VERSION 5.8 ;
BUSBITCHARS "[]" ;
DIVIDERCHAR "/" ;
UNITS
    DATABASE MICRONS 1000 ;
END UNITS

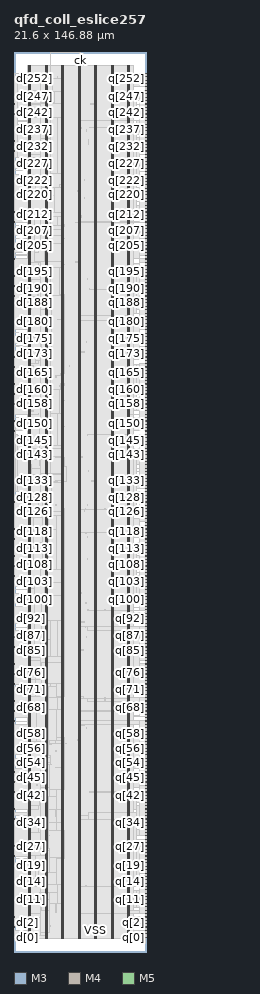
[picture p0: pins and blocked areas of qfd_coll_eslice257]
MACRO qfd_coll_eslice257
  FOREIGN qfd_coll_eslice257 0 0 ;
  CLASS BLOCK ;
  SIZE 21.6 BY 146.88 ;
  PIN ck
    DIRECTION INPUT ;
    USE SIGNAL ;
    PORT
      LAYER M3 ;
        RECT  10.8 146.842 10.818 146.88 ;
    END
    PORT
      LAYER M3 ;
        RECT  10.8 146.731 10.818 146.861 ;
    END
  END ck
  PIN d[0]
    DIRECTION INPUT ;
    USE SIGNAL ;
    PORT
      LAYER M4 ;
        RECT  0 2.4 0.084 2.424 ;
    END
  END d[0]
  PIN d[100]
    DIRECTION INPUT ;
    USE SIGNAL ;
    PORT
      LAYER M4 ;
        RECT  0 57.456 0.084 57.48 ;
    END
  END d[100]
  PIN d[101]
    DIRECTION INPUT ;
    USE SIGNAL ;
    PORT
      LAYER M4 ;
        RECT  0 58.032 0.084 58.056 ;
    END
  END d[101]
  PIN d[102]
    DIRECTION INPUT ;
    USE SIGNAL ;
    PORT
      LAYER M4 ;
        RECT  0 58.56 0.084 58.584 ;
    END
  END d[102]
  PIN d[103]
    DIRECTION INPUT ;
    USE SIGNAL ;
    PORT
      LAYER M4 ;
        RECT  0 59.136 0.084 59.16 ;
    END
  END d[103]
  PIN d[104]
    DIRECTION INPUT ;
    USE SIGNAL ;
    PORT
      LAYER M4 ;
        RECT  0 59.664 0.084 59.688 ;
    END
  END d[104]
  PIN d[105]
    DIRECTION INPUT ;
    USE SIGNAL ;
    PORT
      LAYER M4 ;
        RECT  0 60.24 0.084 60.264 ;
    END
  END d[105]
  PIN d[106]
    DIRECTION INPUT ;
    USE SIGNAL ;
    PORT
      LAYER M4 ;
        RECT  0 60.768 0.084 60.792 ;
    END
  END d[106]
  PIN d[107]
    DIRECTION INPUT ;
    USE SIGNAL ;
    PORT
      LAYER M4 ;
        RECT  0 61.344 0.084 61.368 ;
    END
  END d[107]
  PIN d[108]
    DIRECTION INPUT ;
    USE SIGNAL ;
    PORT
      LAYER M4 ;
        RECT  0 61.872 0.084 61.896 ;
    END
  END d[108]
  PIN d[109]
    DIRECTION INPUT ;
    USE SIGNAL ;
    PORT
      LAYER M4 ;
        RECT  0 62.448 0.084 62.472 ;
    END
  END d[109]
  PIN d[10]
    DIRECTION INPUT ;
    USE SIGNAL ;
    PORT
      LAYER M4 ;
        RECT  0 7.92 0.084 7.944 ;
    END
  END d[10]
  PIN d[110]
    DIRECTION INPUT ;
    USE SIGNAL ;
    PORT
      LAYER M4 ;
        RECT  0 62.976 0.084 63 ;
    END
  END d[110]
  PIN d[111]
    DIRECTION INPUT ;
    USE SIGNAL ;
    PORT
      LAYER M4 ;
        RECT  0 63.552 0.084 63.576 ;
    END
  END d[111]
  PIN d[112]
    DIRECTION INPUT ;
    USE SIGNAL ;
    PORT
      LAYER M4 ;
        RECT  0 64.08 0.084 64.104 ;
    END
  END d[112]
  PIN d[113]
    DIRECTION INPUT ;
    USE SIGNAL ;
    PORT
      LAYER M4 ;
        RECT  0 64.608 0.084 64.632 ;
    END
  END d[113]
  PIN d[114]
    DIRECTION INPUT ;
    USE SIGNAL ;
    PORT
      LAYER M4 ;
        RECT  0 65.184 0.084 65.208 ;
    END
  END d[114]
  PIN d[115]
    DIRECTION INPUT ;
    USE SIGNAL ;
    PORT
      LAYER M4 ;
        RECT  0 65.712 0.084 65.736 ;
    END
  END d[115]
  PIN d[116]
    DIRECTION INPUT ;
    USE SIGNAL ;
    PORT
      LAYER M4 ;
        RECT  0 66.288 0.084 66.312 ;
    END
  END d[116]
  PIN d[117]
    DIRECTION INPUT ;
    USE SIGNAL ;
    PORT
      LAYER M4 ;
        RECT  0 66.816 0.084 66.84 ;
    END
  END d[117]
  PIN d[118]
    DIRECTION INPUT ;
    USE SIGNAL ;
    PORT
      LAYER M4 ;
        RECT  0 67.392 0.084 67.416 ;
    END
  END d[118]
  PIN d[119]
    DIRECTION INPUT ;
    USE SIGNAL ;
    PORT
      LAYER M4 ;
        RECT  0 67.92 0.084 67.944 ;
    END
  END d[119]
  PIN d[11]
    DIRECTION INPUT ;
    USE SIGNAL ;
    PORT
      LAYER M4 ;
        RECT  0 8.496 0.084 8.52 ;
    END
  END d[11]
  PIN d[120]
    DIRECTION INPUT ;
    USE SIGNAL ;
    PORT
      LAYER M4 ;
        RECT  0 68.496 0.084 68.52 ;
    END
  END d[120]
  PIN d[121]
    DIRECTION INPUT ;
    USE SIGNAL ;
    PORT
      LAYER M4 ;
        RECT  0 69.024 0.084 69.048 ;
    END
  END d[121]
  PIN d[122]
    DIRECTION INPUT ;
    USE SIGNAL ;
    PORT
      LAYER M4 ;
        RECT  0 69.6 0.084 69.624 ;
    END
  END d[122]
  PIN d[123]
    DIRECTION INPUT ;
    USE SIGNAL ;
    PORT
      LAYER M4 ;
        RECT  0 70.128 0.084 70.152 ;
    END
  END d[123]
  PIN d[124]
    DIRECTION INPUT ;
    USE SIGNAL ;
    PORT
      LAYER M4 ;
        RECT  0 70.704 0.084 70.728 ;
    END
  END d[124]
  PIN d[125]
    DIRECTION INPUT ;
    USE SIGNAL ;
    PORT
      LAYER M4 ;
        RECT  0 71.232 0.084 71.256 ;
    END
  END d[125]
  PIN d[126]
    DIRECTION INPUT ;
    USE SIGNAL ;
    PORT
      LAYER M4 ;
        RECT  0 71.808 0.084 71.832 ;
    END
  END d[126]
  PIN d[127]
    DIRECTION INPUT ;
    USE SIGNAL ;
    PORT
      LAYER M4 ;
        RECT  0 72.336 0.084 72.36 ;
    END
  END d[127]
  PIN d[128]
    DIRECTION INPUT ;
    USE SIGNAL ;
    PORT
      LAYER M4 ;
        RECT  0 72.912 0.084 72.936 ;
    END
  END d[128]
  PIN d[129]
    DIRECTION INPUT ;
    USE SIGNAL ;
    PORT
      LAYER M4 ;
        RECT  0 73.44 0.084 73.464 ;
    END
  END d[129]
  PIN d[12]
    DIRECTION INPUT ;
    USE SIGNAL ;
    PORT
      LAYER M4 ;
        RECT  0 9.024 0.084 9.048 ;
    END
  END d[12]
  PIN d[130]
    DIRECTION INPUT ;
    USE SIGNAL ;
    PORT
      LAYER M4 ;
        RECT  0 73.968 0.084 73.992 ;
    END
  END d[130]
  PIN d[131]
    DIRECTION INPUT ;
    USE SIGNAL ;
    PORT
      LAYER M4 ;
        RECT  0 74.544 0.084 74.568 ;
    END
  END d[131]
  PIN d[132]
    DIRECTION INPUT ;
    USE SIGNAL ;
    PORT
      LAYER M4 ;
        RECT  0 75.072 0.084 75.096 ;
    END
  END d[132]
  PIN d[133]
    DIRECTION INPUT ;
    USE SIGNAL ;
    PORT
      LAYER M4 ;
        RECT  0 75.648 0.084 75.672 ;
    END
  END d[133]
  PIN d[134]
    DIRECTION INPUT ;
    USE SIGNAL ;
    PORT
      LAYER M4 ;
        RECT  0 76.176 0.084 76.2 ;
    END
  END d[134]
  PIN d[135]
    DIRECTION INPUT ;
    USE SIGNAL ;
    PORT
      LAYER M4 ;
        RECT  0 76.752 0.084 76.776 ;
    END
  END d[135]
  PIN d[136]
    DIRECTION INPUT ;
    USE SIGNAL ;
    PORT
      LAYER M4 ;
        RECT  0 77.28 0.084 77.304 ;
    END
  END d[136]
  PIN d[137]
    DIRECTION INPUT ;
    USE SIGNAL ;
    PORT
      LAYER M4 ;
        RECT  0 77.856 0.084 77.88 ;
    END
  END d[137]
  PIN d[138]
    DIRECTION INPUT ;
    USE SIGNAL ;
    PORT
      LAYER M4 ;
        RECT  0 78.384 0.084 78.408 ;
    END
  END d[138]
  PIN d[139]
    DIRECTION INPUT ;
    USE SIGNAL ;
    PORT
      LAYER M4 ;
        RECT  0 78.96 0.084 78.984 ;
    END
  END d[139]
  PIN d[13]
    DIRECTION INPUT ;
    USE SIGNAL ;
    PORT
      LAYER M4 ;
        RECT  0 9.6 0.084 9.624 ;
    END
  END d[13]
  PIN d[140]
    DIRECTION INPUT ;
    USE SIGNAL ;
    PORT
      LAYER M4 ;
        RECT  0 79.488 0.084 79.512 ;
    END
  END d[140]
  PIN d[141]
    DIRECTION INPUT ;
    USE SIGNAL ;
    PORT
      LAYER M4 ;
        RECT  0 80.064 0.084 80.088 ;
    END
  END d[141]
  PIN d[142]
    DIRECTION INPUT ;
    USE SIGNAL ;
    PORT
      LAYER M4 ;
        RECT  0 80.592 0.084 80.616 ;
    END
  END d[142]
  PIN d[143]
    DIRECTION INPUT ;
    USE SIGNAL ;
    PORT
      LAYER M4 ;
        RECT  0 81.168 0.084 81.192 ;
    END
  END d[143]
  PIN d[144]
    DIRECTION INPUT ;
    USE SIGNAL ;
    PORT
      LAYER M4 ;
        RECT  0 81.696 0.084 81.72 ;
    END
  END d[144]
  PIN d[145]
    DIRECTION INPUT ;
    USE SIGNAL ;
    PORT
      LAYER M4 ;
        RECT  0 82.224 0.084 82.248 ;
    END
  END d[145]
  PIN d[146]
    DIRECTION INPUT ;
    USE SIGNAL ;
    PORT
      LAYER M4 ;
        RECT  0 82.8 0.084 82.824 ;
    END
  END d[146]
  PIN d[147]
    DIRECTION INPUT ;
    USE SIGNAL ;
    PORT
      LAYER M4 ;
        RECT  0 83.328 0.084 83.352 ;
    END
  END d[147]
  PIN d[148]
    DIRECTION INPUT ;
    USE SIGNAL ;
    PORT
      LAYER M4 ;
        RECT  0 83.904 0.084 83.928 ;
    END
  END d[148]
  PIN d[149]
    DIRECTION INPUT ;
    USE SIGNAL ;
    PORT
      LAYER M4 ;
        RECT  0 84.432 0.084 84.456 ;
    END
  END d[149]
  PIN d[14]
    DIRECTION INPUT ;
    USE SIGNAL ;
    PORT
      LAYER M4 ;
        RECT  0 10.128 0.084 10.152 ;
    END
  END d[14]
  PIN d[150]
    DIRECTION INPUT ;
    USE SIGNAL ;
    PORT
      LAYER M4 ;
        RECT  0 85.008 0.084 85.032 ;
    END
  END d[150]
  PIN d[151]
    DIRECTION INPUT ;
    USE SIGNAL ;
    PORT
      LAYER M4 ;
        RECT  0 85.536 0.084 85.56 ;
    END
  END d[151]
  PIN d[152]
    DIRECTION INPUT ;
    USE SIGNAL ;
    PORT
      LAYER M4 ;
        RECT  0 86.112 0.084 86.136 ;
    END
  END d[152]
  PIN d[153]
    DIRECTION INPUT ;
    USE SIGNAL ;
    PORT
      LAYER M4 ;
        RECT  0 86.64 0.084 86.664 ;
    END
  END d[153]
  PIN d[154]
    DIRECTION INPUT ;
    USE SIGNAL ;
    PORT
      LAYER M4 ;
        RECT  0 87.216 0.084 87.24 ;
    END
  END d[154]
  PIN d[155]
    DIRECTION INPUT ;
    USE SIGNAL ;
    PORT
      LAYER M4 ;
        RECT  0 87.744 0.084 87.768 ;
    END
  END d[155]
  PIN d[156]
    DIRECTION INPUT ;
    USE SIGNAL ;
    PORT
      LAYER M4 ;
        RECT  0 88.32 0.084 88.344 ;
    END
  END d[156]
  PIN d[157]
    DIRECTION INPUT ;
    USE SIGNAL ;
    PORT
      LAYER M4 ;
        RECT  0 88.848 0.084 88.872 ;
    END
  END d[157]
  PIN d[158]
    DIRECTION INPUT ;
    USE SIGNAL ;
    PORT
      LAYER M4 ;
        RECT  0 89.424 0.084 89.448 ;
    END
  END d[158]
  PIN d[159]
    DIRECTION INPUT ;
    USE SIGNAL ;
    PORT
      LAYER M4 ;
        RECT  0 89.952 0.084 89.976 ;
    END
  END d[159]
  PIN d[15]
    DIRECTION INPUT ;
    USE SIGNAL ;
    PORT
      LAYER M4 ;
        RECT  0 10.704 0.084 10.728 ;
    END
  END d[15]
  PIN d[160]
    DIRECTION INPUT ;
    USE SIGNAL ;
    PORT
      LAYER M4 ;
        RECT  0 90.528 0.084 90.552 ;
    END
  END d[160]
  PIN d[161]
    DIRECTION INPUT ;
    USE SIGNAL ;
    PORT
      LAYER M4 ;
        RECT  0 91.056 0.084 91.08 ;
    END
  END d[161]
  PIN d[162]
    DIRECTION INPUT ;
    USE SIGNAL ;
    PORT
      LAYER M4 ;
        RECT  0 91.584 0.084 91.608 ;
    END
  END d[162]
  PIN d[163]
    DIRECTION INPUT ;
    USE SIGNAL ;
    PORT
      LAYER M4 ;
        RECT  0 92.16 0.084 92.184 ;
    END
  END d[163]
  PIN d[164]
    DIRECTION INPUT ;
    USE SIGNAL ;
    PORT
      LAYER M4 ;
        RECT  0 92.688 0.084 92.712 ;
    END
  END d[164]
  PIN d[165]
    DIRECTION INPUT ;
    USE SIGNAL ;
    PORT
      LAYER M4 ;
        RECT  0 93.264 0.084 93.288 ;
    END
  END d[165]
  PIN d[166]
    DIRECTION INPUT ;
    USE SIGNAL ;
    PORT
      LAYER M4 ;
        RECT  0 93.792 0.084 93.816 ;
    END
  END d[166]
  PIN d[167]
    DIRECTION INPUT ;
    USE SIGNAL ;
    PORT
      LAYER M4 ;
        RECT  0 94.368 0.084 94.392 ;
    END
  END d[167]
  PIN d[168]
    DIRECTION INPUT ;
    USE SIGNAL ;
    PORT
      LAYER M4 ;
        RECT  0 94.896 0.084 94.92 ;
    END
  END d[168]
  PIN d[169]
    DIRECTION INPUT ;
    USE SIGNAL ;
    PORT
      LAYER M4 ;
        RECT  0 95.472 0.084 95.496 ;
    END
  END d[169]
  PIN d[16]
    DIRECTION INPUT ;
    USE SIGNAL ;
    PORT
      LAYER M4 ;
        RECT  0 11.232 0.084 11.256 ;
    END
  END d[16]
  PIN d[170]
    DIRECTION INPUT ;
    USE SIGNAL ;
    PORT
      LAYER M4 ;
        RECT  0 96 0.084 96.024 ;
    END
  END d[170]
  PIN d[171]
    DIRECTION INPUT ;
    USE SIGNAL ;
    PORT
      LAYER M4 ;
        RECT  0 96.576 0.084 96.6 ;
    END
  END d[171]
  PIN d[172]
    DIRECTION INPUT ;
    USE SIGNAL ;
    PORT
      LAYER M4 ;
        RECT  0 97.104 0.084 97.128 ;
    END
  END d[172]
  PIN d[173]
    DIRECTION INPUT ;
    USE SIGNAL ;
    PORT
      LAYER M4 ;
        RECT  0 97.68 0.084 97.704 ;
    END
  END d[173]
  PIN d[174]
    DIRECTION INPUT ;
    USE SIGNAL ;
    PORT
      LAYER M4 ;
        RECT  0 98.208 0.084 98.232 ;
    END
  END d[174]
  PIN d[175]
    DIRECTION INPUT ;
    USE SIGNAL ;
    PORT
      LAYER M4 ;
        RECT  0 98.784 0.084 98.808 ;
    END
  END d[175]
  PIN d[176]
    DIRECTION INPUT ;
    USE SIGNAL ;
    PORT
      LAYER M4 ;
        RECT  0 99.312 0.084 99.336 ;
    END
  END d[176]
  PIN d[177]
    DIRECTION INPUT ;
    USE SIGNAL ;
    PORT
      LAYER M4 ;
        RECT  0 99.84 0.084 99.864 ;
    END
  END d[177]
  PIN d[178]
    DIRECTION INPUT ;
    USE SIGNAL ;
    PORT
      LAYER M4 ;
        RECT  0 100.416 0.084 100.44 ;
    END
  END d[178]
  PIN d[179]
    DIRECTION INPUT ;
    USE SIGNAL ;
    PORT
      LAYER M4 ;
        RECT  0 100.944 0.084 100.968 ;
    END
  END d[179]
  PIN d[17]
    DIRECTION INPUT ;
    USE SIGNAL ;
    PORT
      LAYER M4 ;
        RECT  0 11.76 0.084 11.784 ;
    END
  END d[17]
  PIN d[180]
    DIRECTION INPUT ;
    USE SIGNAL ;
    PORT
      LAYER M4 ;
        RECT  0 101.52 0.084 101.544 ;
    END
  END d[180]
  PIN d[181]
    DIRECTION INPUT ;
    USE SIGNAL ;
    PORT
      LAYER M4 ;
        RECT  0 102.048 0.084 102.072 ;
    END
  END d[181]
  PIN d[182]
    DIRECTION INPUT ;
    USE SIGNAL ;
    PORT
      LAYER M4 ;
        RECT  0 102.624 0.084 102.648 ;
    END
  END d[182]
  PIN d[183]
    DIRECTION INPUT ;
    USE SIGNAL ;
    PORT
      LAYER M4 ;
        RECT  0 103.152 0.084 103.176 ;
    END
  END d[183]
  PIN d[184]
    DIRECTION INPUT ;
    USE SIGNAL ;
    PORT
      LAYER M4 ;
        RECT  0 103.728 0.084 103.752 ;
    END
  END d[184]
  PIN d[185]
    DIRECTION INPUT ;
    USE SIGNAL ;
    PORT
      LAYER M4 ;
        RECT  0 104.256 0.084 104.28 ;
    END
  END d[185]
  PIN d[186]
    DIRECTION INPUT ;
    USE SIGNAL ;
    PORT
      LAYER M4 ;
        RECT  0 104.832 0.084 104.856 ;
    END
  END d[186]
  PIN d[187]
    DIRECTION INPUT ;
    USE SIGNAL ;
    PORT
      LAYER M4 ;
        RECT  0 105.36 0.084 105.384 ;
    END
  END d[187]
  PIN d[188]
    DIRECTION INPUT ;
    USE SIGNAL ;
    PORT
      LAYER M4 ;
        RECT  0 105.936 0.084 105.96 ;
    END
  END d[188]
  PIN d[189]
    DIRECTION INPUT ;
    USE SIGNAL ;
    PORT
      LAYER M4 ;
        RECT  0 106.464 0.084 106.488 ;
    END
  END d[189]
  PIN d[18]
    DIRECTION INPUT ;
    USE SIGNAL ;
    PORT
      LAYER M4 ;
        RECT  0 12.336 0.084 12.36 ;
    END
  END d[18]
  PIN d[190]
    DIRECTION INPUT ;
    USE SIGNAL ;
    PORT
      LAYER M4 ;
        RECT  0 107.04 0.084 107.064 ;
    END
  END d[190]
  PIN d[191]
    DIRECTION INPUT ;
    USE SIGNAL ;
    PORT
      LAYER M4 ;
        RECT  0 107.568 0.084 107.592 ;
    END
  END d[191]
  PIN d[192]
    DIRECTION INPUT ;
    USE SIGNAL ;
    PORT
      LAYER M4 ;
        RECT  0 108.144 0.084 108.168 ;
    END
  END d[192]
  PIN d[193]
    DIRECTION INPUT ;
    USE SIGNAL ;
    PORT
      LAYER M4 ;
        RECT  0 108.672 0.084 108.696 ;
    END
  END d[193]
  PIN d[194]
    DIRECTION INPUT ;
    USE SIGNAL ;
    PORT
      LAYER M4 ;
        RECT  0 109.2 0.084 109.224 ;
    END
  END d[194]
  PIN d[195]
    DIRECTION INPUT ;
    USE SIGNAL ;
    PORT
      LAYER M4 ;
        RECT  0 109.776 0.084 109.8 ;
    END
  END d[195]
  PIN d[196]
    DIRECTION INPUT ;
    USE SIGNAL ;
    PORT
      LAYER M4 ;
        RECT  0 110.304 0.084 110.328 ;
    END
  END d[196]
  PIN d[197]
    DIRECTION INPUT ;
    USE SIGNAL ;
    PORT
      LAYER M4 ;
        RECT  0 110.88 0.084 110.904 ;
    END
  END d[197]
  PIN d[198]
    DIRECTION INPUT ;
    USE SIGNAL ;
    PORT
      LAYER M4 ;
        RECT  0 111.408 0.084 111.432 ;
    END
  END d[198]
  PIN d[199]
    DIRECTION INPUT ;
    USE SIGNAL ;
    PORT
      LAYER M4 ;
        RECT  0 111.984 0.084 112.008 ;
    END
  END d[199]
  PIN d[19]
    DIRECTION INPUT ;
    USE SIGNAL ;
    PORT
      LAYER M4 ;
        RECT  0 12.864 0.084 12.888 ;
    END
  END d[19]
  PIN d[1]
    DIRECTION INPUT ;
    USE SIGNAL ;
    PORT
      LAYER M4 ;
        RECT  0 2.976 0.084 3 ;
    END
  END d[1]
  PIN d[200]
    DIRECTION INPUT ;
    USE SIGNAL ;
    PORT
      LAYER M4 ;
        RECT  0 112.512 0.084 112.536 ;
    END
  END d[200]
  PIN d[201]
    DIRECTION INPUT ;
    USE SIGNAL ;
    PORT
      LAYER M4 ;
        RECT  0 113.088 0.084 113.112 ;
    END
  END d[201]
  PIN d[202]
    DIRECTION INPUT ;
    USE SIGNAL ;
    PORT
      LAYER M4 ;
        RECT  0 113.616 0.084 113.64 ;
    END
  END d[202]
  PIN d[203]
    DIRECTION INPUT ;
    USE SIGNAL ;
    PORT
      LAYER M4 ;
        RECT  0 114.192 0.084 114.216 ;
    END
  END d[203]
  PIN d[204]
    DIRECTION INPUT ;
    USE SIGNAL ;
    PORT
      LAYER M4 ;
        RECT  0 114.72 0.084 114.744 ;
    END
  END d[204]
  PIN d[205]
    DIRECTION INPUT ;
    USE SIGNAL ;
    PORT
      LAYER M4 ;
        RECT  0 115.296 0.084 115.32 ;
    END
  END d[205]
  PIN d[206]
    DIRECTION INPUT ;
    USE SIGNAL ;
    PORT
      LAYER M4 ;
        RECT  0 115.824 0.084 115.848 ;
    END
  END d[206]
  PIN d[207]
    DIRECTION INPUT ;
    USE SIGNAL ;
    PORT
      LAYER M4 ;
        RECT  0 116.4 0.084 116.424 ;
    END
  END d[207]
  PIN d[208]
    DIRECTION INPUT ;
    USE SIGNAL ;
    PORT
      LAYER M4 ;
        RECT  0 116.928 0.084 116.952 ;
    END
  END d[208]
  PIN d[209]
    DIRECTION INPUT ;
    USE SIGNAL ;
    PORT
      LAYER M4 ;
        RECT  0 117.456 0.084 117.48 ;
    END
  END d[209]
  PIN d[20]
    DIRECTION INPUT ;
    USE SIGNAL ;
    PORT
      LAYER M4 ;
        RECT  0 13.44 0.084 13.464 ;
    END
  END d[20]
  PIN d[210]
    DIRECTION INPUT ;
    USE SIGNAL ;
    PORT
      LAYER M4 ;
        RECT  0 118.032 0.084 118.056 ;
    END
  END d[210]
  PIN d[211]
    DIRECTION INPUT ;
    USE SIGNAL ;
    PORT
      LAYER M4 ;
        RECT  0 118.56 0.084 118.584 ;
    END
  END d[211]
  PIN d[212]
    DIRECTION INPUT ;
    USE SIGNAL ;
    PORT
      LAYER M4 ;
        RECT  0 119.136 0.084 119.16 ;
    END
  END d[212]
  PIN d[213]
    DIRECTION INPUT ;
    USE SIGNAL ;
    PORT
      LAYER M4 ;
        RECT  0 119.664 0.084 119.688 ;
    END
  END d[213]
  PIN d[214]
    DIRECTION INPUT ;
    USE SIGNAL ;
    PORT
      LAYER M4 ;
        RECT  0 120.24 0.084 120.264 ;
    END
  END d[214]
  PIN d[215]
    DIRECTION INPUT ;
    USE SIGNAL ;
    PORT
      LAYER M4 ;
        RECT  0 120.768 0.084 120.792 ;
    END
  END d[215]
  PIN d[216]
    DIRECTION INPUT ;
    USE SIGNAL ;
    PORT
      LAYER M4 ;
        RECT  0 121.344 0.084 121.368 ;
    END
  END d[216]
  PIN d[217]
    DIRECTION INPUT ;
    USE SIGNAL ;
    PORT
      LAYER M4 ;
        RECT  0 121.872 0.084 121.896 ;
    END
  END d[217]
  PIN d[218]
    DIRECTION INPUT ;
    USE SIGNAL ;
    PORT
      LAYER M4 ;
        RECT  0 122.448 0.084 122.472 ;
    END
  END d[218]
  PIN d[219]
    DIRECTION INPUT ;
    USE SIGNAL ;
    PORT
      LAYER M4 ;
        RECT  0 122.976 0.084 123 ;
    END
  END d[219]
  PIN d[21]
    DIRECTION INPUT ;
    USE SIGNAL ;
    PORT
      LAYER M4 ;
        RECT  0 13.968 0.084 13.992 ;
    END
  END d[21]
  PIN d[220]
    DIRECTION INPUT ;
    USE SIGNAL ;
    PORT
      LAYER M4 ;
        RECT  0 123.552 0.084 123.576 ;
    END
  END d[220]
  PIN d[221]
    DIRECTION INPUT ;
    USE SIGNAL ;
    PORT
      LAYER M4 ;
        RECT  0 124.08 0.084 124.104 ;
    END
  END d[221]
  PIN d[222]
    DIRECTION INPUT ;
    USE SIGNAL ;
    PORT
      LAYER M4 ;
        RECT  0 124.656 0.084 124.68 ;
    END
  END d[222]
  PIN d[223]
    DIRECTION INPUT ;
    USE SIGNAL ;
    PORT
      LAYER M4 ;
        RECT  0 125.184 0.084 125.208 ;
    END
  END d[223]
  PIN d[224]
    DIRECTION INPUT ;
    USE SIGNAL ;
    PORT
      LAYER M4 ;
        RECT  0 125.76 0.084 125.784 ;
    END
  END d[224]
  PIN d[225]
    DIRECTION INPUT ;
    USE SIGNAL ;
    PORT
      LAYER M4 ;
        RECT  0 126.288 0.084 126.312 ;
    END
  END d[225]
  PIN d[226]
    DIRECTION INPUT ;
    USE SIGNAL ;
    PORT
      LAYER M4 ;
        RECT  0 126.816 0.084 126.84 ;
    END
  END d[226]
  PIN d[227]
    DIRECTION INPUT ;
    USE SIGNAL ;
    PORT
      LAYER M4 ;
        RECT  0 127.392 0.084 127.416 ;
    END
  END d[227]
  PIN d[228]
    DIRECTION INPUT ;
    USE SIGNAL ;
    PORT
      LAYER M4 ;
        RECT  0 127.92 0.084 127.944 ;
    END
  END d[228]
  PIN d[229]
    DIRECTION INPUT ;
    USE SIGNAL ;
    PORT
      LAYER M4 ;
        RECT  0 128.496 0.084 128.52 ;
    END
  END d[229]
  PIN d[22]
    DIRECTION INPUT ;
    USE SIGNAL ;
    PORT
      LAYER M4 ;
        RECT  0 14.544 0.084 14.568 ;
    END
  END d[22]
  PIN d[230]
    DIRECTION INPUT ;
    USE SIGNAL ;
    PORT
      LAYER M4 ;
        RECT  0 129.024 0.084 129.048 ;
    END
  END d[230]
  PIN d[231]
    DIRECTION INPUT ;
    USE SIGNAL ;
    PORT
      LAYER M4 ;
        RECT  0 129.6 0.084 129.624 ;
    END
  END d[231]
  PIN d[232]
    DIRECTION INPUT ;
    USE SIGNAL ;
    PORT
      LAYER M4 ;
        RECT  0 130.128 0.084 130.152 ;
    END
  END d[232]
  PIN d[233]
    DIRECTION INPUT ;
    USE SIGNAL ;
    PORT
      LAYER M4 ;
        RECT  0 130.704 0.084 130.728 ;
    END
  END d[233]
  PIN d[234]
    DIRECTION INPUT ;
    USE SIGNAL ;
    PORT
      LAYER M4 ;
        RECT  0 131.232 0.084 131.256 ;
    END
  END d[234]
  PIN d[235]
    DIRECTION INPUT ;
    USE SIGNAL ;
    PORT
      LAYER M4 ;
        RECT  0 131.808 0.084 131.832 ;
    END
  END d[235]
  PIN d[236]
    DIRECTION INPUT ;
    USE SIGNAL ;
    PORT
      LAYER M4 ;
        RECT  0 132.336 0.084 132.36 ;
    END
  END d[236]
  PIN d[237]
    DIRECTION INPUT ;
    USE SIGNAL ;
    PORT
      LAYER M4 ;
        RECT  0 132.912 0.084 132.936 ;
    END
  END d[237]
  PIN d[238]
    DIRECTION INPUT ;
    USE SIGNAL ;
    PORT
      LAYER M4 ;
        RECT  0 133.44 0.084 133.464 ;
    END
  END d[238]
  PIN d[239]
    DIRECTION INPUT ;
    USE SIGNAL ;
    PORT
      LAYER M4 ;
        RECT  0 134.016 0.084 134.04 ;
    END
  END d[239]
  PIN d[23]
    DIRECTION INPUT ;
    USE SIGNAL ;
    PORT
      LAYER M4 ;
        RECT  0 15.072 0.084 15.096 ;
    END
  END d[23]
  PIN d[240]
    DIRECTION INPUT ;
    USE SIGNAL ;
    PORT
      LAYER M4 ;
        RECT  0 134.544 0.084 134.568 ;
    END
  END d[240]
  PIN d[241]
    DIRECTION INPUT ;
    USE SIGNAL ;
    PORT
      LAYER M4 ;
        RECT  0 135.072 0.084 135.096 ;
    END
  END d[241]
  PIN d[242]
    DIRECTION INPUT ;
    USE SIGNAL ;
    PORT
      LAYER M4 ;
        RECT  0 135.648 0.084 135.672 ;
    END
  END d[242]
  PIN d[243]
    DIRECTION INPUT ;
    USE SIGNAL ;
    PORT
      LAYER M4 ;
        RECT  0 136.176 0.084 136.2 ;
    END
  END d[243]
  PIN d[244]
    DIRECTION INPUT ;
    USE SIGNAL ;
    PORT
      LAYER M4 ;
        RECT  0 136.752 0.084 136.776 ;
    END
  END d[244]
  PIN d[245]
    DIRECTION INPUT ;
    USE SIGNAL ;
    PORT
      LAYER M4 ;
        RECT  0 137.28 0.084 137.304 ;
    END
  END d[245]
  PIN d[246]
    DIRECTION INPUT ;
    USE SIGNAL ;
    PORT
      LAYER M4 ;
        RECT  0 137.856 0.084 137.88 ;
    END
  END d[246]
  PIN d[247]
    DIRECTION INPUT ;
    USE SIGNAL ;
    PORT
      LAYER M4 ;
        RECT  0 138.384 0.084 138.408 ;
    END
  END d[247]
  PIN d[248]
    DIRECTION INPUT ;
    USE SIGNAL ;
    PORT
      LAYER M4 ;
        RECT  0 138.96 0.084 138.984 ;
    END
  END d[248]
  PIN d[249]
    DIRECTION INPUT ;
    USE SIGNAL ;
    PORT
      LAYER M4 ;
        RECT  0 139.488 0.084 139.512 ;
    END
  END d[249]
  PIN d[24]
    DIRECTION INPUT ;
    USE SIGNAL ;
    PORT
      LAYER M4 ;
        RECT  0 15.648 0.084 15.672 ;
    END
  END d[24]
  PIN d[250]
    DIRECTION INPUT ;
    USE SIGNAL ;
    PORT
      LAYER M4 ;
        RECT  0 140.064 0.084 140.088 ;
    END
  END d[250]
  PIN d[251]
    DIRECTION INPUT ;
    USE SIGNAL ;
    PORT
      LAYER M4 ;
        RECT  0 140.592 0.084 140.616 ;
    END
  END d[251]
  PIN d[252]
    DIRECTION INPUT ;
    USE SIGNAL ;
    PORT
      LAYER M4 ;
        RECT  0 141.168 0.084 141.192 ;
    END
  END d[252]
  PIN d[253]
    DIRECTION INPUT ;
    USE SIGNAL ;
    PORT
      LAYER M4 ;
        RECT  0 141.696 0.084 141.72 ;
    END
  END d[253]
  PIN d[254]
    DIRECTION INPUT ;
    USE SIGNAL ;
    PORT
      LAYER M4 ;
        RECT  0 142.272 0.084 142.296 ;
    END
  END d[254]
  PIN d[255]
    DIRECTION INPUT ;
    USE SIGNAL ;
    PORT
      LAYER M4 ;
        RECT  0 142.8 0.084 142.824 ;
    END
  END d[255]
  PIN d[256]
    DIRECTION INPUT ;
    USE SIGNAL ;
    PORT
      LAYER M4 ;
        RECT  0 143.376 0.084 143.4 ;
    END
  END d[256]
  PIN d[25]
    DIRECTION INPUT ;
    USE SIGNAL ;
    PORT
      LAYER M4 ;
        RECT  0 16.176 0.084 16.2 ;
    END
  END d[25]
  PIN d[26]
    DIRECTION INPUT ;
    USE SIGNAL ;
    PORT
      LAYER M4 ;
        RECT  0 16.752 0.084 16.776 ;
    END
  END d[26]
  PIN d[27]
    DIRECTION INPUT ;
    USE SIGNAL ;
    PORT
      LAYER M4 ;
        RECT  0 17.28 0.084 17.304 ;
    END
  END d[27]
  PIN d[28]
    DIRECTION INPUT ;
    USE SIGNAL ;
    PORT
      LAYER M4 ;
        RECT  0 17.856 0.084 17.88 ;
    END
  END d[28]
  PIN d[29]
    DIRECTION INPUT ;
    USE SIGNAL ;
    PORT
      LAYER M4 ;
        RECT  0 18.384 0.084 18.408 ;
    END
  END d[29]
  PIN d[2]
    DIRECTION INPUT ;
    USE SIGNAL ;
    PORT
      LAYER M4 ;
        RECT  0 3.504 0.084 3.528 ;
    END
  END d[2]
  PIN d[30]
    DIRECTION INPUT ;
    USE SIGNAL ;
    PORT
      LAYER M4 ;
        RECT  0 18.96 0.084 18.984 ;
    END
  END d[30]
  PIN d[31]
    DIRECTION INPUT ;
    USE SIGNAL ;
    PORT
      LAYER M4 ;
        RECT  0 19.488 0.084 19.512 ;
    END
  END d[31]
  PIN d[32]
    DIRECTION INPUT ;
    USE SIGNAL ;
    PORT
      LAYER M4 ;
        RECT  0 20.016 0.084 20.04 ;
    END
  END d[32]
  PIN d[33]
    DIRECTION INPUT ;
    USE SIGNAL ;
    PORT
      LAYER M4 ;
        RECT  0 20.592 0.084 20.616 ;
    END
  END d[33]
  PIN d[34]
    DIRECTION INPUT ;
    USE SIGNAL ;
    PORT
      LAYER M4 ;
        RECT  0 21.12 0.084 21.144 ;
    END
  END d[34]
  PIN d[35]
    DIRECTION INPUT ;
    USE SIGNAL ;
    PORT
      LAYER M4 ;
        RECT  0 21.696 0.084 21.72 ;
    END
  END d[35]
  PIN d[36]
    DIRECTION INPUT ;
    USE SIGNAL ;
    PORT
      LAYER M4 ;
        RECT  0 22.224 0.084 22.248 ;
    END
  END d[36]
  PIN d[37]
    DIRECTION INPUT ;
    USE SIGNAL ;
    PORT
      LAYER M4 ;
        RECT  0 22.8 0.084 22.824 ;
    END
  END d[37]
  PIN d[38]
    DIRECTION INPUT ;
    USE SIGNAL ;
    PORT
      LAYER M4 ;
        RECT  0 23.328 0.084 23.352 ;
    END
  END d[38]
  PIN d[39]
    DIRECTION INPUT ;
    USE SIGNAL ;
    PORT
      LAYER M4 ;
        RECT  0 23.904 0.084 23.928 ;
    END
  END d[39]
  PIN d[3]
    DIRECTION INPUT ;
    USE SIGNAL ;
    PORT
      LAYER M4 ;
        RECT  0 4.08 0.084 4.104 ;
    END
  END d[3]
  PIN d[40]
    DIRECTION INPUT ;
    USE SIGNAL ;
    PORT
      LAYER M4 ;
        RECT  0 24.432 0.084 24.456 ;
    END
  END d[40]
  PIN d[41]
    DIRECTION INPUT ;
    USE SIGNAL ;
    PORT
      LAYER M4 ;
        RECT  0 25.008 0.084 25.032 ;
    END
  END d[41]
  PIN d[42]
    DIRECTION INPUT ;
    USE SIGNAL ;
    PORT
      LAYER M4 ;
        RECT  0 25.536 0.084 25.56 ;
    END
  END d[42]
  PIN d[43]
    DIRECTION INPUT ;
    USE SIGNAL ;
    PORT
      LAYER M4 ;
        RECT  0 26.112 0.084 26.136 ;
    END
  END d[43]
  PIN d[44]
    DIRECTION INPUT ;
    USE SIGNAL ;
    PORT
      LAYER M4 ;
        RECT  0 26.64 0.084 26.664 ;
    END
  END d[44]
  PIN d[45]
    DIRECTION INPUT ;
    USE SIGNAL ;
    PORT
      LAYER M4 ;
        RECT  0 27.216 0.084 27.24 ;
    END
  END d[45]
  PIN d[46]
    DIRECTION INPUT ;
    USE SIGNAL ;
    PORT
      LAYER M4 ;
        RECT  0 27.744 0.084 27.768 ;
    END
  END d[46]
  PIN d[47]
    DIRECTION INPUT ;
    USE SIGNAL ;
    PORT
      LAYER M4 ;
        RECT  0 28.32 0.084 28.344 ;
    END
  END d[47]
  PIN d[48]
    DIRECTION INPUT ;
    USE SIGNAL ;
    PORT
      LAYER M4 ;
        RECT  0 28.848 0.084 28.872 ;
    END
  END d[48]
  PIN d[49]
    DIRECTION INPUT ;
    USE SIGNAL ;
    PORT
      LAYER M4 ;
        RECT  0 29.376 0.084 29.4 ;
    END
  END d[49]
  PIN d[4]
    DIRECTION INPUT ;
    USE SIGNAL ;
    PORT
      LAYER M4 ;
        RECT  0 4.608 0.084 4.632 ;
    END
  END d[4]
  PIN d[50]
    DIRECTION INPUT ;
    USE SIGNAL ;
    PORT
      LAYER M4 ;
        RECT  0 29.952 0.084 29.976 ;
    END
  END d[50]
  PIN d[51]
    DIRECTION INPUT ;
    USE SIGNAL ;
    PORT
      LAYER M4 ;
        RECT  0 30.48 0.084 30.504 ;
    END
  END d[51]
  PIN d[52]
    DIRECTION INPUT ;
    USE SIGNAL ;
    PORT
      LAYER M4 ;
        RECT  0 31.056 0.084 31.08 ;
    END
  END d[52]
  PIN d[53]
    DIRECTION INPUT ;
    USE SIGNAL ;
    PORT
      LAYER M4 ;
        RECT  0 31.584 0.084 31.608 ;
    END
  END d[53]
  PIN d[54]
    DIRECTION INPUT ;
    USE SIGNAL ;
    PORT
      LAYER M4 ;
        RECT  0 32.16 0.084 32.184 ;
    END
  END d[54]
  PIN d[55]
    DIRECTION INPUT ;
    USE SIGNAL ;
    PORT
      LAYER M4 ;
        RECT  0 32.688 0.084 32.712 ;
    END
  END d[55]
  PIN d[56]
    DIRECTION INPUT ;
    USE SIGNAL ;
    PORT
      LAYER M4 ;
        RECT  0 33.264 0.084 33.288 ;
    END
  END d[56]
  PIN d[57]
    DIRECTION INPUT ;
    USE SIGNAL ;
    PORT
      LAYER M4 ;
        RECT  0 33.792 0.084 33.816 ;
    END
  END d[57]
  PIN d[58]
    DIRECTION INPUT ;
    USE SIGNAL ;
    PORT
      LAYER M4 ;
        RECT  0 34.368 0.084 34.392 ;
    END
  END d[58]
  PIN d[59]
    DIRECTION INPUT ;
    USE SIGNAL ;
    PORT
      LAYER M4 ;
        RECT  0 34.896 0.084 34.92 ;
    END
  END d[59]
  PIN d[5]
    DIRECTION INPUT ;
    USE SIGNAL ;
    PORT
      LAYER M4 ;
        RECT  0 5.184 0.084 5.208 ;
    END
  END d[5]
  PIN d[60]
    DIRECTION INPUT ;
    USE SIGNAL ;
    PORT
      LAYER M4 ;
        RECT  0 35.472 0.084 35.496 ;
    END
  END d[60]
  PIN d[61]
    DIRECTION INPUT ;
    USE SIGNAL ;
    PORT
      LAYER M4 ;
        RECT  0 36 0.084 36.024 ;
    END
  END d[61]
  PIN d[62]
    DIRECTION INPUT ;
    USE SIGNAL ;
    PORT
      LAYER M4 ;
        RECT  0 36.576 0.084 36.6 ;
    END
  END d[62]
  PIN d[63]
    DIRECTION INPUT ;
    USE SIGNAL ;
    PORT
      LAYER M4 ;
        RECT  0 37.104 0.084 37.128 ;
    END
  END d[63]
  PIN d[64]
    DIRECTION INPUT ;
    USE SIGNAL ;
    PORT
      LAYER M4 ;
        RECT  0 37.68 0.084 37.704 ;
    END
  END d[64]
  PIN d[65]
    DIRECTION INPUT ;
    USE SIGNAL ;
    PORT
      LAYER M4 ;
        RECT  0 38.208 0.084 38.232 ;
    END
  END d[65]
  PIN d[66]
    DIRECTION INPUT ;
    USE SIGNAL ;
    PORT
      LAYER M4 ;
        RECT  0 38.736 0.084 38.76 ;
    END
  END d[66]
  PIN d[67]
    DIRECTION INPUT ;
    USE SIGNAL ;
    PORT
      LAYER M4 ;
        RECT  0 39.312 0.084 39.336 ;
    END
  END d[67]
  PIN d[68]
    DIRECTION INPUT ;
    USE SIGNAL ;
    PORT
      LAYER M4 ;
        RECT  0 39.84 0.084 39.864 ;
    END
  END d[68]
  PIN d[69]
    DIRECTION INPUT ;
    USE SIGNAL ;
    PORT
      LAYER M4 ;
        RECT  0 40.416 0.084 40.44 ;
    END
  END d[69]
  PIN d[6]
    DIRECTION INPUT ;
    USE SIGNAL ;
    PORT
      LAYER M4 ;
        RECT  0 5.712 0.084 5.736 ;
    END
  END d[6]
  PIN d[70]
    DIRECTION INPUT ;
    USE SIGNAL ;
    PORT
      LAYER M4 ;
        RECT  0 40.944 0.084 40.968 ;
    END
  END d[70]
  PIN d[71]
    DIRECTION INPUT ;
    USE SIGNAL ;
    PORT
      LAYER M4 ;
        RECT  0 41.52 0.084 41.544 ;
    END
  END d[71]
  PIN d[72]
    DIRECTION INPUT ;
    USE SIGNAL ;
    PORT
      LAYER M4 ;
        RECT  0 42.048 0.084 42.072 ;
    END
  END d[72]
  PIN d[73]
    DIRECTION INPUT ;
    USE SIGNAL ;
    PORT
      LAYER M4 ;
        RECT  0 42.624 0.084 42.648 ;
    END
  END d[73]
  PIN d[74]
    DIRECTION INPUT ;
    USE SIGNAL ;
    PORT
      LAYER M4 ;
        RECT  0 43.152 0.084 43.176 ;
    END
  END d[74]
  PIN d[75]
    DIRECTION INPUT ;
    USE SIGNAL ;
    PORT
      LAYER M4 ;
        RECT  0 43.728 0.084 43.752 ;
    END
  END d[75]
  PIN d[76]
    DIRECTION INPUT ;
    USE SIGNAL ;
    PORT
      LAYER M4 ;
        RECT  0 44.256 0.084 44.28 ;
    END
  END d[76]
  PIN d[77]
    DIRECTION INPUT ;
    USE SIGNAL ;
    PORT
      LAYER M4 ;
        RECT  0 44.832 0.084 44.856 ;
    END
  END d[77]
  PIN d[78]
    DIRECTION INPUT ;
    USE SIGNAL ;
    PORT
      LAYER M4 ;
        RECT  0 45.36 0.084 45.384 ;
    END
  END d[78]
  PIN d[79]
    DIRECTION INPUT ;
    USE SIGNAL ;
    PORT
      LAYER M4 ;
        RECT  0 45.936 0.084 45.96 ;
    END
  END d[79]
  PIN d[7]
    DIRECTION INPUT ;
    USE SIGNAL ;
    PORT
      LAYER M4 ;
        RECT  0 6.288 0.084 6.312 ;
    END
  END d[7]
  PIN d[80]
    DIRECTION INPUT ;
    USE SIGNAL ;
    PORT
      LAYER M4 ;
        RECT  0 46.464 0.084 46.488 ;
    END
  END d[80]
  PIN d[81]
    DIRECTION INPUT ;
    USE SIGNAL ;
    PORT
      LAYER M4 ;
        RECT  0 46.992 0.084 47.016 ;
    END
  END d[81]
  PIN d[82]
    DIRECTION INPUT ;
    USE SIGNAL ;
    PORT
      LAYER M4 ;
        RECT  0 47.568 0.084 47.592 ;
    END
  END d[82]
  PIN d[83]
    DIRECTION INPUT ;
    USE SIGNAL ;
    PORT
      LAYER M4 ;
        RECT  0 48.096 0.084 48.12 ;
    END
  END d[83]
  PIN d[84]
    DIRECTION INPUT ;
    USE SIGNAL ;
    PORT
      LAYER M4 ;
        RECT  0 48.672 0.084 48.696 ;
    END
  END d[84]
  PIN d[85]
    DIRECTION INPUT ;
    USE SIGNAL ;
    PORT
      LAYER M4 ;
        RECT  0 49.2 0.084 49.224 ;
    END
  END d[85]
  PIN d[86]
    DIRECTION INPUT ;
    USE SIGNAL ;
    PORT
      LAYER M4 ;
        RECT  0 49.776 0.084 49.8 ;
    END
  END d[86]
  PIN d[87]
    DIRECTION INPUT ;
    USE SIGNAL ;
    PORT
      LAYER M4 ;
        RECT  0 50.304 0.084 50.328 ;
    END
  END d[87]
  PIN d[88]
    DIRECTION INPUT ;
    USE SIGNAL ;
    PORT
      LAYER M4 ;
        RECT  0 50.88 0.084 50.904 ;
    END
  END d[88]
  PIN d[89]
    DIRECTION INPUT ;
    USE SIGNAL ;
    PORT
      LAYER M4 ;
        RECT  0 51.408 0.084 51.432 ;
    END
  END d[89]
  PIN d[8]
    DIRECTION INPUT ;
    USE SIGNAL ;
    PORT
      LAYER M4 ;
        RECT  0 6.816 0.084 6.84 ;
    END
  END d[8]
  PIN d[90]
    DIRECTION INPUT ;
    USE SIGNAL ;
    PORT
      LAYER M4 ;
        RECT  0 51.984 0.084 52.008 ;
    END
  END d[90]
  PIN d[91]
    DIRECTION INPUT ;
    USE SIGNAL ;
    PORT
      LAYER M4 ;
        RECT  0 52.512 0.084 52.536 ;
    END
  END d[91]
  PIN d[92]
    DIRECTION INPUT ;
    USE SIGNAL ;
    PORT
      LAYER M4 ;
        RECT  0 53.088 0.084 53.112 ;
    END
  END d[92]
  PIN d[93]
    DIRECTION INPUT ;
    USE SIGNAL ;
    PORT
      LAYER M4 ;
        RECT  0 53.616 0.084 53.64 ;
    END
  END d[93]
  PIN d[94]
    DIRECTION INPUT ;
    USE SIGNAL ;
    PORT
      LAYER M4 ;
        RECT  0 54.192 0.084 54.216 ;
    END
  END d[94]
  PIN d[95]
    DIRECTION INPUT ;
    USE SIGNAL ;
    PORT
      LAYER M4 ;
        RECT  0 54.72 0.084 54.744 ;
    END
  END d[95]
  PIN d[96]
    DIRECTION INPUT ;
    USE SIGNAL ;
    PORT
      LAYER M4 ;
        RECT  0 55.296 0.084 55.32 ;
    END
  END d[96]
  PIN d[97]
    DIRECTION INPUT ;
    USE SIGNAL ;
    PORT
      LAYER M4 ;
        RECT  0 55.824 0.084 55.848 ;
    END
  END d[97]
  PIN d[98]
    DIRECTION INPUT ;
    USE SIGNAL ;
    PORT
      LAYER M4 ;
        RECT  0 56.352 0.084 56.376 ;
    END
  END d[98]
  PIN d[99]
    DIRECTION INPUT ;
    USE SIGNAL ;
    PORT
      LAYER M4 ;
        RECT  0 56.928 0.084 56.952 ;
    END
  END d[99]
  PIN d[9]
    DIRECTION INPUT ;
    USE SIGNAL ;
    PORT
      LAYER M4 ;
        RECT  0 7.392 0.084 7.416 ;
    END
  END d[9]
  PIN q[0]
    DIRECTION OUTPUT ;
    USE SIGNAL ;
    PORT
      LAYER M4 ;
        RECT  21.516 2.4 21.6 2.424 ;
    END
  END q[0]
  PIN q[100]
    DIRECTION OUTPUT ;
    USE SIGNAL ;
    PORT
      LAYER M4 ;
        RECT  21.516 57.456 21.6 57.48 ;
    END
  END q[100]
  PIN q[101]
    DIRECTION OUTPUT ;
    USE SIGNAL ;
    PORT
      LAYER M4 ;
        RECT  21.516 58.032 21.6 58.056 ;
    END
  END q[101]
  PIN q[102]
    DIRECTION OUTPUT ;
    USE SIGNAL ;
    PORT
      LAYER M4 ;
        RECT  21.516 58.56 21.6 58.584 ;
    END
  END q[102]
  PIN q[103]
    DIRECTION OUTPUT ;
    USE SIGNAL ;
    PORT
      LAYER M4 ;
        RECT  21.516 59.136 21.6 59.16 ;
    END
  END q[103]
  PIN q[104]
    DIRECTION OUTPUT ;
    USE SIGNAL ;
    PORT
      LAYER M4 ;
        RECT  21.516 59.664 21.6 59.688 ;
    END
  END q[104]
  PIN q[105]
    DIRECTION OUTPUT ;
    USE SIGNAL ;
    PORT
      LAYER M4 ;
        RECT  21.516 60.24 21.6 60.264 ;
    END
  END q[105]
  PIN q[106]
    DIRECTION OUTPUT ;
    USE SIGNAL ;
    PORT
      LAYER M4 ;
        RECT  21.516 60.768 21.6 60.792 ;
    END
  END q[106]
  PIN q[107]
    DIRECTION OUTPUT ;
    USE SIGNAL ;
    PORT
      LAYER M4 ;
        RECT  21.516 61.344 21.6 61.368 ;
    END
  END q[107]
  PIN q[108]
    DIRECTION OUTPUT ;
    USE SIGNAL ;
    PORT
      LAYER M4 ;
        RECT  21.516 61.872 21.6 61.896 ;
    END
  END q[108]
  PIN q[109]
    DIRECTION OUTPUT ;
    USE SIGNAL ;
    PORT
      LAYER M4 ;
        RECT  21.516 62.448 21.6 62.472 ;
    END
  END q[109]
  PIN q[10]
    DIRECTION OUTPUT ;
    USE SIGNAL ;
    PORT
      LAYER M4 ;
        RECT  21.516 7.92 21.6 7.944 ;
    END
  END q[10]
  PIN q[110]
    DIRECTION OUTPUT ;
    USE SIGNAL ;
    PORT
      LAYER M4 ;
        RECT  21.516 62.976 21.6 63 ;
    END
  END q[110]
  PIN q[111]
    DIRECTION OUTPUT ;
    USE SIGNAL ;
    PORT
      LAYER M4 ;
        RECT  21.516 63.552 21.6 63.576 ;
    END
  END q[111]
  PIN q[112]
    DIRECTION OUTPUT ;
    USE SIGNAL ;
    PORT
      LAYER M4 ;
        RECT  21.516 64.08 21.6 64.104 ;
    END
  END q[112]
  PIN q[113]
    DIRECTION OUTPUT ;
    USE SIGNAL ;
    PORT
      LAYER M4 ;
        RECT  21.516 64.608 21.6 64.632 ;
    END
  END q[113]
  PIN q[114]
    DIRECTION OUTPUT ;
    USE SIGNAL ;
    PORT
      LAYER M4 ;
        RECT  21.516 65.184 21.6 65.208 ;
    END
  END q[114]
  PIN q[115]
    DIRECTION OUTPUT ;
    USE SIGNAL ;
    PORT
      LAYER M4 ;
        RECT  21.516 65.712 21.6 65.736 ;
    END
  END q[115]
  PIN q[116]
    DIRECTION OUTPUT ;
    USE SIGNAL ;
    PORT
      LAYER M4 ;
        RECT  21.516 66.288 21.6 66.312 ;
    END
  END q[116]
  PIN q[117]
    DIRECTION OUTPUT ;
    USE SIGNAL ;
    PORT
      LAYER M4 ;
        RECT  21.516 66.816 21.6 66.84 ;
    END
  END q[117]
  PIN q[118]
    DIRECTION OUTPUT ;
    USE SIGNAL ;
    PORT
      LAYER M4 ;
        RECT  21.516 67.392 21.6 67.416 ;
    END
  END q[118]
  PIN q[119]
    DIRECTION OUTPUT ;
    USE SIGNAL ;
    PORT
      LAYER M4 ;
        RECT  21.516 67.92 21.6 67.944 ;
    END
  END q[119]
  PIN q[11]
    DIRECTION OUTPUT ;
    USE SIGNAL ;
    PORT
      LAYER M4 ;
        RECT  21.516 8.496 21.6 8.52 ;
    END
  END q[11]
  PIN q[120]
    DIRECTION OUTPUT ;
    USE SIGNAL ;
    PORT
      LAYER M4 ;
        RECT  21.516 68.496 21.6 68.52 ;
    END
  END q[120]
  PIN q[121]
    DIRECTION OUTPUT ;
    USE SIGNAL ;
    PORT
      LAYER M4 ;
        RECT  21.516 69.024 21.6 69.048 ;
    END
  END q[121]
  PIN q[122]
    DIRECTION OUTPUT ;
    USE SIGNAL ;
    PORT
      LAYER M4 ;
        RECT  21.516 69.6 21.6 69.624 ;
    END
  END q[122]
  PIN q[123]
    DIRECTION OUTPUT ;
    USE SIGNAL ;
    PORT
      LAYER M4 ;
        RECT  21.516 70.128 21.6 70.152 ;
    END
  END q[123]
  PIN q[124]
    DIRECTION OUTPUT ;
    USE SIGNAL ;
    PORT
      LAYER M4 ;
        RECT  21.516 70.704 21.6 70.728 ;
    END
  END q[124]
  PIN q[125]
    DIRECTION OUTPUT ;
    USE SIGNAL ;
    PORT
      LAYER M4 ;
        RECT  21.516 71.232 21.6 71.256 ;
    END
  END q[125]
  PIN q[126]
    DIRECTION OUTPUT ;
    USE SIGNAL ;
    PORT
      LAYER M4 ;
        RECT  21.516 71.808 21.6 71.832 ;
    END
  END q[126]
  PIN q[127]
    DIRECTION OUTPUT ;
    USE SIGNAL ;
    PORT
      LAYER M4 ;
        RECT  21.516 72.336 21.6 72.36 ;
    END
  END q[127]
  PIN q[128]
    DIRECTION OUTPUT ;
    USE SIGNAL ;
    PORT
      LAYER M4 ;
        RECT  21.516 72.912 21.6 72.936 ;
    END
  END q[128]
  PIN q[129]
    DIRECTION OUTPUT ;
    USE SIGNAL ;
    PORT
      LAYER M4 ;
        RECT  21.516 73.44 21.6 73.464 ;
    END
  END q[129]
  PIN q[12]
    DIRECTION OUTPUT ;
    USE SIGNAL ;
    PORT
      LAYER M4 ;
        RECT  21.516 9.024 21.6 9.048 ;
    END
  END q[12]
  PIN q[130]
    DIRECTION OUTPUT ;
    USE SIGNAL ;
    PORT
      LAYER M4 ;
        RECT  21.516 73.968 21.6 73.992 ;
    END
  END q[130]
  PIN q[131]
    DIRECTION OUTPUT ;
    USE SIGNAL ;
    PORT
      LAYER M4 ;
        RECT  21.516 74.544 21.6 74.568 ;
    END
  END q[131]
  PIN q[132]
    DIRECTION OUTPUT ;
    USE SIGNAL ;
    PORT
      LAYER M4 ;
        RECT  21.516 75.072 21.6 75.096 ;
    END
  END q[132]
  PIN q[133]
    DIRECTION OUTPUT ;
    USE SIGNAL ;
    PORT
      LAYER M4 ;
        RECT  21.516 75.648 21.6 75.672 ;
    END
  END q[133]
  PIN q[134]
    DIRECTION OUTPUT ;
    USE SIGNAL ;
    PORT
      LAYER M4 ;
        RECT  21.516 76.176 21.6 76.2 ;
    END
  END q[134]
  PIN q[135]
    DIRECTION OUTPUT ;
    USE SIGNAL ;
    PORT
      LAYER M4 ;
        RECT  21.516 76.752 21.6 76.776 ;
    END
  END q[135]
  PIN q[136]
    DIRECTION OUTPUT ;
    USE SIGNAL ;
    PORT
      LAYER M4 ;
        RECT  21.516 77.28 21.6 77.304 ;
    END
  END q[136]
  PIN q[137]
    DIRECTION OUTPUT ;
    USE SIGNAL ;
    PORT
      LAYER M4 ;
        RECT  21.516 77.856 21.6 77.88 ;
    END
  END q[137]
  PIN q[138]
    DIRECTION OUTPUT ;
    USE SIGNAL ;
    PORT
      LAYER M4 ;
        RECT  21.516 78.384 21.6 78.408 ;
    END
  END q[138]
  PIN q[139]
    DIRECTION OUTPUT ;
    USE SIGNAL ;
    PORT
      LAYER M4 ;
        RECT  21.516 78.96 21.6 78.984 ;
    END
  END q[139]
  PIN q[13]
    DIRECTION OUTPUT ;
    USE SIGNAL ;
    PORT
      LAYER M4 ;
        RECT  21.516 9.6 21.6 9.624 ;
    END
  END q[13]
  PIN q[140]
    DIRECTION OUTPUT ;
    USE SIGNAL ;
    PORT
      LAYER M4 ;
        RECT  21.516 79.488 21.6 79.512 ;
    END
  END q[140]
  PIN q[141]
    DIRECTION OUTPUT ;
    USE SIGNAL ;
    PORT
      LAYER M4 ;
        RECT  21.516 80.064 21.6 80.088 ;
    END
  END q[141]
  PIN q[142]
    DIRECTION OUTPUT ;
    USE SIGNAL ;
    PORT
      LAYER M4 ;
        RECT  21.516 80.592 21.6 80.616 ;
    END
  END q[142]
  PIN q[143]
    DIRECTION OUTPUT ;
    USE SIGNAL ;
    PORT
      LAYER M4 ;
        RECT  21.516 81.168 21.6 81.192 ;
    END
  END q[143]
  PIN q[144]
    DIRECTION OUTPUT ;
    USE SIGNAL ;
    PORT
      LAYER M4 ;
        RECT  21.516 81.696 21.6 81.72 ;
    END
  END q[144]
  PIN q[145]
    DIRECTION OUTPUT ;
    USE SIGNAL ;
    PORT
      LAYER M4 ;
        RECT  21.516 82.224 21.6 82.248 ;
    END
  END q[145]
  PIN q[146]
    DIRECTION OUTPUT ;
    USE SIGNAL ;
    PORT
      LAYER M4 ;
        RECT  21.516 82.8 21.6 82.824 ;
    END
  END q[146]
  PIN q[147]
    DIRECTION OUTPUT ;
    USE SIGNAL ;
    PORT
      LAYER M4 ;
        RECT  21.516 83.328 21.6 83.352 ;
    END
  END q[147]
  PIN q[148]
    DIRECTION OUTPUT ;
    USE SIGNAL ;
    PORT
      LAYER M4 ;
        RECT  21.516 83.904 21.6 83.928 ;
    END
  END q[148]
  PIN q[149]
    DIRECTION OUTPUT ;
    USE SIGNAL ;
    PORT
      LAYER M4 ;
        RECT  21.516 84.432 21.6 84.456 ;
    END
  END q[149]
  PIN q[14]
    DIRECTION OUTPUT ;
    USE SIGNAL ;
    PORT
      LAYER M4 ;
        RECT  21.516 10.128 21.6 10.152 ;
    END
  END q[14]
  PIN q[150]
    DIRECTION OUTPUT ;
    USE SIGNAL ;
    PORT
      LAYER M4 ;
        RECT  21.516 85.008 21.6 85.032 ;
    END
  END q[150]
  PIN q[151]
    DIRECTION OUTPUT ;
    USE SIGNAL ;
    PORT
      LAYER M4 ;
        RECT  21.516 85.536 21.6 85.56 ;
    END
  END q[151]
  PIN q[152]
    DIRECTION OUTPUT ;
    USE SIGNAL ;
    PORT
      LAYER M4 ;
        RECT  21.516 86.112 21.6 86.136 ;
    END
  END q[152]
  PIN q[153]
    DIRECTION OUTPUT ;
    USE SIGNAL ;
    PORT
      LAYER M4 ;
        RECT  21.516 86.64 21.6 86.664 ;
    END
  END q[153]
  PIN q[154]
    DIRECTION OUTPUT ;
    USE SIGNAL ;
    PORT
      LAYER M4 ;
        RECT  21.516 87.216 21.6 87.24 ;
    END
  END q[154]
  PIN q[155]
    DIRECTION OUTPUT ;
    USE SIGNAL ;
    PORT
      LAYER M4 ;
        RECT  21.516 87.744 21.6 87.768 ;
    END
  END q[155]
  PIN q[156]
    DIRECTION OUTPUT ;
    USE SIGNAL ;
    PORT
      LAYER M4 ;
        RECT  21.516 88.32 21.6 88.344 ;
    END
  END q[156]
  PIN q[157]
    DIRECTION OUTPUT ;
    USE SIGNAL ;
    PORT
      LAYER M4 ;
        RECT  21.516 88.848 21.6 88.872 ;
    END
  END q[157]
  PIN q[158]
    DIRECTION OUTPUT ;
    USE SIGNAL ;
    PORT
      LAYER M4 ;
        RECT  21.516 89.424 21.6 89.448 ;
    END
  END q[158]
  PIN q[159]
    DIRECTION OUTPUT ;
    USE SIGNAL ;
    PORT
      LAYER M4 ;
        RECT  21.516 89.952 21.6 89.976 ;
    END
  END q[159]
  PIN q[15]
    DIRECTION OUTPUT ;
    USE SIGNAL ;
    PORT
      LAYER M4 ;
        RECT  21.516 10.704 21.6 10.728 ;
    END
  END q[15]
  PIN q[160]
    DIRECTION OUTPUT ;
    USE SIGNAL ;
    PORT
      LAYER M4 ;
        RECT  21.516 90.528 21.6 90.552 ;
    END
  END q[160]
  PIN q[161]
    DIRECTION OUTPUT ;
    USE SIGNAL ;
    PORT
      LAYER M4 ;
        RECT  21.516 91.056 21.6 91.08 ;
    END
  END q[161]
  PIN q[162]
    DIRECTION OUTPUT ;
    USE SIGNAL ;
    PORT
      LAYER M4 ;
        RECT  21.516 91.584 21.6 91.608 ;
    END
  END q[162]
  PIN q[163]
    DIRECTION OUTPUT ;
    USE SIGNAL ;
    PORT
      LAYER M4 ;
        RECT  21.516 92.16 21.6 92.184 ;
    END
  END q[163]
  PIN q[164]
    DIRECTION OUTPUT ;
    USE SIGNAL ;
    PORT
      LAYER M4 ;
        RECT  21.516 92.688 21.6 92.712 ;
    END
  END q[164]
  PIN q[165]
    DIRECTION OUTPUT ;
    USE SIGNAL ;
    PORT
      LAYER M4 ;
        RECT  21.516 93.264 21.6 93.288 ;
    END
  END q[165]
  PIN q[166]
    DIRECTION OUTPUT ;
    USE SIGNAL ;
    PORT
      LAYER M4 ;
        RECT  21.516 93.792 21.6 93.816 ;
    END
  END q[166]
  PIN q[167]
    DIRECTION OUTPUT ;
    USE SIGNAL ;
    PORT
      LAYER M4 ;
        RECT  21.516 94.368 21.6 94.392 ;
    END
  END q[167]
  PIN q[168]
    DIRECTION OUTPUT ;
    USE SIGNAL ;
    PORT
      LAYER M4 ;
        RECT  21.516 94.896 21.6 94.92 ;
    END
  END q[168]
  PIN q[169]
    DIRECTION OUTPUT ;
    USE SIGNAL ;
    PORT
      LAYER M4 ;
        RECT  21.516 95.472 21.6 95.496 ;
    END
  END q[169]
  PIN q[16]
    DIRECTION OUTPUT ;
    USE SIGNAL ;
    PORT
      LAYER M4 ;
        RECT  21.516 11.232 21.6 11.256 ;
    END
  END q[16]
  PIN q[170]
    DIRECTION OUTPUT ;
    USE SIGNAL ;
    PORT
      LAYER M4 ;
        RECT  21.516 96 21.6 96.024 ;
    END
  END q[170]
  PIN q[171]
    DIRECTION OUTPUT ;
    USE SIGNAL ;
    PORT
      LAYER M4 ;
        RECT  21.516 96.576 21.6 96.6 ;
    END
  END q[171]
  PIN q[172]
    DIRECTION OUTPUT ;
    USE SIGNAL ;
    PORT
      LAYER M4 ;
        RECT  21.516 97.104 21.6 97.128 ;
    END
  END q[172]
  PIN q[173]
    DIRECTION OUTPUT ;
    USE SIGNAL ;
    PORT
      LAYER M4 ;
        RECT  21.516 97.68 21.6 97.704 ;
    END
  END q[173]
  PIN q[174]
    DIRECTION OUTPUT ;
    USE SIGNAL ;
    PORT
      LAYER M4 ;
        RECT  21.516 98.208 21.6 98.232 ;
    END
  END q[174]
  PIN q[175]
    DIRECTION OUTPUT ;
    USE SIGNAL ;
    PORT
      LAYER M4 ;
        RECT  21.516 98.784 21.6 98.808 ;
    END
  END q[175]
  PIN q[176]
    DIRECTION OUTPUT ;
    USE SIGNAL ;
    PORT
      LAYER M4 ;
        RECT  21.516 99.312 21.6 99.336 ;
    END
  END q[176]
  PIN q[177]
    DIRECTION OUTPUT ;
    USE SIGNAL ;
    PORT
      LAYER M4 ;
        RECT  21.516 99.84 21.6 99.864 ;
    END
  END q[177]
  PIN q[178]
    DIRECTION OUTPUT ;
    USE SIGNAL ;
    PORT
      LAYER M4 ;
        RECT  21.516 100.416 21.6 100.44 ;
    END
  END q[178]
  PIN q[179]
    DIRECTION OUTPUT ;
    USE SIGNAL ;
    PORT
      LAYER M4 ;
        RECT  21.516 100.944 21.6 100.968 ;
    END
  END q[179]
  PIN q[17]
    DIRECTION OUTPUT ;
    USE SIGNAL ;
    PORT
      LAYER M4 ;
        RECT  21.516 11.76 21.6 11.784 ;
    END
  END q[17]
  PIN q[180]
    DIRECTION OUTPUT ;
    USE SIGNAL ;
    PORT
      LAYER M4 ;
        RECT  21.516 101.52 21.6 101.544 ;
    END
  END q[180]
  PIN q[181]
    DIRECTION OUTPUT ;
    USE SIGNAL ;
    PORT
      LAYER M4 ;
        RECT  21.516 102.048 21.6 102.072 ;
    END
  END q[181]
  PIN q[182]
    DIRECTION OUTPUT ;
    USE SIGNAL ;
    PORT
      LAYER M4 ;
        RECT  21.516 102.624 21.6 102.648 ;
    END
  END q[182]
  PIN q[183]
    DIRECTION OUTPUT ;
    USE SIGNAL ;
    PORT
      LAYER M4 ;
        RECT  21.516 103.152 21.6 103.176 ;
    END
  END q[183]
  PIN q[184]
    DIRECTION OUTPUT ;
    USE SIGNAL ;
    PORT
      LAYER M4 ;
        RECT  21.516 103.728 21.6 103.752 ;
    END
  END q[184]
  PIN q[185]
    DIRECTION OUTPUT ;
    USE SIGNAL ;
    PORT
      LAYER M4 ;
        RECT  21.516 104.256 21.6 104.28 ;
    END
  END q[185]
  PIN q[186]
    DIRECTION OUTPUT ;
    USE SIGNAL ;
    PORT
      LAYER M4 ;
        RECT  21.516 104.832 21.6 104.856 ;
    END
  END q[186]
  PIN q[187]
    DIRECTION OUTPUT ;
    USE SIGNAL ;
    PORT
      LAYER M4 ;
        RECT  21.516 105.36 21.6 105.384 ;
    END
  END q[187]
  PIN q[188]
    DIRECTION OUTPUT ;
    USE SIGNAL ;
    PORT
      LAYER M4 ;
        RECT  21.516 105.936 21.6 105.96 ;
    END
  END q[188]
  PIN q[189]
    DIRECTION OUTPUT ;
    USE SIGNAL ;
    PORT
      LAYER M4 ;
        RECT  21.516 106.464 21.6 106.488 ;
    END
  END q[189]
  PIN q[18]
    DIRECTION OUTPUT ;
    USE SIGNAL ;
    PORT
      LAYER M4 ;
        RECT  21.516 12.336 21.6 12.36 ;
    END
  END q[18]
  PIN q[190]
    DIRECTION OUTPUT ;
    USE SIGNAL ;
    PORT
      LAYER M4 ;
        RECT  21.516 107.04 21.6 107.064 ;
    END
  END q[190]
  PIN q[191]
    DIRECTION OUTPUT ;
    USE SIGNAL ;
    PORT
      LAYER M4 ;
        RECT  21.516 107.568 21.6 107.592 ;
    END
  END q[191]
  PIN q[192]
    DIRECTION OUTPUT ;
    USE SIGNAL ;
    PORT
      LAYER M4 ;
        RECT  21.516 108.144 21.6 108.168 ;
    END
  END q[192]
  PIN q[193]
    DIRECTION OUTPUT ;
    USE SIGNAL ;
    PORT
      LAYER M4 ;
        RECT  21.516 108.672 21.6 108.696 ;
    END
  END q[193]
  PIN q[194]
    DIRECTION OUTPUT ;
    USE SIGNAL ;
    PORT
      LAYER M4 ;
        RECT  21.516 109.2 21.6 109.224 ;
    END
  END q[194]
  PIN q[195]
    DIRECTION OUTPUT ;
    USE SIGNAL ;
    PORT
      LAYER M4 ;
        RECT  21.516 109.776 21.6 109.8 ;
    END
  END q[195]
  PIN q[196]
    DIRECTION OUTPUT ;
    USE SIGNAL ;
    PORT
      LAYER M4 ;
        RECT  21.516 110.304 21.6 110.328 ;
    END
  END q[196]
  PIN q[197]
    DIRECTION OUTPUT ;
    USE SIGNAL ;
    PORT
      LAYER M4 ;
        RECT  21.516 110.88 21.6 110.904 ;
    END
  END q[197]
  PIN q[198]
    DIRECTION OUTPUT ;
    USE SIGNAL ;
    PORT
      LAYER M4 ;
        RECT  21.516 111.408 21.6 111.432 ;
    END
  END q[198]
  PIN q[199]
    DIRECTION OUTPUT ;
    USE SIGNAL ;
    PORT
      LAYER M4 ;
        RECT  21.516 111.984 21.6 112.008 ;
    END
  END q[199]
  PIN q[19]
    DIRECTION OUTPUT ;
    USE SIGNAL ;
    PORT
      LAYER M4 ;
        RECT  21.516 12.864 21.6 12.888 ;
    END
  END q[19]
  PIN q[1]
    DIRECTION OUTPUT ;
    USE SIGNAL ;
    PORT
      LAYER M4 ;
        RECT  21.516 2.976 21.6 3 ;
    END
  END q[1]
  PIN q[200]
    DIRECTION OUTPUT ;
    USE SIGNAL ;
    PORT
      LAYER M4 ;
        RECT  21.516 112.512 21.6 112.536 ;
    END
  END q[200]
  PIN q[201]
    DIRECTION OUTPUT ;
    USE SIGNAL ;
    PORT
      LAYER M4 ;
        RECT  21.516 113.088 21.6 113.112 ;
    END
  END q[201]
  PIN q[202]
    DIRECTION OUTPUT ;
    USE SIGNAL ;
    PORT
      LAYER M4 ;
        RECT  21.516 113.616 21.6 113.64 ;
    END
  END q[202]
  PIN q[203]
    DIRECTION OUTPUT ;
    USE SIGNAL ;
    PORT
      LAYER M4 ;
        RECT  21.516 114.192 21.6 114.216 ;
    END
  END q[203]
  PIN q[204]
    DIRECTION OUTPUT ;
    USE SIGNAL ;
    PORT
      LAYER M4 ;
        RECT  21.516 114.72 21.6 114.744 ;
    END
  END q[204]
  PIN q[205]
    DIRECTION OUTPUT ;
    USE SIGNAL ;
    PORT
      LAYER M4 ;
        RECT  21.516 115.296 21.6 115.32 ;
    END
  END q[205]
  PIN q[206]
    DIRECTION OUTPUT ;
    USE SIGNAL ;
    PORT
      LAYER M4 ;
        RECT  21.516 115.824 21.6 115.848 ;
    END
  END q[206]
  PIN q[207]
    DIRECTION OUTPUT ;
    USE SIGNAL ;
    PORT
      LAYER M4 ;
        RECT  21.516 116.4 21.6 116.424 ;
    END
  END q[207]
  PIN q[208]
    DIRECTION OUTPUT ;
    USE SIGNAL ;
    PORT
      LAYER M4 ;
        RECT  21.516 116.928 21.6 116.952 ;
    END
  END q[208]
  PIN q[209]
    DIRECTION OUTPUT ;
    USE SIGNAL ;
    PORT
      LAYER M4 ;
        RECT  21.516 117.456 21.6 117.48 ;
    END
  END q[209]
  PIN q[20]
    DIRECTION OUTPUT ;
    USE SIGNAL ;
    PORT
      LAYER M4 ;
        RECT  21.516 13.44 21.6 13.464 ;
    END
  END q[20]
  PIN q[210]
    DIRECTION OUTPUT ;
    USE SIGNAL ;
    PORT
      LAYER M4 ;
        RECT  21.516 118.032 21.6 118.056 ;
    END
  END q[210]
  PIN q[211]
    DIRECTION OUTPUT ;
    USE SIGNAL ;
    PORT
      LAYER M4 ;
        RECT  21.516 118.56 21.6 118.584 ;
    END
  END q[211]
  PIN q[212]
    DIRECTION OUTPUT ;
    USE SIGNAL ;
    PORT
      LAYER M4 ;
        RECT  21.516 119.136 21.6 119.16 ;
    END
  END q[212]
  PIN q[213]
    DIRECTION OUTPUT ;
    USE SIGNAL ;
    PORT
      LAYER M4 ;
        RECT  21.516 119.664 21.6 119.688 ;
    END
  END q[213]
  PIN q[214]
    DIRECTION OUTPUT ;
    USE SIGNAL ;
    PORT
      LAYER M4 ;
        RECT  21.516 120.24 21.6 120.264 ;
    END
  END q[214]
  PIN q[215]
    DIRECTION OUTPUT ;
    USE SIGNAL ;
    PORT
      LAYER M4 ;
        RECT  21.516 120.768 21.6 120.792 ;
    END
  END q[215]
  PIN q[216]
    DIRECTION OUTPUT ;
    USE SIGNAL ;
    PORT
      LAYER M4 ;
        RECT  21.516 121.344 21.6 121.368 ;
    END
  END q[216]
  PIN q[217]
    DIRECTION OUTPUT ;
    USE SIGNAL ;
    PORT
      LAYER M4 ;
        RECT  21.516 121.872 21.6 121.896 ;
    END
  END q[217]
  PIN q[218]
    DIRECTION OUTPUT ;
    USE SIGNAL ;
    PORT
      LAYER M4 ;
        RECT  21.516 122.448 21.6 122.472 ;
    END
  END q[218]
  PIN q[219]
    DIRECTION OUTPUT ;
    USE SIGNAL ;
    PORT
      LAYER M4 ;
        RECT  21.516 122.976 21.6 123 ;
    END
  END q[219]
  PIN q[21]
    DIRECTION OUTPUT ;
    USE SIGNAL ;
    PORT
      LAYER M4 ;
        RECT  21.516 13.968 21.6 13.992 ;
    END
  END q[21]
  PIN q[220]
    DIRECTION OUTPUT ;
    USE SIGNAL ;
    PORT
      LAYER M4 ;
        RECT  21.516 123.552 21.6 123.576 ;
    END
  END q[220]
  PIN q[221]
    DIRECTION OUTPUT ;
    USE SIGNAL ;
    PORT
      LAYER M4 ;
        RECT  21.516 124.08 21.6 124.104 ;
    END
  END q[221]
  PIN q[222]
    DIRECTION OUTPUT ;
    USE SIGNAL ;
    PORT
      LAYER M4 ;
        RECT  21.516 124.656 21.6 124.68 ;
    END
  END q[222]
  PIN q[223]
    DIRECTION OUTPUT ;
    USE SIGNAL ;
    PORT
      LAYER M4 ;
        RECT  21.516 125.184 21.6 125.208 ;
    END
  END q[223]
  PIN q[224]
    DIRECTION OUTPUT ;
    USE SIGNAL ;
    PORT
      LAYER M4 ;
        RECT  21.516 125.76 21.6 125.784 ;
    END
  END q[224]
  PIN q[225]
    DIRECTION OUTPUT ;
    USE SIGNAL ;
    PORT
      LAYER M4 ;
        RECT  21.516 126.288 21.6 126.312 ;
    END
  END q[225]
  PIN q[226]
    DIRECTION OUTPUT ;
    USE SIGNAL ;
    PORT
      LAYER M4 ;
        RECT  21.516 126.816 21.6 126.84 ;
    END
  END q[226]
  PIN q[227]
    DIRECTION OUTPUT ;
    USE SIGNAL ;
    PORT
      LAYER M4 ;
        RECT  21.516 127.392 21.6 127.416 ;
    END
  END q[227]
  PIN q[228]
    DIRECTION OUTPUT ;
    USE SIGNAL ;
    PORT
      LAYER M4 ;
        RECT  21.516 127.92 21.6 127.944 ;
    END
  END q[228]
  PIN q[229]
    DIRECTION OUTPUT ;
    USE SIGNAL ;
    PORT
      LAYER M4 ;
        RECT  21.516 128.496 21.6 128.52 ;
    END
  END q[229]
  PIN q[22]
    DIRECTION OUTPUT ;
    USE SIGNAL ;
    PORT
      LAYER M4 ;
        RECT  21.516 14.544 21.6 14.568 ;
    END
  END q[22]
  PIN q[230]
    DIRECTION OUTPUT ;
    USE SIGNAL ;
    PORT
      LAYER M4 ;
        RECT  21.516 129.024 21.6 129.048 ;
    END
  END q[230]
  PIN q[231]
    DIRECTION OUTPUT ;
    USE SIGNAL ;
    PORT
      LAYER M4 ;
        RECT  21.516 129.6 21.6 129.624 ;
    END
  END q[231]
  PIN q[232]
    DIRECTION OUTPUT ;
    USE SIGNAL ;
    PORT
      LAYER M4 ;
        RECT  21.516 130.128 21.6 130.152 ;
    END
  END q[232]
  PIN q[233]
    DIRECTION OUTPUT ;
    USE SIGNAL ;
    PORT
      LAYER M4 ;
        RECT  21.516 130.704 21.6 130.728 ;
    END
  END q[233]
  PIN q[234]
    DIRECTION OUTPUT ;
    USE SIGNAL ;
    PORT
      LAYER M4 ;
        RECT  21.516 131.232 21.6 131.256 ;
    END
  END q[234]
  PIN q[235]
    DIRECTION OUTPUT ;
    USE SIGNAL ;
    PORT
      LAYER M4 ;
        RECT  21.516 131.808 21.6 131.832 ;
    END
  END q[235]
  PIN q[236]
    DIRECTION OUTPUT ;
    USE SIGNAL ;
    PORT
      LAYER M4 ;
        RECT  21.516 132.336 21.6 132.36 ;
    END
  END q[236]
  PIN q[237]
    DIRECTION OUTPUT ;
    USE SIGNAL ;
    PORT
      LAYER M4 ;
        RECT  21.516 132.912 21.6 132.936 ;
    END
  END q[237]
  PIN q[238]
    DIRECTION OUTPUT ;
    USE SIGNAL ;
    PORT
      LAYER M4 ;
        RECT  21.516 133.44 21.6 133.464 ;
    END
  END q[238]
  PIN q[239]
    DIRECTION OUTPUT ;
    USE SIGNAL ;
    PORT
      LAYER M4 ;
        RECT  21.516 134.016 21.6 134.04 ;
    END
  END q[239]
  PIN q[23]
    DIRECTION OUTPUT ;
    USE SIGNAL ;
    PORT
      LAYER M4 ;
        RECT  21.516 15.072 21.6 15.096 ;
    END
  END q[23]
  PIN q[240]
    DIRECTION OUTPUT ;
    USE SIGNAL ;
    PORT
      LAYER M4 ;
        RECT  21.516 134.544 21.6 134.568 ;
    END
  END q[240]
  PIN q[241]
    DIRECTION OUTPUT ;
    USE SIGNAL ;
    PORT
      LAYER M4 ;
        RECT  21.516 135.072 21.6 135.096 ;
    END
  END q[241]
  PIN q[242]
    DIRECTION OUTPUT ;
    USE SIGNAL ;
    PORT
      LAYER M4 ;
        RECT  21.516 135.648 21.6 135.672 ;
    END
  END q[242]
  PIN q[243]
    DIRECTION OUTPUT ;
    USE SIGNAL ;
    PORT
      LAYER M4 ;
        RECT  21.516 136.176 21.6 136.2 ;
    END
  END q[243]
  PIN q[244]
    DIRECTION OUTPUT ;
    USE SIGNAL ;
    PORT
      LAYER M4 ;
        RECT  21.516 136.752 21.6 136.776 ;
    END
  END q[244]
  PIN q[245]
    DIRECTION OUTPUT ;
    USE SIGNAL ;
    PORT
      LAYER M4 ;
        RECT  21.516 137.28 21.6 137.304 ;
    END
  END q[245]
  PIN q[246]
    DIRECTION OUTPUT ;
    USE SIGNAL ;
    PORT
      LAYER M4 ;
        RECT  21.516 137.856 21.6 137.88 ;
    END
  END q[246]
  PIN q[247]
    DIRECTION OUTPUT ;
    USE SIGNAL ;
    PORT
      LAYER M4 ;
        RECT  21.516 138.384 21.6 138.408 ;
    END
  END q[247]
  PIN q[248]
    DIRECTION OUTPUT ;
    USE SIGNAL ;
    PORT
      LAYER M4 ;
        RECT  21.516 138.96 21.6 138.984 ;
    END
  END q[248]
  PIN q[249]
    DIRECTION OUTPUT ;
    USE SIGNAL ;
    PORT
      LAYER M4 ;
        RECT  21.516 139.488 21.6 139.512 ;
    END
  END q[249]
  PIN q[24]
    DIRECTION OUTPUT ;
    USE SIGNAL ;
    PORT
      LAYER M4 ;
        RECT  21.516 15.648 21.6 15.672 ;
    END
  END q[24]
  PIN q[250]
    DIRECTION OUTPUT ;
    USE SIGNAL ;
    PORT
      LAYER M4 ;
        RECT  21.516 140.064 21.6 140.088 ;
    END
  END q[250]
  PIN q[251]
    DIRECTION OUTPUT ;
    USE SIGNAL ;
    PORT
      LAYER M4 ;
        RECT  21.516 140.592 21.6 140.616 ;
    END
  END q[251]
  PIN q[252]
    DIRECTION OUTPUT ;
    USE SIGNAL ;
    PORT
      LAYER M4 ;
        RECT  21.516 141.168 21.6 141.192 ;
    END
  END q[252]
  PIN q[253]
    DIRECTION OUTPUT ;
    USE SIGNAL ;
    PORT
      LAYER M4 ;
        RECT  21.516 141.696 21.6 141.72 ;
    END
  END q[253]
  PIN q[254]
    DIRECTION OUTPUT ;
    USE SIGNAL ;
    PORT
      LAYER M4 ;
        RECT  21.516 142.272 21.6 142.296 ;
    END
  END q[254]
  PIN q[255]
    DIRECTION OUTPUT ;
    USE SIGNAL ;
    PORT
      LAYER M4 ;
        RECT  21.516 142.8 21.6 142.824 ;
    END
  END q[255]
  PIN q[256]
    DIRECTION OUTPUT ;
    USE SIGNAL ;
    PORT
      LAYER M4 ;
        RECT  21.516 143.376 21.6 143.4 ;
    END
  END q[256]
  PIN q[25]
    DIRECTION OUTPUT ;
    USE SIGNAL ;
    PORT
      LAYER M4 ;
        RECT  21.516 16.176 21.6 16.2 ;
    END
  END q[25]
  PIN q[26]
    DIRECTION OUTPUT ;
    USE SIGNAL ;
    PORT
      LAYER M4 ;
        RECT  21.516 16.752 21.6 16.776 ;
    END
  END q[26]
  PIN q[27]
    DIRECTION OUTPUT ;
    USE SIGNAL ;
    PORT
      LAYER M4 ;
        RECT  21.516 17.28 21.6 17.304 ;
    END
  END q[27]
  PIN q[28]
    DIRECTION OUTPUT ;
    USE SIGNAL ;
    PORT
      LAYER M4 ;
        RECT  21.516 17.856 21.6 17.88 ;
    END
  END q[28]
  PIN q[29]
    DIRECTION OUTPUT ;
    USE SIGNAL ;
    PORT
      LAYER M4 ;
        RECT  21.516 18.384 21.6 18.408 ;
    END
  END q[29]
  PIN q[2]
    DIRECTION OUTPUT ;
    USE SIGNAL ;
    PORT
      LAYER M4 ;
        RECT  21.516 3.504 21.6 3.528 ;
    END
  END q[2]
  PIN q[30]
    DIRECTION OUTPUT ;
    USE SIGNAL ;
    PORT
      LAYER M4 ;
        RECT  21.516 18.96 21.6 18.984 ;
    END
  END q[30]
  PIN q[31]
    DIRECTION OUTPUT ;
    USE SIGNAL ;
    PORT
      LAYER M4 ;
        RECT  21.516 19.488 21.6 19.512 ;
    END
  END q[31]
  PIN q[32]
    DIRECTION OUTPUT ;
    USE SIGNAL ;
    PORT
      LAYER M4 ;
        RECT  21.516 20.016 21.6 20.04 ;
    END
  END q[32]
  PIN q[33]
    DIRECTION OUTPUT ;
    USE SIGNAL ;
    PORT
      LAYER M4 ;
        RECT  21.516 20.592 21.6 20.616 ;
    END
  END q[33]
  PIN q[34]
    DIRECTION OUTPUT ;
    USE SIGNAL ;
    PORT
      LAYER M4 ;
        RECT  21.516 21.12 21.6 21.144 ;
    END
  END q[34]
  PIN q[35]
    DIRECTION OUTPUT ;
    USE SIGNAL ;
    PORT
      LAYER M4 ;
        RECT  21.516 21.696 21.6 21.72 ;
    END
  END q[35]
  PIN q[36]
    DIRECTION OUTPUT ;
    USE SIGNAL ;
    PORT
      LAYER M4 ;
        RECT  21.516 22.224 21.6 22.248 ;
    END
  END q[36]
  PIN q[37]
    DIRECTION OUTPUT ;
    USE SIGNAL ;
    PORT
      LAYER M4 ;
        RECT  21.516 22.8 21.6 22.824 ;
    END
  END q[37]
  PIN q[38]
    DIRECTION OUTPUT ;
    USE SIGNAL ;
    PORT
      LAYER M4 ;
        RECT  21.516 23.328 21.6 23.352 ;
    END
  END q[38]
  PIN q[39]
    DIRECTION OUTPUT ;
    USE SIGNAL ;
    PORT
      LAYER M4 ;
        RECT  21.516 23.904 21.6 23.928 ;
    END
  END q[39]
  PIN q[3]
    DIRECTION OUTPUT ;
    USE SIGNAL ;
    PORT
      LAYER M4 ;
        RECT  21.516 4.08 21.6 4.104 ;
    END
  END q[3]
  PIN q[40]
    DIRECTION OUTPUT ;
    USE SIGNAL ;
    PORT
      LAYER M4 ;
        RECT  21.516 24.432 21.6 24.456 ;
    END
  END q[40]
  PIN q[41]
    DIRECTION OUTPUT ;
    USE SIGNAL ;
    PORT
      LAYER M4 ;
        RECT  21.516 25.008 21.6 25.032 ;
    END
  END q[41]
  PIN q[42]
    DIRECTION OUTPUT ;
    USE SIGNAL ;
    PORT
      LAYER M4 ;
        RECT  21.516 25.536 21.6 25.56 ;
    END
  END q[42]
  PIN q[43]
    DIRECTION OUTPUT ;
    USE SIGNAL ;
    PORT
      LAYER M4 ;
        RECT  21.516 26.112 21.6 26.136 ;
    END
  END q[43]
  PIN q[44]
    DIRECTION OUTPUT ;
    USE SIGNAL ;
    PORT
      LAYER M4 ;
        RECT  21.516 26.64 21.6 26.664 ;
    END
  END q[44]
  PIN q[45]
    DIRECTION OUTPUT ;
    USE SIGNAL ;
    PORT
      LAYER M4 ;
        RECT  21.516 27.216 21.6 27.24 ;
    END
  END q[45]
  PIN q[46]
    DIRECTION OUTPUT ;
    USE SIGNAL ;
    PORT
      LAYER M4 ;
        RECT  21.516 27.744 21.6 27.768 ;
    END
  END q[46]
  PIN q[47]
    DIRECTION OUTPUT ;
    USE SIGNAL ;
    PORT
      LAYER M4 ;
        RECT  21.516 28.32 21.6 28.344 ;
    END
  END q[47]
  PIN q[48]
    DIRECTION OUTPUT ;
    USE SIGNAL ;
    PORT
      LAYER M4 ;
        RECT  21.516 28.848 21.6 28.872 ;
    END
  END q[48]
  PIN q[49]
    DIRECTION OUTPUT ;
    USE SIGNAL ;
    PORT
      LAYER M4 ;
        RECT  21.516 29.376 21.6 29.4 ;
    END
  END q[49]
  PIN q[4]
    DIRECTION OUTPUT ;
    USE SIGNAL ;
    PORT
      LAYER M4 ;
        RECT  21.516 4.608 21.6 4.632 ;
    END
  END q[4]
  PIN q[50]
    DIRECTION OUTPUT ;
    USE SIGNAL ;
    PORT
      LAYER M4 ;
        RECT  21.516 29.952 21.6 29.976 ;
    END
  END q[50]
  PIN q[51]
    DIRECTION OUTPUT ;
    USE SIGNAL ;
    PORT
      LAYER M4 ;
        RECT  21.516 30.48 21.6 30.504 ;
    END
  END q[51]
  PIN q[52]
    DIRECTION OUTPUT ;
    USE SIGNAL ;
    PORT
      LAYER M4 ;
        RECT  21.516 31.056 21.6 31.08 ;
    END
  END q[52]
  PIN q[53]
    DIRECTION OUTPUT ;
    USE SIGNAL ;
    PORT
      LAYER M4 ;
        RECT  21.516 31.584 21.6 31.608 ;
    END
  END q[53]
  PIN q[54]
    DIRECTION OUTPUT ;
    USE SIGNAL ;
    PORT
      LAYER M4 ;
        RECT  21.516 32.16 21.6 32.184 ;
    END
  END q[54]
  PIN q[55]
    DIRECTION OUTPUT ;
    USE SIGNAL ;
    PORT
      LAYER M4 ;
        RECT  21.516 32.688 21.6 32.712 ;
    END
  END q[55]
  PIN q[56]
    DIRECTION OUTPUT ;
    USE SIGNAL ;
    PORT
      LAYER M4 ;
        RECT  21.516 33.264 21.6 33.288 ;
    END
  END q[56]
  PIN q[57]
    DIRECTION OUTPUT ;
    USE SIGNAL ;
    PORT
      LAYER M4 ;
        RECT  21.516 33.792 21.6 33.816 ;
    END
  END q[57]
  PIN q[58]
    DIRECTION OUTPUT ;
    USE SIGNAL ;
    PORT
      LAYER M4 ;
        RECT  21.516 34.368 21.6 34.392 ;
    END
  END q[58]
  PIN q[59]
    DIRECTION OUTPUT ;
    USE SIGNAL ;
    PORT
      LAYER M4 ;
        RECT  21.516 34.896 21.6 34.92 ;
    END
  END q[59]
  PIN q[5]
    DIRECTION OUTPUT ;
    USE SIGNAL ;
    PORT
      LAYER M4 ;
        RECT  21.516 5.184 21.6 5.208 ;
    END
  END q[5]
  PIN q[60]
    DIRECTION OUTPUT ;
    USE SIGNAL ;
    PORT
      LAYER M4 ;
        RECT  21.516 35.472 21.6 35.496 ;
    END
  END q[60]
  PIN q[61]
    DIRECTION OUTPUT ;
    USE SIGNAL ;
    PORT
      LAYER M4 ;
        RECT  21.516 36 21.6 36.024 ;
    END
  END q[61]
  PIN q[62]
    DIRECTION OUTPUT ;
    USE SIGNAL ;
    PORT
      LAYER M4 ;
        RECT  21.516 36.576 21.6 36.6 ;
    END
  END q[62]
  PIN q[63]
    DIRECTION OUTPUT ;
    USE SIGNAL ;
    PORT
      LAYER M4 ;
        RECT  21.516 37.104 21.6 37.128 ;
    END
  END q[63]
  PIN q[64]
    DIRECTION OUTPUT ;
    USE SIGNAL ;
    PORT
      LAYER M4 ;
        RECT  21.516 37.68 21.6 37.704 ;
    END
  END q[64]
  PIN q[65]
    DIRECTION OUTPUT ;
    USE SIGNAL ;
    PORT
      LAYER M4 ;
        RECT  21.516 38.208 21.6 38.232 ;
    END
  END q[65]
  PIN q[66]
    DIRECTION OUTPUT ;
    USE SIGNAL ;
    PORT
      LAYER M4 ;
        RECT  21.516 38.736 21.6 38.76 ;
    END
  END q[66]
  PIN q[67]
    DIRECTION OUTPUT ;
    USE SIGNAL ;
    PORT
      LAYER M4 ;
        RECT  21.516 39.312 21.6 39.336 ;
    END
  END q[67]
  PIN q[68]
    DIRECTION OUTPUT ;
    USE SIGNAL ;
    PORT
      LAYER M4 ;
        RECT  21.516 39.84 21.6 39.864 ;
    END
  END q[68]
  PIN q[69]
    DIRECTION OUTPUT ;
    USE SIGNAL ;
    PORT
      LAYER M4 ;
        RECT  21.516 40.416 21.6 40.44 ;
    END
  END q[69]
  PIN q[6]
    DIRECTION OUTPUT ;
    USE SIGNAL ;
    PORT
      LAYER M4 ;
        RECT  21.516 5.712 21.6 5.736 ;
    END
  END q[6]
  PIN q[70]
    DIRECTION OUTPUT ;
    USE SIGNAL ;
    PORT
      LAYER M4 ;
        RECT  21.516 40.944 21.6 40.968 ;
    END
  END q[70]
  PIN q[71]
    DIRECTION OUTPUT ;
    USE SIGNAL ;
    PORT
      LAYER M4 ;
        RECT  21.516 41.52 21.6 41.544 ;
    END
  END q[71]
  PIN q[72]
    DIRECTION OUTPUT ;
    USE SIGNAL ;
    PORT
      LAYER M4 ;
        RECT  21.516 42.048 21.6 42.072 ;
    END
  END q[72]
  PIN q[73]
    DIRECTION OUTPUT ;
    USE SIGNAL ;
    PORT
      LAYER M4 ;
        RECT  21.516 42.624 21.6 42.648 ;
    END
  END q[73]
  PIN q[74]
    DIRECTION OUTPUT ;
    USE SIGNAL ;
    PORT
      LAYER M4 ;
        RECT  21.516 43.152 21.6 43.176 ;
    END
  END q[74]
  PIN q[75]
    DIRECTION OUTPUT ;
    USE SIGNAL ;
    PORT
      LAYER M4 ;
        RECT  21.516 43.728 21.6 43.752 ;
    END
  END q[75]
  PIN q[76]
    DIRECTION OUTPUT ;
    USE SIGNAL ;
    PORT
      LAYER M4 ;
        RECT  21.516 44.256 21.6 44.28 ;
    END
  END q[76]
  PIN q[77]
    DIRECTION OUTPUT ;
    USE SIGNAL ;
    PORT
      LAYER M4 ;
        RECT  21.516 44.832 21.6 44.856 ;
    END
  END q[77]
  PIN q[78]
    DIRECTION OUTPUT ;
    USE SIGNAL ;
    PORT
      LAYER M4 ;
        RECT  21.516 45.36 21.6 45.384 ;
    END
  END q[78]
  PIN q[79]
    DIRECTION OUTPUT ;
    USE SIGNAL ;
    PORT
      LAYER M4 ;
        RECT  21.516 45.936 21.6 45.96 ;
    END
  END q[79]
  PIN q[7]
    DIRECTION OUTPUT ;
    USE SIGNAL ;
    PORT
      LAYER M4 ;
        RECT  21.516 6.288 21.6 6.312 ;
    END
  END q[7]
  PIN q[80]
    DIRECTION OUTPUT ;
    USE SIGNAL ;
    PORT
      LAYER M4 ;
        RECT  21.516 46.464 21.6 46.488 ;
    END
  END q[80]
  PIN q[81]
    DIRECTION OUTPUT ;
    USE SIGNAL ;
    PORT
      LAYER M4 ;
        RECT  21.516 46.992 21.6 47.016 ;
    END
  END q[81]
  PIN q[82]
    DIRECTION OUTPUT ;
    USE SIGNAL ;
    PORT
      LAYER M4 ;
        RECT  21.516 47.568 21.6 47.592 ;
    END
  END q[82]
  PIN q[83]
    DIRECTION OUTPUT ;
    USE SIGNAL ;
    PORT
      LAYER M4 ;
        RECT  21.516 48.096 21.6 48.12 ;
    END
  END q[83]
  PIN q[84]
    DIRECTION OUTPUT ;
    USE SIGNAL ;
    PORT
      LAYER M4 ;
        RECT  21.516 48.672 21.6 48.696 ;
    END
  END q[84]
  PIN q[85]
    DIRECTION OUTPUT ;
    USE SIGNAL ;
    PORT
      LAYER M4 ;
        RECT  21.516 49.2 21.6 49.224 ;
    END
  END q[85]
  PIN q[86]
    DIRECTION OUTPUT ;
    USE SIGNAL ;
    PORT
      LAYER M4 ;
        RECT  21.516 49.776 21.6 49.8 ;
    END
  END q[86]
  PIN q[87]
    DIRECTION OUTPUT ;
    USE SIGNAL ;
    PORT
      LAYER M4 ;
        RECT  21.516 50.304 21.6 50.328 ;
    END
  END q[87]
  PIN q[88]
    DIRECTION OUTPUT ;
    USE SIGNAL ;
    PORT
      LAYER M4 ;
        RECT  21.516 50.88 21.6 50.904 ;
    END
  END q[88]
  PIN q[89]
    DIRECTION OUTPUT ;
    USE SIGNAL ;
    PORT
      LAYER M4 ;
        RECT  21.516 51.408 21.6 51.432 ;
    END
  END q[89]
  PIN q[8]
    DIRECTION OUTPUT ;
    USE SIGNAL ;
    PORT
      LAYER M4 ;
        RECT  21.516 6.816 21.6 6.84 ;
    END
  END q[8]
  PIN q[90]
    DIRECTION OUTPUT ;
    USE SIGNAL ;
    PORT
      LAYER M4 ;
        RECT  21.516 51.984 21.6 52.008 ;
    END
  END q[90]
  PIN q[91]
    DIRECTION OUTPUT ;
    USE SIGNAL ;
    PORT
      LAYER M4 ;
        RECT  21.516 52.512 21.6 52.536 ;
    END
  END q[91]
  PIN q[92]
    DIRECTION OUTPUT ;
    USE SIGNAL ;
    PORT
      LAYER M4 ;
        RECT  21.516 53.088 21.6 53.112 ;
    END
  END q[92]
  PIN q[93]
    DIRECTION OUTPUT ;
    USE SIGNAL ;
    PORT
      LAYER M4 ;
        RECT  21.516 53.616 21.6 53.64 ;
    END
  END q[93]
  PIN q[94]
    DIRECTION OUTPUT ;
    USE SIGNAL ;
    PORT
      LAYER M4 ;
        RECT  21.516 54.192 21.6 54.216 ;
    END
  END q[94]
  PIN q[95]
    DIRECTION OUTPUT ;
    USE SIGNAL ;
    PORT
      LAYER M4 ;
        RECT  21.516 54.72 21.6 54.744 ;
    END
  END q[95]
  PIN q[96]
    DIRECTION OUTPUT ;
    USE SIGNAL ;
    PORT
      LAYER M4 ;
        RECT  21.516 55.296 21.6 55.32 ;
    END
  END q[96]
  PIN q[97]
    DIRECTION OUTPUT ;
    USE SIGNAL ;
    PORT
      LAYER M4 ;
        RECT  21.516 55.824 21.6 55.848 ;
    END
  END q[97]
  PIN q[98]
    DIRECTION OUTPUT ;
    USE SIGNAL ;
    PORT
      LAYER M4 ;
        RECT  21.516 56.352 21.6 56.376 ;
    END
  END q[98]
  PIN q[99]
    DIRECTION OUTPUT ;
    USE SIGNAL ;
    PORT
      LAYER M4 ;
        RECT  21.516 56.928 21.6 56.952 ;
    END
  END q[99]
  PIN q[9]
    DIRECTION OUTPUT ;
    USE SIGNAL ;
    PORT
      LAYER M4 ;
        RECT  21.516 7.392 21.6 7.416 ;
    END
  END q[9]
  PIN VDD
    DIRECTION INOUT ;
    USE POWER ;
    PORT
      LAYER M5 ;
        RECT  18.792 2.151 18.912 144.729 ;
        RECT  16.092 2.151 16.212 144.729 ;
        RECT  13.392 2.151 13.512 144.729 ;
        RECT  10.692 2.151 10.812 144.729 ;
        RECT  7.992 2.151 8.112 144.729 ;
        RECT  5.292 2.151 5.412 144.729 ;
        RECT  2.592 2.151 2.712 144.729 ;
    END
  END VDD
  PIN VSS
    DIRECTION INOUT ;
    USE GROUND ;
    PORT
      LAYER M5 ;
        RECT  18.6 2.137 18.72 144.743 ;
        RECT  15.9 2.137 16.02 144.743 ;
        RECT  13.2 2.137 13.32 144.743 ;
        RECT  10.5 2.137 10.62 144.743 ;
        RECT  7.8 2.137 7.92 144.743 ;
        RECT  5.1 2.137 5.22 144.743 ;
        RECT  2.4 2.137 2.52 144.743 ;
    END
  END VSS
  # OT_OBS_CLOSED layer=M5 d_um=1.536 added=43
  OBS
    LAYER RVTN ;
     RECT  2.16 2.16 19.44 2.295 ;
     RECT  2.16 2.565 19.44 2.835 ;
     RECT  2.16 3.105 19.44 3.375 ;
     RECT  2.16 3.645 19.44 3.915 ;
     RECT  2.16 4.185 19.44 4.455 ;
     RECT  2.16 4.725 19.44 4.995 ;
     RECT  2.16 5.265 19.44 5.535 ;
     RECT  2.16 5.805 19.44 6.075 ;
     RECT  2.16 6.345 19.44 6.615 ;
     RECT  2.16 6.885 19.44 7.155 ;
     RECT  2.16 7.425 19.44 7.695 ;
     RECT  2.16 7.965 19.44 8.235 ;
     RECT  2.16 8.505 19.44 8.775 ;
     RECT  2.16 9.045 19.44 9.315 ;
     RECT  2.16 9.585 19.44 9.855 ;
     RECT  2.16 10.125 19.44 10.395 ;
     RECT  2.16 10.665 19.44 10.935 ;
     RECT  2.16 11.205 19.44 11.475 ;
     RECT  2.16 11.745 19.44 12.015 ;
     RECT  2.16 12.285 19.44 12.555 ;
     RECT  2.16 12.825 19.44 13.095 ;
     RECT  2.16 13.365 19.44 13.635 ;
     RECT  2.16 13.905 19.44 14.175 ;
     RECT  2.16 14.445 19.44 14.715 ;
     RECT  2.16 14.985 19.44 15.255 ;
     RECT  2.16 15.525 19.44 15.795 ;
     RECT  2.16 16.065 19.44 16.335 ;
     RECT  2.16 16.605 19.44 16.875 ;
     RECT  2.16 17.145 19.44 17.415 ;
     RECT  2.16 17.685 19.44 17.955 ;
     RECT  2.16 18.225 19.44 18.495 ;
     RECT  2.16 18.765 19.44 19.035 ;
     RECT  2.16 19.305 19.44 19.575 ;
     RECT  2.16 19.845 19.44 20.115 ;
     RECT  2.16 20.385 19.44 20.655 ;
     RECT  2.16 20.925 19.44 21.195 ;
     RECT  2.16 21.465 19.44 21.735 ;
     RECT  2.16 22.005 19.44 22.275 ;
     RECT  2.16 22.545 19.44 22.815 ;
     RECT  2.16 23.085 19.44 23.355 ;
     RECT  2.16 23.625 19.44 23.895 ;
     RECT  2.16 24.165 19.44 24.435 ;
     RECT  2.16 24.705 19.44 24.975 ;
     RECT  2.16 25.245 19.44 25.515 ;
     RECT  2.16 25.785 19.44 26.055 ;
     RECT  2.16 26.325 19.44 26.595 ;
     RECT  2.16 26.865 19.44 27.135 ;
     RECT  2.16 27.405 19.44 27.675 ;
     RECT  2.16 27.945 19.44 28.215 ;
     RECT  2.16 28.485 19.44 28.755 ;
     RECT  2.16 29.025 19.44 29.295 ;
     RECT  2.16 29.565 19.44 29.835 ;
     RECT  2.16 30.105 19.44 30.375 ;
     RECT  2.16 30.645 19.44 30.915 ;
     RECT  2.16 31.185 19.44 31.455 ;
     RECT  2.16 31.725 19.44 31.995 ;
     RECT  2.16 32.265 19.44 32.535 ;
     RECT  2.16 32.805 19.44 33.075 ;
     RECT  2.16 33.345 19.44 33.615 ;
     RECT  2.16 33.885 19.44 34.155 ;
     RECT  2.16 34.425 19.44 34.695 ;
     RECT  2.16 34.965 19.44 35.235 ;
     RECT  2.16 35.505 19.44 35.775 ;
     RECT  2.16 36.045 19.44 36.315 ;
     RECT  2.16 36.585 19.44 36.855 ;
     RECT  2.16 37.125 19.44 37.395 ;
     RECT  2.16 37.665 19.44 37.935 ;
     RECT  2.16 38.205 19.44 38.475 ;
     RECT  2.16 38.745 19.44 39.015 ;
     RECT  2.16 39.285 19.44 39.555 ;
     RECT  2.16 39.825 19.44 40.095 ;
     RECT  2.16 40.365 19.44 40.635 ;
     RECT  2.16 40.905 19.44 41.175 ;
     RECT  2.16 41.445 19.44 41.715 ;
     RECT  2.16 41.985 19.44 42.255 ;
     RECT  2.16 42.525 19.44 42.795 ;
     RECT  2.16 43.065 19.44 43.335 ;
     RECT  2.16 43.605 19.44 43.875 ;
     RECT  2.16 44.145 19.44 44.415 ;
     RECT  2.16 44.685 19.44 44.955 ;
     RECT  2.16 45.225 19.44 45.495 ;
     RECT  2.16 45.765 19.44 46.035 ;
     RECT  2.16 46.305 19.44 46.575 ;
     RECT  2.16 46.845 19.44 47.115 ;
     RECT  2.16 47.385 19.44 47.655 ;
     RECT  2.16 47.925 19.44 48.195 ;
     RECT  2.16 48.465 19.44 48.735 ;
     RECT  2.16 49.005 19.44 49.275 ;
     RECT  2.16 49.545 19.44 49.815 ;
     RECT  2.16 50.085 19.44 50.355 ;
     RECT  2.16 50.625 19.44 50.895 ;
     RECT  2.16 51.165 19.44 51.435 ;
     RECT  2.16 51.705 19.44 51.975 ;
     RECT  2.16 52.245 19.44 52.515 ;
     RECT  2.16 52.785 19.44 53.055 ;
     RECT  2.16 53.325 19.44 53.595 ;
     RECT  2.16 53.865 19.44 54.135 ;
     RECT  2.16 54.405 19.44 54.675 ;
     RECT  2.16 54.945 19.44 55.215 ;
     RECT  2.16 55.485 19.44 55.755 ;
     RECT  2.16 56.025 19.44 56.295 ;
     RECT  2.16 56.565 19.44 56.835 ;
     RECT  2.16 57.105 19.44 57.375 ;
     RECT  2.16 57.645 19.44 57.915 ;
     RECT  2.16 58.185 19.44 58.455 ;
     RECT  2.16 58.725 19.44 58.995 ;
     RECT  2.16 59.265 19.44 59.535 ;
     RECT  2.16 59.805 19.44 60.075 ;
     RECT  2.16 60.345 19.44 60.615 ;
     RECT  2.16 60.885 19.44 61.155 ;
     RECT  2.16 61.425 19.44 61.695 ;
     RECT  2.16 61.965 19.44 62.235 ;
     RECT  2.16 62.505 19.44 62.775 ;
     RECT  2.16 63.045 19.44 63.315 ;
     RECT  2.16 63.585 19.44 63.855 ;
     RECT  2.16 64.125 19.44 64.395 ;
     RECT  2.16 64.665 19.44 64.935 ;
     RECT  2.16 65.205 19.44 65.475 ;
     RECT  2.16 65.745 19.44 66.015 ;
     RECT  2.16 66.285 19.44 66.555 ;
     RECT  2.16 66.825 19.44 67.095 ;
     RECT  2.16 67.365 19.44 67.635 ;
     RECT  2.16 67.905 19.44 68.175 ;
     RECT  2.16 68.445 19.44 68.715 ;
     RECT  2.16 68.985 19.44 69.255 ;
     RECT  2.16 69.525 19.44 69.795 ;
     RECT  2.16 70.065 19.44 70.335 ;
     RECT  2.16 70.605 19.44 70.875 ;
     RECT  2.16 71.145 19.44 71.415 ;
     RECT  2.16 71.685 19.44 71.955 ;
     RECT  2.16 72.225 19.44 72.495 ;
     RECT  2.16 72.765 19.44 73.035 ;
     RECT  2.16 73.305 19.44 73.575 ;
     RECT  2.16 73.845 19.44 74.115 ;
     RECT  2.16 74.385 19.44 74.655 ;
     RECT  2.16 74.925 19.44 75.195 ;
     RECT  2.16 75.465 19.44 75.735 ;
     RECT  2.16 76.005 19.44 76.275 ;
     RECT  2.16 76.545 19.44 76.815 ;
     RECT  2.16 77.085 19.44 77.355 ;
     RECT  2.16 77.625 19.44 77.895 ;
     RECT  2.16 78.165 19.44 78.435 ;
     RECT  2.16 78.705 19.44 78.975 ;
     RECT  2.16 79.245 19.44 79.515 ;
     RECT  2.16 79.785 19.44 80.055 ;
     RECT  2.16 80.325 19.44 80.595 ;
     RECT  2.16 80.865 19.44 81.135 ;
     RECT  2.16 81.405 19.44 81.675 ;
     RECT  2.16 81.945 19.44 82.215 ;
     RECT  2.16 82.485 19.44 82.755 ;
     RECT  2.16 83.025 19.44 83.295 ;
     RECT  2.16 83.565 19.44 83.835 ;
     RECT  2.16 84.105 19.44 84.375 ;
     RECT  2.16 84.645 19.44 84.915 ;
     RECT  2.16 85.185 19.44 85.455 ;
     RECT  2.16 85.725 19.44 85.995 ;
     RECT  2.16 86.265 19.44 86.535 ;
     RECT  2.16 86.805 19.44 87.075 ;
     RECT  2.16 87.345 19.44 87.615 ;
     RECT  2.16 87.885 19.44 88.155 ;
     RECT  2.16 88.425 19.44 88.695 ;
     RECT  2.16 88.965 19.44 89.235 ;
     RECT  2.16 89.505 19.44 89.775 ;
     RECT  2.16 90.045 19.44 90.315 ;
     RECT  2.16 90.585 19.44 90.855 ;
     RECT  2.16 91.125 19.44 91.395 ;
     RECT  2.16 91.665 19.44 91.935 ;
     RECT  2.16 92.205 19.44 92.475 ;
     RECT  2.16 92.745 19.44 93.015 ;
     RECT  2.16 93.285 19.44 93.555 ;
     RECT  2.16 93.825 19.44 94.095 ;
     RECT  2.16 94.365 19.44 94.635 ;
     RECT  2.16 94.905 19.44 95.175 ;
     RECT  2.16 95.445 19.44 95.715 ;
     RECT  2.16 95.985 19.44 96.255 ;
     RECT  2.16 96.525 19.44 96.795 ;
     RECT  2.16 97.065 19.44 97.335 ;
     RECT  2.16 97.605 19.44 97.875 ;
     RECT  2.16 98.145 19.44 98.415 ;
     RECT  2.16 98.685 19.44 98.955 ;
     RECT  2.16 99.225 19.44 99.495 ;
     RECT  2.16 99.765 19.44 100.035 ;
     RECT  2.16 100.305 19.44 100.575 ;
     RECT  2.16 100.845 19.44 101.115 ;
     RECT  2.16 101.385 19.44 101.655 ;
     RECT  2.16 101.925 19.44 102.195 ;
     RECT  2.16 102.465 19.44 102.735 ;
     RECT  2.16 103.005 19.44 103.275 ;
     RECT  2.16 103.545 19.44 103.815 ;
     RECT  2.16 104.085 19.44 104.355 ;
     RECT  2.16 104.625 19.44 104.895 ;
     RECT  2.16 105.165 19.44 105.435 ;
     RECT  2.16 105.705 19.44 105.975 ;
     RECT  2.16 106.245 19.44 106.515 ;
     RECT  2.16 106.785 19.44 107.055 ;
     RECT  2.16 107.325 19.44 107.595 ;
     RECT  2.16 107.865 19.44 108.135 ;
     RECT  2.16 108.405 19.44 108.675 ;
     RECT  2.16 108.945 19.44 109.215 ;
     RECT  2.16 109.485 19.44 109.755 ;
     RECT  2.16 110.025 19.44 110.295 ;
     RECT  2.16 110.565 19.44 110.835 ;
     RECT  2.16 111.105 19.44 111.375 ;
     RECT  2.16 111.645 19.44 111.915 ;
     RECT  2.16 112.185 19.44 112.455 ;
     RECT  2.16 112.725 19.44 112.995 ;
     RECT  2.16 113.265 19.44 113.535 ;
     RECT  2.16 113.805 19.44 114.075 ;
     RECT  2.16 114.345 19.44 114.615 ;
     RECT  2.16 114.885 19.44 115.155 ;
     RECT  2.16 115.425 19.44 115.695 ;
     RECT  2.16 115.965 19.44 116.235 ;
     RECT  2.16 116.505 19.44 116.775 ;
     RECT  2.16 117.045 19.44 117.315 ;
     RECT  2.16 117.585 19.44 117.855 ;
     RECT  2.16 118.125 19.44 118.395 ;
     RECT  2.16 118.665 19.44 118.935 ;
     RECT  2.16 119.205 19.44 119.475 ;
     RECT  2.16 119.745 19.44 120.015 ;
     RECT  2.16 120.285 19.44 120.555 ;
     RECT  2.16 120.825 19.44 121.095 ;
     RECT  2.16 121.365 19.44 121.635 ;
     RECT  2.16 121.905 19.44 122.175 ;
     RECT  2.16 122.445 19.44 122.715 ;
     RECT  2.16 122.985 19.44 123.255 ;
     RECT  2.16 123.525 19.44 123.795 ;
     RECT  2.16 124.065 19.44 124.335 ;
     RECT  2.16 124.605 19.44 124.875 ;
     RECT  2.16 125.145 19.44 125.415 ;
     RECT  2.16 125.685 19.44 125.955 ;
     RECT  2.16 126.225 19.44 126.495 ;
     RECT  2.16 126.765 19.44 127.035 ;
     RECT  2.16 127.305 19.44 127.575 ;
     RECT  2.16 127.845 19.44 128.115 ;
     RECT  2.16 128.385 19.44 128.655 ;
     RECT  2.16 128.925 19.44 129.195 ;
     RECT  2.16 129.465 19.44 129.735 ;
     RECT  2.16 130.005 19.44 130.275 ;
     RECT  2.16 130.545 19.44 130.815 ;
     RECT  2.16 131.085 19.44 131.355 ;
     RECT  2.16 131.625 19.44 131.895 ;
     RECT  2.16 132.165 19.44 132.435 ;
     RECT  2.16 132.705 19.44 132.975 ;
     RECT  2.16 133.245 19.44 133.515 ;
     RECT  2.16 133.785 19.44 134.055 ;
     RECT  2.16 134.325 19.44 134.595 ;
     RECT  2.16 134.865 19.44 135.135 ;
     RECT  2.16 135.405 19.44 135.675 ;
     RECT  2.16 135.945 19.44 136.215 ;
     RECT  2.16 136.485 19.44 136.755 ;
     RECT  2.16 137.025 19.44 137.295 ;
     RECT  2.16 137.565 19.44 137.835 ;
     RECT  2.16 138.105 19.44 138.375 ;
     RECT  2.16 138.645 19.44 138.915 ;
     RECT  2.16 139.185 19.44 139.455 ;
     RECT  2.16 139.725 19.44 139.995 ;
     RECT  2.16 140.265 19.44 140.535 ;
     RECT  2.16 140.805 19.44 141.075 ;
     RECT  2.16 141.345 19.44 141.615 ;
     RECT  2.16 141.885 19.44 142.155 ;
     RECT  2.16 142.425 19.44 142.695 ;
     RECT  2.16 142.965 19.44 143.235 ;
     RECT  2.16 143.505 19.44 143.775 ;
     RECT  2.16 144.045 19.44 144.315 ;
     RECT  2.16 144.585 19.44 144.72 ;
    LAYER RVTP ;
     RECT  2.16 2.295 19.44 2.565 ;
     RECT  2.16 2.835 19.44 3.105 ;
     RECT  2.16 3.375 19.44 3.645 ;
     RECT  2.16 3.915 19.44 4.185 ;
     RECT  2.16 4.455 19.44 4.725 ;
     RECT  2.16 4.995 19.44 5.265 ;
     RECT  2.16 5.535 19.44 5.805 ;
     RECT  2.16 6.075 19.44 6.345 ;
     RECT  2.16 6.615 19.44 6.885 ;
     RECT  2.16 7.155 19.44 7.425 ;
     RECT  2.16 7.695 19.44 7.965 ;
     RECT  2.16 8.235 19.44 8.505 ;
     RECT  2.16 8.775 19.44 9.045 ;
     RECT  2.16 9.315 19.44 9.585 ;
     RECT  2.16 9.855 19.44 10.125 ;
     RECT  2.16 10.395 19.44 10.665 ;
     RECT  2.16 10.935 19.44 11.205 ;
     RECT  2.16 11.475 19.44 11.745 ;
     RECT  2.16 12.015 19.44 12.285 ;
     RECT  2.16 12.555 19.44 12.825 ;
     RECT  2.16 13.095 19.44 13.365 ;
     RECT  2.16 13.635 19.44 13.905 ;
     RECT  2.16 14.175 19.44 14.445 ;
     RECT  2.16 14.715 19.44 14.985 ;
     RECT  2.16 15.255 19.44 15.525 ;
     RECT  2.16 15.795 19.44 16.065 ;
     RECT  2.16 16.335 19.44 16.605 ;
     RECT  2.16 16.875 19.44 17.145 ;
     RECT  2.16 17.415 19.44 17.685 ;
     RECT  2.16 17.955 19.44 18.225 ;
     RECT  2.16 18.495 19.44 18.765 ;
     RECT  2.16 19.035 19.44 19.305 ;
     RECT  2.16 19.575 19.44 19.845 ;
     RECT  2.16 20.115 19.44 20.385 ;
     RECT  2.16 20.655 19.44 20.925 ;
     RECT  2.16 21.195 19.44 21.465 ;
     RECT  2.16 21.735 19.44 22.005 ;
     RECT  2.16 22.275 19.44 22.545 ;
     RECT  2.16 22.815 19.44 23.085 ;
     RECT  2.16 23.355 19.44 23.625 ;
     RECT  2.16 23.895 19.44 24.165 ;
     RECT  2.16 24.435 19.44 24.705 ;
     RECT  2.16 24.975 19.44 25.245 ;
     RECT  2.16 25.515 19.44 25.785 ;
     RECT  2.16 26.055 19.44 26.325 ;
     RECT  2.16 26.595 19.44 26.865 ;
     RECT  2.16 27.135 19.44 27.405 ;
     RECT  2.16 27.675 19.44 27.945 ;
     RECT  2.16 28.215 19.44 28.485 ;
     RECT  2.16 28.755 19.44 29.025 ;
     RECT  2.16 29.295 19.44 29.565 ;
     RECT  2.16 29.835 19.44 30.105 ;
     RECT  2.16 30.375 19.44 30.645 ;
     RECT  2.16 30.915 19.44 31.185 ;
     RECT  2.16 31.455 19.44 31.725 ;
     RECT  2.16 31.995 19.44 32.265 ;
     RECT  2.16 32.535 19.44 32.805 ;
     RECT  2.16 33.075 19.44 33.345 ;
     RECT  2.16 33.615 19.44 33.885 ;
     RECT  2.16 34.155 19.44 34.425 ;
     RECT  2.16 34.695 19.44 34.965 ;
     RECT  2.16 35.235 19.44 35.505 ;
     RECT  2.16 35.775 19.44 36.045 ;
     RECT  2.16 36.315 19.44 36.585 ;
     RECT  2.16 36.855 19.44 37.125 ;
     RECT  2.16 37.395 19.44 37.665 ;
     RECT  2.16 37.935 19.44 38.205 ;
     RECT  2.16 38.475 19.44 38.745 ;
     RECT  2.16 39.015 19.44 39.285 ;
     RECT  2.16 39.555 19.44 39.825 ;
     RECT  2.16 40.095 19.44 40.365 ;
     RECT  2.16 40.635 19.44 40.905 ;
     RECT  2.16 41.175 19.44 41.445 ;
     RECT  2.16 41.715 19.44 41.985 ;
     RECT  2.16 42.255 19.44 42.525 ;
     RECT  2.16 42.795 19.44 43.065 ;
     RECT  2.16 43.335 19.44 43.605 ;
     RECT  2.16 43.875 19.44 44.145 ;
     RECT  2.16 44.415 19.44 44.685 ;
     RECT  2.16 44.955 19.44 45.225 ;
     RECT  2.16 45.495 19.44 45.765 ;
     RECT  2.16 46.035 19.44 46.305 ;
     RECT  2.16 46.575 19.44 46.845 ;
     RECT  2.16 47.115 19.44 47.385 ;
     RECT  2.16 47.655 19.44 47.925 ;
     RECT  2.16 48.195 19.44 48.465 ;
     RECT  2.16 48.735 19.44 49.005 ;
     RECT  2.16 49.275 19.44 49.545 ;
     RECT  2.16 49.815 19.44 50.085 ;
     RECT  2.16 50.355 19.44 50.625 ;
     RECT  2.16 50.895 19.44 51.165 ;
     RECT  2.16 51.435 19.44 51.705 ;
     RECT  2.16 51.975 19.44 52.245 ;
     RECT  2.16 52.515 19.44 52.785 ;
     RECT  2.16 53.055 19.44 53.325 ;
     RECT  2.16 53.595 19.44 53.865 ;
     RECT  2.16 54.135 19.44 54.405 ;
     RECT  2.16 54.675 19.44 54.945 ;
     RECT  2.16 55.215 19.44 55.485 ;
     RECT  2.16 55.755 19.44 56.025 ;
     RECT  2.16 56.295 19.44 56.565 ;
     RECT  2.16 56.835 19.44 57.105 ;
     RECT  2.16 57.375 19.44 57.645 ;
     RECT  2.16 57.915 19.44 58.185 ;
     RECT  2.16 58.455 19.44 58.725 ;
     RECT  2.16 58.995 19.44 59.265 ;
     RECT  2.16 59.535 19.44 59.805 ;
     RECT  2.16 60.075 19.44 60.345 ;
     RECT  2.16 60.615 19.44 60.885 ;
     RECT  2.16 61.155 19.44 61.425 ;
     RECT  2.16 61.695 19.44 61.965 ;
     RECT  2.16 62.235 19.44 62.505 ;
     RECT  2.16 62.775 19.44 63.045 ;
     RECT  2.16 63.315 19.44 63.585 ;
     RECT  2.16 63.855 19.44 64.125 ;
     RECT  2.16 64.395 19.44 64.665 ;
     RECT  2.16 64.935 19.44 65.205 ;
     RECT  2.16 65.475 19.44 65.745 ;
     RECT  2.16 66.015 19.44 66.285 ;
     RECT  2.16 66.555 19.44 66.825 ;
     RECT  2.16 67.095 19.44 67.365 ;
     RECT  2.16 67.635 19.44 67.905 ;
     RECT  2.16 68.175 19.44 68.445 ;
     RECT  2.16 68.715 19.44 68.985 ;
     RECT  2.16 69.255 19.44 69.525 ;
     RECT  2.16 69.795 19.44 70.065 ;
     RECT  2.16 70.335 19.44 70.605 ;
     RECT  2.16 70.875 19.44 71.145 ;
     RECT  2.16 71.415 19.44 71.685 ;
     RECT  2.16 71.955 19.44 72.225 ;
     RECT  2.16 72.495 19.44 72.765 ;
     RECT  2.16 73.035 19.44 73.305 ;
     RECT  2.16 73.575 19.44 73.845 ;
     RECT  2.16 74.115 19.44 74.385 ;
     RECT  2.16 74.655 19.44 74.925 ;
     RECT  2.16 75.195 19.44 75.465 ;
     RECT  2.16 75.735 19.44 76.005 ;
     RECT  2.16 76.275 19.44 76.545 ;
     RECT  2.16 76.815 19.44 77.085 ;
     RECT  2.16 77.355 19.44 77.625 ;
     RECT  2.16 77.895 19.44 78.165 ;
     RECT  2.16 78.435 19.44 78.705 ;
     RECT  2.16 78.975 19.44 79.245 ;
     RECT  2.16 79.515 19.44 79.785 ;
     RECT  2.16 80.055 19.44 80.325 ;
     RECT  2.16 80.595 19.44 80.865 ;
     RECT  2.16 81.135 19.44 81.405 ;
     RECT  2.16 81.675 19.44 81.945 ;
     RECT  2.16 82.215 19.44 82.485 ;
     RECT  2.16 82.755 19.44 83.025 ;
     RECT  2.16 83.295 19.44 83.565 ;
     RECT  2.16 83.835 19.44 84.105 ;
     RECT  2.16 84.375 19.44 84.645 ;
     RECT  2.16 84.915 19.44 85.185 ;
     RECT  2.16 85.455 19.44 85.725 ;
     RECT  2.16 85.995 19.44 86.265 ;
     RECT  2.16 86.535 19.44 86.805 ;
     RECT  2.16 87.075 19.44 87.345 ;
     RECT  2.16 87.615 19.44 87.885 ;
     RECT  2.16 88.155 19.44 88.425 ;
     RECT  2.16 88.695 19.44 88.965 ;
     RECT  2.16 89.235 19.44 89.505 ;
     RECT  2.16 89.775 19.44 90.045 ;
     RECT  2.16 90.315 19.44 90.585 ;
     RECT  2.16 90.855 19.44 91.125 ;
     RECT  2.16 91.395 19.44 91.665 ;
     RECT  2.16 91.935 19.44 92.205 ;
     RECT  2.16 92.475 19.44 92.745 ;
     RECT  2.16 93.015 19.44 93.285 ;
     RECT  2.16 93.555 19.44 93.825 ;
     RECT  2.16 94.095 19.44 94.365 ;
     RECT  2.16 94.635 19.44 94.905 ;
     RECT  2.16 95.175 19.44 95.445 ;
     RECT  2.16 95.715 19.44 95.985 ;
     RECT  2.16 96.255 19.44 96.525 ;
     RECT  2.16 96.795 19.44 97.065 ;
     RECT  2.16 97.335 19.44 97.605 ;
     RECT  2.16 97.875 19.44 98.145 ;
     RECT  2.16 98.415 19.44 98.685 ;
     RECT  2.16 98.955 19.44 99.225 ;
     RECT  2.16 99.495 19.44 99.765 ;
     RECT  2.16 100.035 19.44 100.305 ;
     RECT  2.16 100.575 19.44 100.845 ;
     RECT  2.16 101.115 19.44 101.385 ;
     RECT  2.16 101.655 19.44 101.925 ;
     RECT  2.16 102.195 19.44 102.465 ;
     RECT  2.16 102.735 19.44 103.005 ;
     RECT  2.16 103.275 19.44 103.545 ;
     RECT  2.16 103.815 19.44 104.085 ;
     RECT  2.16 104.355 19.44 104.625 ;
     RECT  2.16 104.895 19.44 105.165 ;
     RECT  2.16 105.435 19.44 105.705 ;
     RECT  2.16 105.975 19.44 106.245 ;
     RECT  2.16 106.515 19.44 106.785 ;
     RECT  2.16 107.055 19.44 107.325 ;
     RECT  2.16 107.595 19.44 107.865 ;
     RECT  2.16 108.135 19.44 108.405 ;
     RECT  2.16 108.675 19.44 108.945 ;
     RECT  2.16 109.215 19.44 109.485 ;
     RECT  2.16 109.755 19.44 110.025 ;
     RECT  2.16 110.295 19.44 110.565 ;
     RECT  2.16 110.835 19.44 111.105 ;
     RECT  2.16 111.375 19.44 111.645 ;
     RECT  2.16 111.915 19.44 112.185 ;
     RECT  2.16 112.455 19.44 112.725 ;
     RECT  2.16 112.995 19.44 113.265 ;
     RECT  2.16 113.535 19.44 113.805 ;
     RECT  2.16 114.075 19.44 114.345 ;
     RECT  2.16 114.615 19.44 114.885 ;
     RECT  2.16 115.155 19.44 115.425 ;
     RECT  2.16 115.695 19.44 115.965 ;
     RECT  2.16 116.235 19.44 116.505 ;
     RECT  2.16 116.775 19.44 117.045 ;
     RECT  2.16 117.315 19.44 117.585 ;
     RECT  2.16 117.855 19.44 118.125 ;
     RECT  2.16 118.395 19.44 118.665 ;
     RECT  2.16 118.935 19.44 119.205 ;
     RECT  2.16 119.475 19.44 119.745 ;
     RECT  2.16 120.015 19.44 120.285 ;
     RECT  2.16 120.555 19.44 120.825 ;
     RECT  2.16 121.095 19.44 121.365 ;
     RECT  2.16 121.635 19.44 121.905 ;
     RECT  2.16 122.175 19.44 122.445 ;
     RECT  2.16 122.715 19.44 122.985 ;
     RECT  2.16 123.255 19.44 123.525 ;
     RECT  2.16 123.795 19.44 124.065 ;
     RECT  2.16 124.335 19.44 124.605 ;
     RECT  2.16 124.875 19.44 125.145 ;
     RECT  2.16 125.415 19.44 125.685 ;
     RECT  2.16 125.955 19.44 126.225 ;
     RECT  2.16 126.495 19.44 126.765 ;
     RECT  2.16 127.035 19.44 127.305 ;
     RECT  2.16 127.575 19.44 127.845 ;
     RECT  2.16 128.115 19.44 128.385 ;
     RECT  2.16 128.655 19.44 128.925 ;
     RECT  2.16 129.195 19.44 129.465 ;
     RECT  2.16 129.735 19.44 130.005 ;
     RECT  2.16 130.275 19.44 130.545 ;
     RECT  2.16 130.815 19.44 131.085 ;
     RECT  2.16 131.355 19.44 131.625 ;
     RECT  2.16 131.895 19.44 132.165 ;
     RECT  2.16 132.435 19.44 132.705 ;
     RECT  2.16 132.975 19.44 133.245 ;
     RECT  2.16 133.515 19.44 133.785 ;
     RECT  2.16 134.055 19.44 134.325 ;
     RECT  2.16 134.595 19.44 134.865 ;
     RECT  2.16 135.135 19.44 135.405 ;
     RECT  2.16 135.675 19.44 135.945 ;
     RECT  2.16 136.215 19.44 136.485 ;
     RECT  2.16 136.755 19.44 137.025 ;
     RECT  2.16 137.295 19.44 137.565 ;
     RECT  2.16 137.835 19.44 138.105 ;
     RECT  2.16 138.375 19.44 138.645 ;
     RECT  2.16 138.915 19.44 139.185 ;
     RECT  2.16 139.455 19.44 139.725 ;
     RECT  2.16 139.995 19.44 140.265 ;
     RECT  2.16 140.535 19.44 140.805 ;
     RECT  2.16 141.075 19.44 141.345 ;
     RECT  2.16 141.615 19.44 141.885 ;
     RECT  2.16 142.155 19.44 142.425 ;
     RECT  2.16 142.695 19.44 142.965 ;
     RECT  2.16 143.235 19.44 143.505 ;
     RECT  2.16 143.775 19.44 144.045 ;
     RECT  2.16 144.315 19.44 144.585 ;
    LAYER M1 ;
     RECT  2.16 2.151 19.44 144.729 ;
    LAYER M2 ;
     RECT  0.103 4.122 2.16 4.14 ;
     RECT  0.103 15.192 2.16 15.21 ;
     RECT  0.103 22.212 2.16 22.806 ;
     RECT  0.103 28.422 2.16 28.44 ;
     RECT  0.103 30.582 2.16 30.6 ;
     RECT  0.103 32.202 2.16 32.76 ;
     RECT  0.103 37.602 2.16 37.62 ;
     RECT  0.103 43.272 2.16 43.29 ;
     RECT  0.103 52.992 2.16 53.01 ;
     RECT  0.103 56.916 2.16 56.934 ;
     RECT  0.103 59.202 2.16 59.22 ;
     RECT  0.103 74.592 2.16 74.61 ;
     RECT  0.535 84.348 2.16 84.366 ;
     RECT  0.139 85.122 2.16 85.68 ;
     RECT  0.103 87.282 2.16 87.3 ;
     RECT  0.103 98.892 2.16 98.91 ;
     RECT  0.103 101.052 2.16 101.07 ;
     RECT  0.103 113.742 2.16 113.76 ;
     RECT  0.103 116.442 2.16 116.46 ;
     RECT  0.103 118.602 2.16 118.62 ;
     RECT  0.103 127.512 2.16 127.53 ;
     RECT  0.103 129.132 2.16 129.15 ;
     RECT  0.535 135.612 2.16 135.63 ;
     RECT  0.103 142.902 2.16 142.92 ;
     RECT  2.16 2.151 19.44 144.729 ;
     RECT  19.44 7.326 19.967 10.044 ;
     RECT  19.44 11.916 19.967 21.114 ;
     RECT  19.44 23.256 19.967 25.434 ;
     RECT  19.44 57.546 19.967 66.744 ;
     RECT  19.44 72.846 19.967 80.514 ;
     RECT  19.44 88.326 19.967 95.904 ;
     RECT  19.44 104.256 19.967 107.514 ;
     RECT  19.44 108.576 19.967 110.25 ;
     RECT  19.44 119.646 19.967 123.444 ;
     RECT  19.44 124.236 19.967 125.064 ;
     RECT  19.44 125.892 19.967 134.01 ;
     RECT  19.44 135.036 19.967 135.054 ;
     RECT  19.44 136.116 19.967 139.374 ;
     RECT  19.44 140.436 19.967 140.454 ;
     RECT  19.967 11.916 20.507 18.414 ;
     RECT  19.44 26.766 20.507 29.214 ;
     RECT  19.44 30.006 20.507 36.54 ;
     RECT  19.967 57.546 20.507 60.804 ;
     RECT  19.44 67.572 20.507 68.094 ;
     RECT  19.44 69.156 20.507 70.794 ;
     RECT  19.967 73.476 20.507 75.114 ;
     RECT  19.44 82.926 20.507 84.024 ;
     RECT  19.44 85.086 20.507 87.264 ;
     RECT  19.967 88.326 20.507 88.884 ;
     RECT  19.44 97.812 20.507 102.654 ;
     RECT  19.44 111.006 20.507 112.374 ;
     RECT  19.44 113.166 20.507 118.584 ;
     RECT  19.967 124.236 20.507 124.794 ;
     RECT  19.967 125.892 20.507 132.894 ;
     RECT  19.44 141.246 20.507 141.804 ;
     RECT  19.967 7.326 20.543 8.424 ;
     RECT  19.967 9.486 20.543 10.044 ;
     RECT  19.44 11.106 20.543 11.124 ;
     RECT  20.507 17.856 20.543 18.414 ;
     RECT  19.967 20.556 20.543 21.114 ;
     RECT  19.967 24.336 20.543 25.434 ;
     RECT  20.507 27.846 20.543 29.214 ;
     RECT  20.507 33.246 20.543 33.264 ;
     RECT  20.507 34.326 20.543 36.54 ;
     RECT  19.44 38.376 20.543 38.664 ;
     RECT  19.44 39.726 20.543 40.284 ;
     RECT  19.44 45.936 20.543 51.894 ;
     RECT  19.44 56.196 20.543 56.214 ;
     RECT  19.967 61.866 20.543 61.884 ;
     RECT  19.967 62.982 20.543 63.504 ;
     RECT  19.967 65.106 20.543 65.664 ;
     RECT  19.967 76.752 20.543 77.814 ;
     RECT  19.967 78.876 20.543 78.894 ;
     RECT  19.44 81.306 20.543 82.134 ;
     RECT  19.967 90.486 20.543 90.504 ;
     RECT  19.967 92.106 20.543 93.744 ;
     RECT  19.967 95.346 20.543 95.904 ;
     RECT  19.44 96.696 20.543 96.984 ;
     RECT  19.967 104.256 20.543 104.274 ;
     RECT  19.967 105.876 20.543 105.894 ;
     RECT  19.967 106.956 20.543 107.514 ;
     RECT  19.967 108.576 20.543 108.594 ;
     RECT  20.507 112.086 20.543 112.374 ;
     RECT  20.507 117.486 20.543 118.584 ;
     RECT  19.967 119.646 20.543 121.824 ;
     RECT  19.967 122.922 20.543 123.444 ;
     RECT  20.507 132.876 20.543 132.894 ;
     RECT  19.967 136.116 20.543 137.214 ;
     RECT  19.967 138.312 20.543 138.33 ;
     RECT  19.967 139.356 20.543 139.374 ;
     RECT  19.44 3.006 21.515 3.564 ;
     RECT  19.44 4.626 21.515 4.644 ;
     RECT  19.44 5.742 21.515 5.76 ;
     RECT  20.507 11.916 21.515 12.474 ;
     RECT  20.507 13.536 21.515 14.094 ;
     RECT  20.507 15.156 21.515 16.794 ;
     RECT  20.543 18.396 21.515 18.414 ;
     RECT  20.543 27.846 21.515 28.944 ;
     RECT  20.507 30.546 21.515 31.104 ;
     RECT  20.507 32.166 21.515 32.184 ;
     RECT  20.543 38.376 21.515 38.394 ;
     RECT  19.44 42.156 21.515 44.874 ;
     RECT  20.543 46.476 21.515 47.034 ;
     RECT  20.543 49.212 21.515 49.23 ;
     RECT  19.44 53.802 21.515 55.404 ;
     RECT  20.507 58.086 21.515 58.104 ;
     RECT  20.543 62.982 21.515 63 ;
     RECT  20.507 68.076 21.515 68.094 ;
     RECT  20.507 69.156 21.515 69.174 ;
     RECT  20.507 70.236 21.515 70.794 ;
     RECT  19.44 71.892 21.515 71.91 ;
     RECT  20.507 74.556 21.515 75.114 ;
     RECT  20.543 81.306 21.515 81.324 ;
     RECT  20.507 83.466 21.515 84.024 ;
     RECT  20.507 85.086 21.515 85.104 ;
     RECT  20.507 86.166 21.515 86.724 ;
     RECT  20.543 96.696 21.515 96.714 ;
     RECT  20.507 97.812 21.515 97.83 ;
     RECT  20.507 98.856 21.515 98.874 ;
     RECT  20.507 99.936 21.515 99.954 ;
     RECT  20.507 101.556 21.515 101.574 ;
     RECT  20.543 112.086 21.515 112.104 ;
     RECT  20.507 113.706 21.515 115.884 ;
     RECT  20.543 117.486 21.515 117.504 ;
     RECT  20.543 118.566 21.515 118.584 ;
     RECT  20.507 125.892 21.515 126.954 ;
     RECT  20.507 128.016 21.515 129.654 ;
     RECT  20.507 130.716 21.515 131.274 ;
     RECT  20.507 141.246 21.515 141.264 ;
     RECT  19.44 143.406 21.515 143.424 ;
    LAYER M3 ;
     RECT  2.415 2.143 2.505 2.395 ;
     RECT  2.304 2.395 2.505 2.413 ;
     RECT  5.115 2.143 5.205 2.413 ;
     RECT  7.815 2.143 7.905 2.413 ;
     RECT  10.515 2.143 10.605 2.413 ;
     RECT  13.215 2.143 13.305 2.413 ;
     RECT  15.915 2.143 16.005 2.413 ;
     RECT  18.615 2.143 18.705 2.413 ;
     RECT  18.615 2.413 18.897 2.461 ;
     RECT  18.216 2.461 18.897 2.525 ;
     RECT  2.304 2.413 2.697 2.569 ;
     RECT  2.304 2.569 3.186 2.641 ;
     RECT  2.304 2.641 3.258 2.717 ;
     RECT  5.115 2.413 5.397 3.181 ;
     RECT  5.115 3.181 5.634 3.245 ;
     RECT  5.115 3.245 5.397 3.547 ;
     RECT  2.304 2.717 2.697 3.605 ;
     RECT  4.68 3.547 5.397 3.605 ;
     RECT  18.615 2.525 18.897 4.081 ;
     RECT  0.108 4.075 0.126 4.145 ;
     RECT  18.216 4.081 18.897 4.205 ;
     RECT  5.115 3.605 5.397 4.225 ;
     RECT  5.115 4.225 5.994 4.301 ;
     RECT  2.415 3.605 2.697 4.603 ;
     RECT  4.32 4.603 4.338 4.649 ;
     RECT  21.492 2.395 21.51 4.649 ;
     RECT  18.615 4.205 18.897 5.161 ;
     RECT  18.615 5.161 19.422 5.213 ;
     RECT  2.304 4.603 2.697 5.225 ;
     RECT  5.115 4.301 5.397 5.341 ;
     RECT  4.356 5.707 4.374 5.765 ;
     RECT  21.492 5.707 21.51 5.765 ;
     RECT  5.115 5.341 5.634 5.845 ;
     RECT  5.115 5.845 5.778 5.885 ;
     RECT  11.772 6.241 11.79 6.317 ;
     RECT  4.32 6.763 4.338 6.781 ;
     RECT  18.615 5.213 18.897 6.781 ;
     RECT  2.415 5.225 2.697 6.808 ;
     RECT  2.412 6.808 2.697 6.845 ;
     RECT  18.615 6.781 19.422 6.845 ;
     RECT  4.248 6.781 4.338 6.989 ;
     RECT  4.32 6.989 4.338 7.357 ;
     RECT  5.115 5.885 5.397 7.357 ;
     RECT  4.32 7.357 5.397 7.421 ;
     RECT  4.032 7.897 4.05 7.949 ;
     RECT  6.84 6.385 6.858 8.033 ;
     RECT  7.815 2.413 8.097 8.437 ;
     RECT  7.596 8.437 8.097 8.477 ;
     RECT  20.52 7.321 20.538 8.525 ;
     RECT  2.415 6.845 2.697 9.013 ;
     RECT  2.415 9.013 2.826 9.053 ;
     RECT  19.944 8.941 19.962 9.053 ;
     RECT  2.415 9.053 2.697 9.595 ;
     RECT  4.248 8.539 4.266 9.677 ;
     RECT  2.304 9.595 2.697 10.157 ;
     RECT  20.52 9.481 20.538 10.157 ;
     RECT  3.996 10.699 4.014 10.843 ;
     RECT  11.736 10.699 11.754 10.859 ;
     RECT  7.056 10.975 7.074 11.021 ;
     RECT  2.415 10.157 2.697 11.227 ;
     RECT  3.996 10.843 4.266 11.245 ;
     RECT  20.52 11.101 20.538 11.261 ;
     RECT  3.96 11.245 4.266 11.273 ;
     RECT  3.96 11.273 3.978 11.941 ;
     RECT  2.304 11.227 2.697 11.975 ;
     RECT  3.42 11.941 3.978 11.981 ;
     RECT  5.115 7.421 5.397 12.331 ;
     RECT  21.492 11.755 21.51 12.479 ;
     RECT  4.5 12.331 5.397 12.515 ;
     RECT  6.84 12.523 6.858 12.623 ;
     RECT  5.115 12.515 5.397 13.003 ;
     RECT  20.484 12.859 20.502 13.019 ;
     RECT  3.996 12.859 4.014 13.055 ;
     RECT  5.115 13.003 5.994 13.055 ;
     RECT  2.415 11.975 2.697 13.435 ;
     RECT  4.284 13.603 4.302 13.661 ;
     RECT  21.492 13.435 21.51 14.099 ;
     RECT  3.42 14.203 3.438 14.243 ;
     RECT  5.115 13.055 5.397 14.635 ;
     RECT  20.484 14.539 20.502 14.639 ;
     RECT  2.304 13.435 2.697 14.675 ;
     RECT  5.115 14.635 5.778 14.675 ;
     RECT  0.108 15.067 0.126 15.215 ;
     RECT  6.84 15.187 6.858 15.295 ;
     RECT  6.84 15.295 7.074 15.341 ;
     RECT  6.84 15.341 6.858 15.359 ;
     RECT  2.415 14.675 2.697 15.643 ;
     RECT  4.284 15.691 4.302 16.541 ;
     RECT  5.115 14.675 5.397 16.795 ;
     RECT  21.492 15.067 21.51 16.799 ;
     RECT  5.115 16.795 5.778 16.835 ;
     RECT  5.115 16.835 5.397 17.323 ;
     RECT  20.484 17.275 20.502 17.339 ;
     RECT  5.004 17.323 5.397 17.375 ;
     RECT  7.815 8.477 8.097 17.455 ;
     RECT  7.815 17.455 8.154 17.501 ;
     RECT  4.32 17.803 4.338 17.879 ;
     RECT  20.52 17.845 20.538 17.885 ;
     RECT  5.115 17.375 5.397 18.379 ;
     RECT  21.492 18.379 21.51 18.419 ;
     RECT  5.115 18.379 5.634 18.955 ;
     RECT  5.115 18.955 5.778 18.995 ;
     RECT  7.815 17.501 8.097 19.483 ;
     RECT  4.14 19.483 4.158 19.535 ;
     RECT  7.815 19.483 8.154 19.901 ;
     RECT  19.944 18.931 19.962 20.045 ;
     RECT  2.304 15.643 2.697 20.075 ;
     RECT  2.415 20.075 2.697 20.191 ;
     RECT  2.415 20.191 3.258 20.237 ;
     RECT  5.115 18.995 5.397 20.539 ;
     RECT  4.5 20.539 5.397 20.615 ;
     RECT  2.415 20.237 2.826 20.621 ;
     RECT  6.84 21.115 6.858 21.127 ;
     RECT  20.52 20.551 20.538 21.149 ;
     RECT  3.996 21.115 4.014 21.155 ;
     RECT  6.84 21.127 6.93 21.155 ;
     RECT  10.515 2.413 10.797 21.631 ;
     RECT  10.515 21.631 11.358 21.725 ;
     RECT  5.115 20.615 5.397 21.883 ;
     RECT  4.428 21.883 5.397 22.027 ;
     RECT  4.14 22.027 5.397 22.109 ;
     RECT  6.912 21.155 6.93 22.171 ;
     RECT  6.84 22.171 6.93 22.199 ;
     RECT  4.428 22.109 5.397 22.235 ;
     RECT  11.628 22.207 11.646 22.253 ;
     RECT  5.115 22.235 5.397 22.699 ;
     RECT  5.115 22.699 5.634 22.739 ;
     RECT  0.108 22.207 0.126 22.829 ;
     RECT  12.168 22.783 12.186 22.829 ;
     RECT  3.996 23.323 4.014 23.36 ;
     RECT  6.84 22.199 6.858 23.423 ;
     RECT  5.115 22.739 5.397 23.827 ;
     RECT  6.516 23.791 6.606 23.837 ;
     RECT  6.516 23.837 6.534 23.891 ;
     RECT  4.464 23.827 5.397 23.933 ;
     RECT  19.944 23.251 19.962 23.933 ;
     RECT  2.415 20.621 2.697 24.427 ;
     RECT  2.304 24.427 2.697 24.503 ;
     RECT  2.412 24.503 2.697 25.043 ;
     RECT  4.248 24.331 4.266 25.085 ;
     RECT  6.3 25.435 6.318 25.475 ;
     RECT  2.415 25.043 2.697 25.519 ;
     RECT  2.415 25.519 2.826 25.565 ;
     RECT  20.52 24.331 20.538 25.565 ;
     RECT  12.312 26.107 12.33 26.249 ;
     RECT  3.996 26.107 4.014 26.285 ;
     RECT  7.056 26.365 7.074 26.573 ;
     RECT  4.248 26.731 4.338 26.789 ;
     RECT  4.248 26.789 4.266 26.969 ;
     RECT  2.415 25.565 2.697 27.211 ;
     RECT  5.115 23.933 5.397 27.211 ;
     RECT  3.744 27.211 3.762 27.329 ;
     RECT  5.115 27.211 5.778 27.329 ;
     RECT  20.484 26.635 20.502 27.365 ;
     RECT  5.115 27.329 5.397 27.877 ;
     RECT  2.304 27.211 2.697 27.905 ;
     RECT  4.68 27.877 5.397 27.917 ;
     RECT  7.815 19.901 8.097 28.411 ;
     RECT  0.108 28.315 0.126 28.445 ;
     RECT  7.815 28.411 8.154 28.451 ;
     RECT  2.415 27.905 2.697 28.843 ;
     RECT  21.492 27.739 21.51 28.949 ;
     RECT  2.304 28.843 2.697 28.985 ;
     RECT  4.356 29.101 4.374 29.405 ;
     RECT  20.52 29.191 20.538 29.405 ;
     RECT  2.415 28.985 2.697 29.947 ;
     RECT  20.484 29.947 20.502 30.029 ;
     RECT  2.304 29.947 2.697 30.065 ;
     RECT  6.84 30.037 6.858 30.077 ;
     RECT  5.115 27.917 5.397 30.571 ;
     RECT  0.108 30.475 0.126 30.605 ;
     RECT  5.115 30.571 5.994 30.611 ;
     RECT  2.415 30.065 2.697 31.051 ;
     RECT  21.492 30.475 21.51 31.109 ;
     RECT  4.356 30.811 4.374 31.261 ;
     RECT  5.115 30.611 5.397 31.261 ;
     RECT  4.356 31.261 5.397 31.289 ;
     RECT  20.484 31.579 20.502 31.649 ;
     RECT  2.304 31.051 2.697 31.685 ;
     RECT  4.536 31.289 5.397 31.853 ;
     RECT  21.492 32.152 21.51 32.189 ;
     RECT  4.68 31.853 5.397 32.225 ;
     RECT  20.484 32.683 20.502 32.729 ;
     RECT  7.815 28.451 8.097 32.731 ;
     RECT  0.108 32.155 0.126 32.765 ;
     RECT  7.815 32.731 8.154 32.771 ;
     RECT  6.84 32.701 6.858 32.873 ;
     RECT  5.115 32.225 5.397 33.067 ;
     RECT  2.415 31.685 2.697 33.259 ;
     RECT  20.52 33.241 20.538 33.293 ;
     RECT  2.304 33.259 2.697 33.845 ;
     RECT  20.484 33.787 20.502 33.845 ;
     RECT  4.5 33.067 5.397 33.931 ;
     RECT  4.5 33.931 6.03 33.965 ;
     RECT  7.815 32.771 8.097 34.027 ;
     RECT  5.115 33.965 6.03 34.079 ;
     RECT  7.488 34.027 8.586 34.079 ;
     RECT  5.115 34.079 5.706 34.355 ;
     RECT  4.14 34.357 4.338 34.397 ;
     RECT  10.515 21.725 10.797 34.501 ;
     RECT  7.488 34.079 8.097 34.529 ;
     RECT  4.32 34.397 4.338 34.619 ;
     RECT  10.296 34.501 10.797 34.619 ;
     RECT  7.815 34.529 8.097 34.888 ;
     RECT  7.815 34.888 8.154 34.925 ;
     RECT  6.84 34.735 6.858 35.033 ;
     RECT  2.415 33.845 2.697 35.437 ;
     RECT  2.415 35.437 2.826 35.501 ;
     RECT  4.284 35.545 4.302 35.597 ;
     RECT  2.415 35.501 2.697 35.995 ;
     RECT  2.304 35.995 2.697 36.041 ;
     RECT  3.456 36.121 3.474 36.173 ;
     RECT  5.115 34.355 5.397 36.571 ;
     RECT  20.52 34.321 20.538 36.605 ;
     RECT  4.464 36.571 5.397 36.653 ;
     RECT  11.88 36.517 11.898 36.689 ;
     RECT  7.815 34.925 8.097 37.021 ;
     RECT  10.515 34.619 10.797 37.021 ;
     RECT  7.092 37.021 8.097 37.193 ;
     RECT  4.5 36.653 5.397 37.579 ;
     RECT  4.392 37.579 5.397 37.625 ;
     RECT  0.108 37.597 0.126 37.709 ;
     RECT  10.515 37.021 11.43 37.709 ;
     RECT  2.415 36.041 2.697 38.203 ;
     RECT  5.115 37.625 5.397 38.347 ;
     RECT  21.492 38.203 21.51 38.399 ;
     RECT  2.304 38.203 2.697 38.435 ;
     RECT  5.115 38.347 5.634 38.713 ;
     RECT  20.52 38.641 20.538 38.765 ;
     RECT  4.536 38.713 5.922 38.849 ;
     RECT  4.536 38.849 5.397 39.307 ;
     RECT  10.515 37.709 10.797 39.307 ;
     RECT  10.515 39.307 11.394 39.479 ;
     RECT  6.84 39.487 6.858 39.589 ;
     RECT  6.84 39.589 7.074 39.629 ;
     RECT  6.84 39.629 6.858 39.659 ;
     RECT  2.415 38.435 2.697 39.829 ;
     RECT  4.464 39.307 5.397 39.865 ;
     RECT  4.392 39.865 5.397 39.917 ;
     RECT  20.52 39.721 20.538 40.445 ;
     RECT  2.415 39.829 2.826 40.939 ;
     RECT  12.06 40.939 12.078 41.099 ;
     RECT  2.415 40.939 2.862 41.135 ;
     RECT  10.515 39.479 10.797 41.419 ;
     RECT  2.415 41.135 2.697 41.512 ;
     RECT  14.724 41.419 14.85 41.549 ;
     RECT  6.84 41.215 6.858 41.597 ;
     RECT  10.515 41.419 11.394 41.639 ;
     RECT  3.996 41.515 4.014 41.675 ;
     RECT  7.815 37.193 8.097 41.749 ;
     RECT  7.815 41.749 8.154 41.789 ;
     RECT  2.304 41.512 2.697 42.139 ;
     RECT  4.176 42.061 4.194 42.179 ;
     RECT  10.515 41.639 10.854 42.179 ;
     RECT  2.304 42.139 3.222 42.215 ;
     RECT  5.115 39.917 5.397 42.667 ;
     RECT  2.304 42.215 2.697 42.755 ;
     RECT  4.5 42.667 5.397 42.755 ;
     RECT  4.536 42.755 5.397 42.797 ;
     RECT  5.115 42.797 5.397 43.267 ;
     RECT  0.108 43.147 0.126 43.295 ;
     RECT  5.115 43.267 5.778 43.325 ;
     RECT  5.115 43.325 5.397 43.675 ;
     RECT  2.415 42.755 2.697 43.681 ;
     RECT  5.004 43.675 5.397 43.835 ;
     RECT  7.056 43.807 7.074 43.853 ;
     RECT  4.32 44.299 4.338 44.311 ;
     RECT  4.248 44.311 4.338 44.339 ;
     RECT  4.248 44.339 4.266 44.411 ;
     RECT  3.456 44.443 3.474 44.879 ;
     RECT  21.492 42.043 21.51 44.879 ;
     RECT  18.615 6.845 18.897 45.355 ;
     RECT  18.615 45.355 19.386 45.419 ;
     RECT  3.996 45.403 4.014 45.455 ;
     RECT  6.84 45.535 6.858 45.581 ;
     RECT  5.115 43.835 5.397 45.931 ;
     RECT  20.52 45.925 20.538 45.965 ;
     RECT  5.004 45.931 5.397 45.995 ;
     RECT  5.115 45.995 5.397 46.069 ;
     RECT  5.115 46.069 5.994 46.109 ;
     RECT  5.115 46.109 5.67 46.781 ;
     RECT  21.492 46.459 21.51 47.039 ;
     RECT  4.32 46.459 4.338 47.155 ;
     RECT  5.115 46.781 5.49 47.155 ;
     RECT  4.32 47.155 5.49 47.315 ;
     RECT  4.32 47.315 5.397 47.563 ;
     RECT  4.068 47.563 5.397 47.615 ;
     RECT  4.68 47.615 5.397 47.741 ;
     RECT  2.304 43.681 2.697 48.128 ;
     RECT  5.004 47.741 5.397 48.155 ;
     RECT  7.056 48.229 7.074 48.269 ;
     RECT  2.415 48.128 2.697 48.667 ;
     RECT  20.52 47.551 20.538 48.701 ;
     RECT  2.415 48.667 2.754 48.704 ;
     RECT  4.32 48.805 4.338 48.845 ;
     RECT  10.515 42.179 10.797 49.207 ;
     RECT  21.492 49.195 21.51 49.235 ;
     RECT  3.42 49.315 3.438 49.373 ;
     RECT  10.515 49.207 11.358 49.379 ;
     RECT  2.415 48.704 2.697 49.747 ;
     RECT  2.415 49.747 2.826 49.805 ;
     RECT  5.115 48.155 5.397 49.855 ;
     RECT  4.68 49.855 5.397 49.901 ;
     RECT  3.996 50.287 4.014 50.333 ;
     RECT  7.815 41.789 8.097 50.389 ;
     RECT  7.815 50.389 8.154 50.429 ;
     RECT  4.32 50.965 4.338 51.005 ;
     RECT  2.415 49.805 2.697 51.331 ;
     RECT  2.415 51.331 2.718 51.431 ;
     RECT  5.115 49.901 5.397 51.511 ;
     RECT  11.88 51.367 11.898 51.539 ;
     RECT  5.115 51.511 5.634 51.581 ;
     RECT  2.415 51.431 2.697 51.979 ;
     RECT  20.52 49.711 20.538 52.013 ;
     RECT  2.304 51.979 2.697 52.043 ;
     RECT  6.3 52.015 6.318 52.061 ;
     RECT  11.952 52.411 11.97 52.541 ;
     RECT  5.115 51.581 5.397 52.981 ;
     RECT  4.392 52.981 5.397 53.021 ;
     RECT  0.108 52.987 0.126 53.117 ;
     RECT  11.628 52.987 11.646 53.117 ;
     RECT  2.415 52.043 2.697 53.611 ;
     RECT  10.515 49.379 10.797 53.797 ;
     RECT  5.115 53.021 5.397 53.941 ;
     RECT  10.515 53.797 11.466 53.969 ;
     RECT  5.115 53.941 5.634 53.981 ;
     RECT  2.304 53.611 2.697 54.365 ;
     RECT  6.84 54.139 6.858 54.365 ;
     RECT  5.115 53.981 5.397 54.715 ;
     RECT  4.5 54.715 5.397 54.905 ;
     RECT  5.115 54.905 5.397 54.985 ;
     RECT  5.115 54.985 5.994 55.037 ;
     RECT  2.415 54.365 2.697 55.291 ;
     RECT  2.304 55.291 2.697 55.561 ;
     RECT  2.304 55.561 3.258 55.613 ;
     RECT  14.724 55.723 14.85 55.853 ;
     RECT  21.492 53.611 21.51 55.853 ;
     RECT  5.115 55.037 5.397 55.915 ;
     RECT  12.06 55.723 12.078 55.949 ;
     RECT  2.304 55.613 2.697 55.985 ;
     RECT  4.5 55.915 5.397 55.985 ;
     RECT  2.415 55.985 2.697 56.335 ;
     RECT  2.415 56.335 2.826 56.381 ;
     RECT  6.3 56.335 6.318 56.381 ;
     RECT  20.52 56.191 20.538 56.381 ;
     RECT  18.615 45.419 18.897 56.911 ;
     RECT  0.108 56.911 0.126 56.957 ;
     RECT  18.615 56.911 18.99 56.957 ;
     RECT  7.815 50.429 8.097 57.019 ;
     RECT  11.736 56.911 11.754 57.029 ;
     RECT  3.996 56.911 4.014 57.065 ;
     RECT  7.815 57.019 8.154 57.065 ;
     RECT  6.84 57.001 6.858 57.173 ;
     RECT  2.415 56.381 2.697 57.451 ;
     RECT  4.248 57.499 4.338 57.569 ;
     RECT  20.484 57.451 20.502 57.569 ;
     RECT  4.248 57.569 4.266 57.749 ;
     RECT  2.34 57.451 2.697 58.027 ;
     RECT  21.492 58.027 21.51 58.109 ;
     RECT  5.115 55.985 5.397 58.117 ;
     RECT  2.304 58.027 2.697 58.145 ;
     RECT  5.115 58.117 5.598 58.157 ;
     RECT  5.115 58.157 5.397 58.219 ;
     RECT  5.076 58.219 5.397 58.415 ;
     RECT  10.515 53.969 10.797 58.531 ;
     RECT  10.515 58.531 11.034 58.649 ;
     RECT  5.115 58.415 5.397 59.179 ;
     RECT  0.108 59.131 0.126 59.225 ;
     RECT  5.115 59.179 5.994 59.225 ;
     RECT  2.415 58.145 2.697 59.275 ;
     RECT  2.415 59.275 3.294 59.659 ;
     RECT  2.412 59.659 3.294 59.809 ;
     RECT  2.412 59.809 3.438 59.837 ;
     RECT  2.412 59.837 2.697 60.235 ;
     RECT  3.42 59.837 3.438 60.419 ;
     RECT  20.484 58.555 20.502 60.809 ;
     RECT  2.304 60.235 2.697 60.845 ;
     RECT  5.115 59.225 5.397 61.339 ;
     RECT  19.944 61.321 19.962 61.373 ;
     RECT  5.115 61.339 5.49 61.385 ;
     RECT  6.84 60.907 6.858 61.565 ;
     RECT  2.415 60.845 2.697 61.867 ;
     RECT  20.52 61.861 20.538 61.901 ;
     RECT  2.304 61.867 2.697 61.925 ;
     RECT  4.284 62.005 4.302 62.045 ;
     RECT  5.115 61.385 5.397 62.395 ;
     RECT  5.115 62.395 5.634 62.435 ;
     RECT  2.415 61.925 2.697 62.437 ;
     RECT  2.415 62.437 2.826 62.477 ;
     RECT  19.944 62.401 19.962 62.477 ;
     RECT  3.6 62.155 4.014 62.699 ;
     RECT  3.996 62.699 4.014 62.968 ;
     RECT  3.996 62.968 4.05 63.005 ;
     RECT  21.492 62.968 21.51 63.005 ;
     RECT  6.84 63.067 6.858 63.113 ;
     RECT  3.996 63.005 4.014 63.245 ;
     RECT  20.52 63.481 20.538 63.581 ;
     RECT  7.815 57.065 8.097 63.625 ;
     RECT  7.815 63.625 8.154 63.677 ;
     RECT  4.32 63.979 4.338 64.049 ;
     RECT  11.988 64.057 12.006 64.229 ;
     RECT  2.415 62.477 2.697 64.597 ;
     RECT  2.415 64.597 2.826 64.637 ;
     RECT  19.944 64.057 19.962 64.637 ;
     RECT  5.115 62.435 5.397 64.741 ;
     RECT  5.115 64.741 5.634 64.781 ;
     RECT  5.115 64.781 5.397 65.131 ;
     RECT  4.68 65.131 5.397 65.171 ;
     RECT  4.068 65.173 4.086 65.213 ;
     RECT  20.52 65.101 20.538 65.741 ;
     RECT  7.815 63.677 8.097 65.785 ;
     RECT  7.815 65.785 8.154 65.837 ;
     RECT  2.415 64.637 2.697 66.325 ;
     RECT  2.415 66.325 3.186 66.365 ;
     RECT  5.115 65.171 5.397 66.715 ;
     RECT  19.944 66.181 19.962 66.845 ;
     RECT  2.415 66.365 2.79 66.857 ;
     RECT  4.68 66.715 5.397 67.387 ;
     RECT  20.484 67.387 20.502 67.595 ;
     RECT  4.248 67.387 5.397 67.709 ;
     RECT  11.988 67.567 12.006 67.739 ;
     RECT  21.492 67.915 21.51 68.099 ;
     RECT  7.056 67.915 7.074 68.135 ;
     RECT  2.415 66.857 2.697 68.251 ;
     RECT  3.996 67.915 4.194 68.251 ;
     RECT  2.415 68.251 4.194 68.369 ;
     RECT  2.415 68.369 4.05 68.405 ;
     RECT  2.415 68.405 3.402 68.491 ;
     RECT  11.736 68.377 11.754 68.525 ;
     RECT  2.34 68.491 3.402 68.639 ;
     RECT  5.115 67.709 5.397 68.971 ;
     RECT  2.34 68.639 2.697 69.019 ;
     RECT  5.115 68.971 5.634 69.179 ;
     RECT  21.492 69.019 21.51 69.179 ;
     RECT  20.484 69.595 20.502 69.719 ;
     RECT  4.176 69.595 4.194 69.755 ;
     RECT  6.84 69.787 6.858 69.863 ;
     RECT  5.115 69.179 5.397 70.123 ;
     RECT  7.815 65.837 8.097 70.219 ;
     RECT  4.464 70.123 5.397 70.295 ;
     RECT  7.815 70.219 8.154 70.295 ;
     RECT  21.492 70.123 21.51 70.799 ;
     RECT  2.304 69.019 2.697 70.951 ;
     RECT  2.304 70.951 3.258 71.021 ;
     RECT  7.815 70.295 8.097 71.077 ;
     RECT  7.092 71.077 8.097 71.117 ;
     RECT  5.115 70.295 5.397 71.221 ;
     RECT  5.115 71.221 5.562 71.275 ;
     RECT  10.515 58.649 10.797 71.311 ;
     RECT  10.515 71.311 10.818 71.411 ;
     RECT  4.932 71.275 5.562 71.707 ;
     RECT  4.608 71.707 5.562 71.837 ;
     RECT  5.115 71.837 5.562 71.851 ;
     RECT  5.115 71.851 5.778 71.915 ;
     RECT  11.556 71.887 11.574 72.059 ;
     RECT  14.724 72.187 14.85 72.317 ;
     RECT  21.492 71.803 21.51 72.365 ;
     RECT  7.815 71.117 8.097 72.379 ;
     RECT  11.664 72.187 11.682 72.419 ;
     RECT  7.815 72.379 8.154 72.455 ;
     RECT  19.944 72.841 19.962 72.941 ;
     RECT  6.84 72.841 6.858 72.959 ;
     RECT  11.988 72.841 12.006 72.959 ;
     RECT  4.284 72.283 4.302 72.995 ;
     RECT  3.42 73.483 3.438 73.535 ;
     RECT  2.304 71.021 2.697 73.997 ;
     RECT  5.115 71.915 5.397 74.011 ;
     RECT  20.484 73.435 20.502 74.039 ;
     RECT  3.996 73.915 4.014 74.075 ;
     RECT  5.115 74.011 5.778 74.587 ;
     RECT  0.108 74.539 0.126 74.615 ;
     RECT  5.115 74.587 5.994 74.624 ;
     RECT  2.415 73.997 2.697 75.067 ;
     RECT  21.492 74.539 21.51 75.119 ;
     RECT  4.284 74.683 4.302 75.197 ;
     RECT  5.115 74.624 5.397 75.595 ;
     RECT  4.536 75.595 5.397 75.659 ;
     RECT  19.944 75.631 19.962 76.205 ;
     RECT  2.304 75.067 2.697 76.235 ;
     RECT  5.115 75.659 5.397 76.315 ;
     RECT  5.115 76.315 5.778 76.397 ;
     RECT  7.056 76.699 7.074 76.747 ;
     RECT  13.215 2.413 13.497 76.747 ;
     RECT  5.115 76.397 5.67 76.784 ;
     RECT  6.84 76.747 7.074 76.883 ;
     RECT  6.84 76.883 6.858 76.919 ;
     RECT  12.636 76.747 13.497 76.919 ;
     RECT  2.415 76.235 2.697 77.275 ;
     RECT  2.412 77.275 2.697 77.315 ;
     RECT  4.32 77.431 4.338 77.501 ;
     RECT  20.52 76.741 20.538 77.885 ;
     RECT  4.068 77.851 4.086 77.891 ;
     RECT  5.115 76.784 5.397 77.971 ;
     RECT  7.815 72.455 8.097 77.971 ;
     RECT  5.115 77.971 5.634 78.029 ;
     RECT  7.164 77.971 8.586 78.029 ;
     RECT  5.115 78.029 5.397 78.331 ;
     RECT  4.356 78.331 5.397 78.413 ;
     RECT  19.944 78.367 19.962 78.413 ;
     RECT  12.204 78.367 12.222 78.539 ;
     RECT  4.68 78.413 5.397 78.653 ;
     RECT  5.115 78.653 5.397 78.907 ;
     RECT  5.115 78.907 5.562 78.989 ;
     RECT  20.52 78.871 20.538 78.989 ;
     RECT  7.815 78.029 8.097 79.015 ;
     RECT  7.815 79.015 8.154 79.229 ;
     RECT  4.32 79.387 4.338 79.411 ;
     RECT  4.14 79.411 4.338 79.439 ;
     RECT  2.415 77.315 2.697 79.477 ;
     RECT  2.415 79.477 2.826 79.517 ;
     RECT  2.415 79.517 2.697 80.059 ;
     RECT  2.304 80.059 2.697 80.123 ;
     RECT  4.14 79.439 4.158 80.381 ;
     RECT  19.944 79.411 19.962 80.621 ;
     RECT  4.356 80.587 4.374 80.663 ;
     RECT  6.768 80.635 6.786 80.671 ;
     RECT  10.515 71.411 10.797 80.671 ;
     RECT  10.515 80.671 11.214 80.789 ;
     RECT  6.768 80.671 6.966 80.957 ;
     RECT  21.492 81.163 21.51 81.329 ;
     RECT  3.996 81.163 4.014 81.365 ;
     RECT  7.056 81.337 7.074 81.389 ;
     RECT  4.14 81.595 4.266 81.635 ;
     RECT  4.14 81.635 4.158 82.253 ;
     RECT  20.52 81.571 20.538 82.253 ;
     RECT  2.415 80.123 2.697 82.795 ;
     RECT  20.484 82.795 20.502 82.949 ;
     RECT  2.304 82.795 2.697 82.985 ;
     RECT  6.84 82.699 6.858 83.605 ;
     RECT  6.84 83.605 7.074 83.633 ;
     RECT  7.056 83.633 7.074 83.645 ;
     RECT  2.415 82.985 2.697 83.899 ;
     RECT  2.304 83.899 2.697 84.001 ;
     RECT  21.492 83.323 21.51 84.029 ;
     RECT  2.304 84.001 2.862 84.065 ;
     RECT  4.284 83.995 4.302 84.065 ;
     RECT  2.415 84.065 2.862 84.209 ;
     RECT  0.54 84.343 0.558 84.461 ;
     RECT  11.952 84.271 11.97 84.461 ;
     RECT  21.492 85.003 21.51 85.109 ;
     RECT  6.84 85.225 6.858 85.277 ;
     RECT  20.484 85.531 20.502 85.649 ;
     RECT  0.144 85.003 0.162 85.685 ;
     RECT  7.815 79.229 8.097 85.765 ;
     RECT  7.815 85.765 8.154 85.805 ;
     RECT  2.415 84.209 2.697 86.107 ;
     RECT  4.32 86.155 4.338 86.195 ;
     RECT  21.492 86.107 21.51 86.729 ;
     RECT  2.304 86.107 2.697 86.765 ;
     RECT  5.115 78.989 5.397 86.875 ;
     RECT  20.484 87.211 20.502 87.269 ;
     RECT  5.115 86.875 5.634 87.385 ;
     RECT  5.115 87.385 5.778 87.437 ;
     RECT  0.108 87.211 0.126 87.773 ;
     RECT  21.492 87.643 21.51 87.773 ;
     RECT  6.84 87.781 6.858 87.787 ;
     RECT  3.996 87.643 4.014 87.845 ;
     RECT  6.84 87.787 7.074 87.845 ;
     RECT  6.84 87.845 6.858 87.953 ;
     RECT  2.415 86.765 2.697 88.231 ;
     RECT  5.115 87.437 5.397 88.231 ;
     RECT  2.415 88.231 3.222 88.349 ;
     RECT  4.32 88.231 5.397 88.355 ;
     RECT  2.415 88.349 2.697 88.843 ;
     RECT  20.484 88.312 20.502 88.889 ;
     RECT  4.5 88.355 5.397 88.931 ;
     RECT  2.304 88.843 2.697 89.465 ;
     RECT  4.68 88.931 5.397 89.465 ;
     RECT  7.815 85.805 8.097 89.977 ;
     RECT  19.944 89.401 19.962 89.981 ;
     RECT  7.815 89.977 8.154 90.029 ;
     RECT  4.32 90.475 4.338 90.481 ;
     RECT  2.415 89.465 2.697 90.517 ;
     RECT  20.52 90.481 20.538 90.557 ;
     RECT  4.248 90.481 4.338 90.617 ;
     RECT  2.304 90.517 2.697 91.085 ;
     RECT  5.115 89.465 5.397 91.147 ;
     RECT  4.5 91.147 5.397 91.193 ;
     RECT  19.944 91.021 19.962 91.613 ;
     RECT  4.032 91.579 4.05 91.625 ;
     RECT  6.84 91.705 6.858 91.757 ;
     RECT  10.515 80.789 10.797 92.137 ;
     RECT  7.815 90.029 8.097 92.281 ;
     RECT  7.416 92.281 8.097 92.399 ;
     RECT  10.515 92.137 10.818 92.399 ;
     RECT  7.815 92.399 8.097 92.515 ;
     RECT  4.32 92.635 4.338 92.675 ;
     RECT  7.815 92.515 8.19 92.717 ;
     RECT  5.115 91.193 5.397 93.361 ;
     RECT  4.536 93.361 5.397 93.437 ;
     RECT  3.996 93.757 4.014 93.821 ;
     RECT  20.52 92.101 20.538 93.821 ;
     RECT  7.815 92.717 8.097 94.027 ;
     RECT  6.84 93.757 6.858 94.061 ;
     RECT  5.115 93.437 5.397 94.363 ;
     RECT  4.464 94.363 5.397 94.433 ;
     RECT  7.596 94.027 8.097 94.445 ;
     RECT  2.415 91.085 2.697 94.891 ;
     RECT  19.944 94.261 19.962 94.925 ;
     RECT  4.248 94.945 4.266 95.021 ;
     RECT  5.115 94.433 5.397 95.179 ;
     RECT  2.304 94.891 2.697 95.513 ;
     RECT  2.415 95.513 2.697 95.521 ;
     RECT  5.115 95.179 5.49 95.521 ;
     RECT  5.115 95.521 5.814 95.597 ;
     RECT  2.415 95.521 3.258 95.639 ;
     RECT  9.108 95.521 9.126 95.639 ;
     RECT  20.52 95.341 20.538 96.029 ;
     RECT  3.996 95.995 4.014 96.053 ;
     RECT  7.815 94.445 8.097 96.715 ;
     RECT  21.492 96.571 21.51 96.719 ;
     RECT  7.815 96.715 8.154 96.755 ;
     RECT  20.52 96.961 20.538 97.133 ;
     RECT  2.415 95.639 2.697 97.141 ;
     RECT  2.415 97.141 3.366 97.435 ;
     RECT  2.415 97.435 3.474 97.675 ;
     RECT  10.515 92.399 10.797 97.807 ;
     RECT  21.492 97.675 21.51 97.835 ;
     RECT  2.304 97.675 3.474 97.979 ;
     RECT  10.515 97.807 11.466 97.979 ;
     RECT  3.456 97.979 3.474 97.997 ;
     RECT  20.484 98.203 20.502 98.339 ;
     RECT  5.115 95.597 5.397 98.341 ;
     RECT  2.304 97.979 2.697 98.375 ;
     RECT  4.68 98.341 5.397 98.381 ;
     RECT  5.115 98.381 5.397 98.635 ;
     RECT  21.492 98.779 21.51 98.879 ;
     RECT  0.108 98.779 0.126 98.915 ;
     RECT  5.115 98.635 5.994 98.915 ;
     RECT  2.415 98.375 2.697 99.307 ;
     RECT  20.484 99.307 20.502 99.455 ;
     RECT  11.88 99.427 11.898 99.599 ;
     RECT  4.32 99.355 4.338 99.931 ;
     RECT  5.115 98.915 5.397 99.931 ;
     RECT  21.492 99.835 21.51 99.959 ;
     RECT  4.32 99.931 5.397 100.363 ;
     RECT  2.304 99.307 2.697 100.445 ;
     RECT  4.14 100.363 5.397 100.535 ;
     RECT  4.536 100.535 5.397 100.558 ;
     RECT  7.815 96.755 8.097 101.035 ;
     RECT  20.484 100.411 20.502 101.039 ;
     RECT  0.108 100.939 0.126 101.075 ;
     RECT  7.815 101.035 8.154 101.075 ;
     RECT  2.415 100.445 2.697 101.515 ;
     RECT  21.492 101.515 21.51 101.579 ;
     RECT  20.484 102.043 20.502 102.659 ;
     RECT  4.32 101.515 4.338 102.667 ;
     RECT  5.115 100.558 5.397 102.667 ;
     RECT  2.304 101.515 2.697 102.695 ;
     RECT  4.32 102.667 5.397 102.704 ;
     RECT  4.32 102.704 4.338 103.051 ;
     RECT  0.108 103.051 0.126 103.181 ;
     RECT  21.492 103.051 21.51 103.181 ;
     RECT  11.628 103.051 11.646 103.199 ;
     RECT  3.996 103.051 4.338 103.235 ;
     RECT  7.056 103.195 7.074 103.235 ;
     RECT  10.515 97.979 10.797 103.711 ;
     RECT  2.415 102.695 2.697 103.723 ;
     RECT  4.32 103.235 4.338 103.775 ;
     RECT  10.515 103.711 11.106 103.853 ;
     RECT  14.724 103.723 14.85 103.853 ;
     RECT  5.115 102.704 5.397 104.251 ;
     RECT  20.52 104.245 20.538 104.285 ;
     RECT  2.304 103.723 2.697 104.315 ;
     RECT  5.115 104.251 5.598 104.779 ;
     RECT  2.415 104.315 2.697 104.821 ;
     RECT  5.115 104.779 5.778 104.855 ;
     RECT  2.415 104.821 2.826 104.861 ;
     RECT  7.815 101.075 8.097 105.367 ;
     RECT  19.944 104.791 19.962 105.389 ;
     RECT  7.815 105.367 8.154 105.437 ;
     RECT  4.32 105.835 4.338 105.871 ;
     RECT  2.415 104.861 2.697 105.907 ;
     RECT  2.412 105.907 2.697 105.965 ;
     RECT  20.52 105.871 20.538 105.965 ;
     RECT  4.248 105.871 4.338 105.971 ;
     RECT  5.115 104.855 5.397 106.411 ;
     RECT  2.415 105.965 2.697 106.447 ;
     RECT  5.115 106.411 5.598 106.475 ;
     RECT  2.415 106.447 2.826 106.493 ;
     RECT  19.944 106.411 19.962 106.493 ;
     RECT  4.32 105.971 4.338 106.699 ;
     RECT  3.96 106.699 4.338 106.709 ;
     RECT  3.96 106.709 4.014 106.745 ;
     RECT  3.996 106.745 4.014 107.069 ;
     RECT  6.84 107.095 6.858 107.165 ;
     RECT  7.815 105.437 8.097 107.275 ;
     RECT  7.815 107.275 8.154 107.555 ;
     RECT  4.248 107.527 4.266 107.597 ;
     RECT  20.52 106.951 20.538 107.597 ;
     RECT  2.415 106.493 2.697 108.139 ;
     RECT  12.276 108.139 12.294 108.329 ;
     RECT  2.415 108.139 2.862 108.365 ;
     RECT  3.924 108.331 3.942 108.371 ;
     RECT  5.115 106.475 5.397 108.427 ;
     RECT  5.076 108.427 5.397 108.571 ;
     RECT  20.52 108.571 20.538 108.701 ;
     RECT  2.415 108.365 2.754 109.147 ;
     RECT  4.68 108.571 5.397 109.175 ;
     RECT  2.415 109.147 2.826 109.229 ;
     RECT  7.815 107.555 8.097 109.795 ;
     RECT  4.068 109.759 4.086 109.805 ;
     RECT  7.596 109.795 8.097 109.853 ;
     RECT  6.84 109.687 6.858 109.859 ;
     RECT  11.988 109.687 12.006 109.859 ;
     RECT  19.944 109.111 19.962 110.333 ;
     RECT  4.248 110.203 4.266 110.573 ;
     RECT  4.068 110.875 4.086 111.065 ;
     RECT  5.115 109.175 5.397 111.109 ;
     RECT  5.115 111.109 5.598 111.149 ;
     RECT  20.484 110.875 20.502 111.569 ;
     RECT  3.996 111.403 4.014 111.605 ;
     RECT  6.84 111.685 6.858 111.725 ;
     RECT  21.492 111.979 21.51 112.109 ;
     RECT  7.815 109.853 8.097 112.219 ;
     RECT  7.815 112.219 8.154 112.259 ;
     RECT  2.415 109.229 2.697 112.507 ;
     RECT  10.515 103.853 10.797 112.531 ;
     RECT  20.52 112.351 20.538 112.541 ;
     RECT  2.304 112.507 2.697 112.603 ;
     RECT  2.304 112.603 3.258 112.649 ;
     RECT  10.08 112.531 10.797 112.649 ;
     RECT  2.304 112.649 2.862 112.829 ;
     RECT  20.484 113.083 20.502 113.189 ;
     RECT  2.304 112.829 2.697 113.225 ;
     RECT  5.115 111.149 5.397 113.341 ;
     RECT  0.108 113.611 0.126 113.765 ;
     RECT  5.115 113.341 5.634 113.845 ;
     RECT  2.415 113.225 2.697 114.139 ;
     RECT  2.415 114.139 2.79 114.179 ;
     RECT  3.996 114.139 4.014 114.305 ;
     RECT  5.115 113.845 5.994 114.305 ;
     RECT  2.415 114.179 2.697 114.715 ;
     RECT  2.304 114.715 2.697 114.955 ;
     RECT  2.304 114.955 3.258 114.995 ;
     RECT  5.115 114.305 5.397 115.291 ;
     RECT  2.304 114.995 2.697 115.385 ;
     RECT  5.115 115.291 5.634 115.709 ;
     RECT  2.415 115.385 2.697 115.861 ;
     RECT  21.492 113.611 21.51 115.889 ;
     RECT  2.415 115.861 2.79 115.901 ;
     RECT  3.996 115.867 4.014 115.925 ;
     RECT  7.815 112.259 8.097 116.437 ;
     RECT  0.108 116.395 0.126 116.465 ;
     RECT  7.815 116.437 8.154 116.477 ;
     RECT  6.84 115.963 6.858 116.573 ;
     RECT  2.415 115.901 2.697 116.923 ;
     RECT  20.484 116.392 20.502 116.969 ;
     RECT  21.492 117.451 21.51 117.509 ;
     RECT  4.32 116.923 4.338 117.965 ;
     RECT  20.52 118.021 20.538 118.061 ;
     RECT  2.304 116.923 2.697 118.085 ;
     RECT  5.115 115.709 5.397 118.165 ;
     RECT  7.815 116.477 8.097 118.411 ;
     RECT  5.115 118.165 5.778 118.541 ;
     RECT  21.492 118.555 21.51 118.595 ;
     RECT  0.108 118.555 0.126 118.625 ;
     RECT  7.815 118.411 8.19 118.733 ;
     RECT  10.515 112.649 10.797 119.011 ;
     RECT  5.115 118.541 5.397 119.083 ;
     RECT  9.972 119.011 10.797 119.101 ;
     RECT  2.415 118.085 2.697 119.128 ;
     RECT  4.176 119.011 4.194 119.129 ;
     RECT  9.972 119.101 11.322 119.129 ;
     RECT  2.415 119.128 2.79 119.131 ;
     RECT  10.515 119.129 11.322 119.165 ;
     RECT  2.415 119.131 3.474 119.693 ;
     RECT  2.415 119.693 2.754 119.705 ;
     RECT  10.515 119.165 10.797 119.911 ;
     RECT  5.004 119.083 5.397 119.947 ;
     RECT  4.932 119.947 5.397 120.209 ;
     RECT  10.515 119.911 10.962 120.209 ;
     RECT  6.84 120.043 6.858 120.283 ;
     RECT  6.732 120.283 6.858 120.451 ;
     RECT  6.732 120.451 7.074 120.479 ;
     RECT  3.996 120.235 4.014 120.797 ;
     RECT  6.984 120.479 7.074 120.808 ;
     RECT  6.984 120.808 7.002 120.893 ;
     RECT  2.415 119.705 2.697 121.297 ;
     RECT  2.412 121.297 2.697 121.373 ;
     RECT  4.284 121.369 4.302 121.421 ;
     RECT  20.52 119.641 20.538 121.901 ;
     RECT  5.115 120.209 5.397 121.909 ;
     RECT  5.115 121.909 5.598 121.949 ;
     RECT  4.284 122.44 4.302 122.477 ;
     RECT  19.944 122.341 19.962 122.477 ;
     RECT  3.996 122.971 4.014 123.053 ;
     RECT  11.556 122.917 11.574 123.089 ;
     RECT  6.516 122.471 6.534 123.101 ;
     RECT  4.248 123.451 4.266 123.491 ;
     RECT  2.415 121.373 2.697 123.547 ;
     RECT  20.52 122.917 20.538 123.581 ;
     RECT  2.415 123.547 2.754 124.075 ;
     RECT  5.115 121.949 5.397 124.141 ;
     RECT  10.515 120.209 10.797 124.141 ;
     RECT  2.415 124.075 2.862 124.219 ;
     RECT  4.392 124.141 5.397 124.259 ;
     RECT  10.404 124.141 10.797 124.259 ;
     RECT  2.415 124.219 3.438 124.295 ;
     RECT  2.415 124.295 2.697 124.651 ;
     RECT  5.115 124.259 5.397 124.784 ;
     RECT  7.815 118.733 8.097 124.795 ;
     RECT  20.484 124.075 20.502 124.799 ;
     RECT  2.304 124.651 2.697 124.835 ;
     RECT  7.416 124.795 8.097 125.213 ;
     RECT  19.944 125.041 19.962 125.213 ;
     RECT  2.415 124.835 2.697 125.755 ;
     RECT  4.284 125.851 4.302 125.915 ;
     RECT  11.556 125.887 11.574 126.059 ;
     RECT  5.115 124.784 5.778 126.379 ;
     RECT  4.536 126.379 5.778 126.419 ;
     RECT  21.492 125.755 21.51 126.959 ;
     RECT  2.304 125.755 2.697 126.995 ;
     RECT  5.115 126.419 5.778 127.103 ;
     RECT  20.484 127.387 20.502 127.499 ;
     RECT  0.108 127.387 0.126 127.535 ;
     RECT  6.84 127.507 6.858 127.615 ;
     RECT  6.84 127.615 7.074 127.661 ;
     RECT  6.84 127.661 6.858 127.679 ;
     RECT  2.415 126.995 2.697 127.915 ;
     RECT  4.32 127.963 4.338 128.039 ;
     RECT  2.304 127.915 2.697 128.461 ;
     RECT  5.115 127.103 5.397 128.461 ;
     RECT  2.304 128.461 2.826 128.579 ;
     RECT  2.304 128.579 2.697 128.615 ;
     RECT  4.536 128.461 5.397 128.861 ;
     RECT  0.108 129.019 0.126 129.155 ;
     RECT  4.68 128.861 5.397 129.155 ;
     RECT  2.415 128.615 2.697 129.595 ;
     RECT  21.492 127.915 21.51 129.659 ;
     RECT  5.004 129.155 5.397 129.695 ;
     RECT  6.84 129.667 6.858 129.775 ;
     RECT  6.84 129.775 7.074 129.821 ;
     RECT  6.84 129.821 6.858 129.839 ;
     RECT  2.304 129.595 2.697 130.165 ;
     RECT  20.484 130.123 20.502 130.199 ;
     RECT  2.304 130.165 3.258 130.205 ;
     RECT  5.115 129.695 5.397 130.555 ;
     RECT  4.536 130.555 5.397 131.117 ;
     RECT  21.492 130.699 21.51 131.279 ;
     RECT  4.68 131.117 5.397 131.453 ;
     RECT  5.004 131.453 5.397 131.855 ;
     RECT  7.056 131.803 7.074 131.855 ;
     RECT  2.304 130.205 2.697 132.395 ;
     RECT  20.484 131.803 20.502 132.395 ;
     RECT  12.204 131.827 12.222 132.539 ;
     RECT  4.32 132.283 4.338 132.797 ;
     RECT  2.415 132.395 2.697 132.901 ;
     RECT  2.415 132.901 2.826 132.941 ;
     RECT  20.52 132.871 20.538 132.941 ;
     RECT  5.115 131.855 5.397 133.015 ;
     RECT  5.115 133.015 5.598 133.229 ;
     RECT  2.415 132.941 2.697 133.435 ;
     RECT  2.304 133.435 2.697 133.475 ;
     RECT  5.115 133.229 5.397 133.555 ;
     RECT  4.68 133.555 5.397 133.613 ;
     RECT  7.056 133.963 7.074 134.015 ;
     RECT  19.944 133.411 19.962 134.045 ;
     RECT  11.88 133.987 11.898 134.159 ;
     RECT  10.515 124.259 10.797 134.401 ;
     RECT  2.415 133.475 2.697 134.491 ;
     RECT  4.176 134.401 4.194 134.519 ;
     RECT  10.515 134.401 10.998 134.519 ;
     RECT  2.415 134.491 3.258 134.555 ;
     RECT  12.384 134.491 12.402 134.573 ;
     RECT  19.944 135.031 19.962 135.101 ;
     RECT  5.115 133.613 5.397 135.103 ;
     RECT  2.415 134.555 2.79 135.104 ;
     RECT  10.515 134.519 10.797 135.643 ;
     RECT  0.54 135.607 0.558 135.677 ;
     RECT  4.68 135.103 5.397 135.677 ;
     RECT  10.515 135.643 11.43 135.68 ;
     RECT  7.056 136.147 7.074 136.205 ;
     RECT  4.248 136.651 4.266 136.715 ;
     RECT  2.415 135.104 2.697 137.227 ;
     RECT  20.52 136.111 20.538 137.309 ;
     RECT  5.115 135.677 5.397 137.323 ;
     RECT  5.115 137.323 5.598 137.363 ;
     RECT  6.372 137.707 6.39 137.759 ;
     RECT  2.415 137.227 2.826 137.885 ;
     RECT  19.944 137.731 19.962 137.885 ;
     RECT  13.215 76.919 13.497 138.307 ;
     RECT  20.52 138.307 20.538 138.413 ;
     RECT  7.815 125.213 8.097 138.415 ;
     RECT  7.596 138.415 8.097 138.461 ;
     RECT  12.528 138.307 13.497 138.479 ;
     RECT  5.115 137.363 5.397 138.523 ;
     RECT  2.415 137.885 2.697 138.721 ;
     RECT  2.415 138.721 2.826 138.839 ;
     RECT  4.392 138.523 5.397 138.989 ;
     RECT  19.944 138.811 19.962 138.989 ;
     RECT  2.415 138.839 2.697 139.483 ;
     RECT  20.52 139.351 20.538 139.517 ;
     RECT  2.304 139.483 2.697 139.523 ;
     RECT  18.615 56.957 18.897 140.059 ;
     RECT  18.615 140.059 19.386 140.189 ;
     RECT  5.115 138.989 5.397 140.197 ;
     RECT  5.115 140.197 5.778 140.203 ;
     RECT  4.032 140.059 4.05 140.225 ;
     RECT  5.115 140.203 6.282 140.237 ;
     RECT  6.264 140.237 6.282 140.459 ;
     RECT  19.944 140.431 19.962 140.621 ;
     RECT  2.415 139.523 2.697 141.163 ;
     RECT  21.492 141.163 21.51 141.269 ;
     RECT  4.284 141.277 4.302 141.341 ;
     RECT  5.115 140.237 5.397 141.355 ;
     RECT  2.412 141.163 2.697 141.691 ;
     RECT  20.484 141.691 20.502 141.809 ;
     RECT  5.115 141.355 5.526 141.925 ;
     RECT  4.68 141.925 5.526 141.953 ;
     RECT  18.615 140.189 18.897 142.267 ;
     RECT  2.304 141.691 2.697 142.385 ;
     RECT  4.68 141.953 5.397 142.385 ;
     RECT  18.615 142.267 18.99 142.795 ;
     RECT  18.615 142.795 19.386 142.889 ;
     RECT  0.108 142.795 0.126 142.925 ;
     RECT  7.056 142.507 7.074 142.925 ;
     RECT  2.415 142.385 2.697 143.401 ;
     RECT  4.32 143.083 4.338 143.429 ;
     RECT  21.492 143.371 21.51 143.429 ;
     RECT  2.415 143.401 2.862 143.609 ;
     RECT  2.415 143.609 2.697 144.467 ;
     RECT  5.115 142.385 5.397 144.467 ;
     RECT  7.815 138.461 8.097 144.467 ;
     RECT  10.515 135.68 10.797 144.467 ;
     RECT  13.215 138.479 13.497 144.467 ;
     RECT  15.915 2.413 16.197 144.467 ;
     RECT  18.615 142.889 18.897 144.467 ;
     RECT  2.415 144.467 2.505 144.737 ;
     RECT  5.115 144.467 5.205 144.737 ;
     RECT  7.815 144.467 7.905 144.737 ;
     RECT  10.515 144.467 10.605 144.737 ;
     RECT  13.215 144.467 13.305 144.737 ;
     RECT  15.915 144.467 16.005 144.737 ;
     RECT  18.615 144.467 18.705 144.737 ;
    LAYER M4 ;
     RECT  0.084 2.4 0.137 2.424 ;
     RECT  0.06 2.424 0.137 2.976 ;
     RECT  0.084 2.976 0.137 3 ;
     RECT  0.06 3 0.137 3.504 ;
     RECT  0.084 3.504 0.137 3.528 ;
     RECT  0.06 3.528 0.137 4.08 ;
     RECT  0.084 4.08 0.137 4.104 ;
     RECT  0.06 4.104 0.137 4.608 ;
     RECT  0.084 4.608 0.137 4.632 ;
     RECT  0.06 4.632 0.137 5.184 ;
     RECT  0.084 5.184 0.137 5.208 ;
     RECT  0.06 5.208 0.137 5.712 ;
     RECT  0.084 5.712 0.137 5.736 ;
     RECT  0.06 5.736 0.137 6.288 ;
     RECT  0.084 6.288 0.137 6.312 ;
     RECT  0.06 6.312 0.137 6.816 ;
     RECT  0.084 6.816 0.137 6.84 ;
     RECT  0.06 6.84 0.137 7.392 ;
     RECT  0.084 7.392 0.137 7.416 ;
     RECT  0.06 7.416 0.137 7.92 ;
     RECT  0.084 7.92 0.137 7.944 ;
     RECT  0.06 7.944 0.137 8.496 ;
     RECT  0.084 8.496 0.137 8.52 ;
     RECT  0.06 8.52 0.137 9.024 ;
     RECT  0.084 9.024 0.137 9.048 ;
     RECT  0.06 9.048 0.137 9.6 ;
     RECT  0.084 9.6 0.137 9.624 ;
     RECT  0.06 9.624 0.137 10.128 ;
     RECT  0.084 10.128 0.137 10.152 ;
     RECT  0.06 10.152 0.137 10.704 ;
     RECT  0.084 10.704 0.137 10.728 ;
     RECT  0.06 10.728 0.137 11.232 ;
     RECT  0.084 11.232 0.137 11.256 ;
     RECT  0.06 11.256 0.137 11.76 ;
     RECT  0.084 11.76 0.137 11.784 ;
     RECT  0.06 11.784 0.137 12.336 ;
     RECT  0.084 12.336 0.137 12.36 ;
     RECT  0.06 12.36 0.137 12.864 ;
     RECT  0.084 12.864 0.137 12.888 ;
     RECT  0.06 12.888 0.137 13.44 ;
     RECT  0.084 13.44 0.137 13.464 ;
     RECT  0.06 13.464 0.137 13.968 ;
     RECT  0.084 13.968 0.137 13.992 ;
     RECT  0.06 13.992 0.137 14.544 ;
     RECT  0.084 14.544 0.137 14.568 ;
     RECT  0.06 14.568 0.137 15.072 ;
     RECT  0.084 15.072 0.137 15.096 ;
     RECT  0.06 15.096 0.137 15.648 ;
     RECT  0.084 15.648 0.137 15.672 ;
     RECT  0.06 15.672 0.137 16.176 ;
     RECT  0.084 16.176 0.137 16.2 ;
     RECT  0.06 16.2 0.137 16.752 ;
     RECT  0.084 16.752 0.137 16.776 ;
     RECT  0.06 16.776 0.137 17.28 ;
     RECT  0.084 17.28 0.137 17.304 ;
     RECT  0.06 17.304 0.137 17.856 ;
     RECT  0.084 17.856 0.137 17.88 ;
     RECT  0.06 17.88 0.137 18.384 ;
     RECT  0.084 18.384 0.137 18.408 ;
     RECT  0.06 18.408 0.137 18.96 ;
     RECT  0.084 18.96 0.137 18.984 ;
     RECT  0.06 18.984 0.137 19.488 ;
     RECT  0.084 19.488 0.137 19.512 ;
     RECT  0.06 19.512 0.137 20.016 ;
     RECT  0.084 20.016 0.137 20.04 ;
     RECT  0.06 20.04 0.137 20.592 ;
     RECT  0.084 20.592 0.137 20.616 ;
     RECT  0.06 20.616 0.137 21.12 ;
     RECT  0.084 21.12 0.137 21.144 ;
     RECT  0.06 21.144 0.137 21.696 ;
     RECT  0.084 21.696 0.137 21.72 ;
     RECT  0.06 21.72 0.137 22.224 ;
     RECT  0.084 22.224 0.137 22.248 ;
     RECT  0.06 22.248 0.137 22.8 ;
     RECT  0.084 22.8 0.137 22.824 ;
     RECT  0.06 22.824 0.137 23.328 ;
     RECT  0.084 23.328 0.137 23.352 ;
     RECT  0.06 23.352 0.137 23.904 ;
     RECT  0.084 23.904 0.137 23.928 ;
     RECT  0.06 23.928 0.137 24.432 ;
     RECT  0.084 24.432 0.137 24.456 ;
     RECT  0.06 24.456 0.137 25.008 ;
     RECT  0.084 25.008 0.137 25.032 ;
     RECT  0.06 25.032 0.137 25.536 ;
     RECT  0.084 25.536 0.137 25.56 ;
     RECT  0.06 25.56 0.137 26.112 ;
     RECT  0.084 26.112 0.137 26.136 ;
     RECT  0.06 26.136 0.137 26.64 ;
     RECT  0.084 26.64 0.137 26.664 ;
     RECT  0.06 26.664 0.137 27.216 ;
     RECT  0.084 27.216 0.137 27.24 ;
     RECT  0.06 27.24 0.137 27.744 ;
     RECT  0.084 27.744 0.137 27.768 ;
     RECT  0.06 27.768 0.137 28.32 ;
     RECT  0.084 28.32 0.137 28.344 ;
     RECT  0.06 28.344 0.137 28.848 ;
     RECT  0.084 28.848 0.137 28.872 ;
     RECT  0.06 28.872 0.137 29.376 ;
     RECT  0.084 29.376 0.137 29.4 ;
     RECT  0.06 29.4 0.137 29.952 ;
     RECT  0.084 29.952 0.137 29.976 ;
     RECT  0.06 29.976 0.137 30.48 ;
     RECT  0.084 30.48 0.137 30.504 ;
     RECT  0.06 30.504 0.137 31.056 ;
     RECT  0.084 31.056 0.137 31.08 ;
     RECT  0.06 31.08 0.137 31.584 ;
     RECT  0.084 31.584 0.137 31.608 ;
     RECT  0.06 31.608 0.137 32.16 ;
     RECT  0.084 32.16 0.137 32.184 ;
     RECT  0.06 32.184 0.137 32.688 ;
     RECT  0.084 32.688 0.137 32.712 ;
     RECT  0.06 32.712 0.137 33.264 ;
     RECT  0.084 33.264 0.137 33.288 ;
     RECT  0.06 33.288 0.137 33.792 ;
     RECT  0.084 33.792 0.137 33.816 ;
     RECT  0.06 33.816 0.137 34.368 ;
     RECT  0.084 34.368 0.137 34.392 ;
     RECT  0.06 34.392 0.137 34.896 ;
     RECT  0.084 34.896 0.137 34.92 ;
     RECT  0.06 34.92 0.137 35.472 ;
     RECT  0.084 35.472 0.137 35.496 ;
     RECT  0.06 35.496 0.137 36 ;
     RECT  0.084 36 0.137 36.024 ;
     RECT  0.06 36.024 0.137 36.576 ;
     RECT  0.084 36.576 0.137 36.6 ;
     RECT  0.06 36.6 0.137 37.104 ;
     RECT  0.084 37.104 0.137 37.128 ;
     RECT  0.06 37.128 0.137 37.68 ;
     RECT  0.084 37.68 0.137 37.704 ;
     RECT  0.06 37.704 0.137 38.208 ;
     RECT  0.084 38.208 0.137 38.232 ;
     RECT  0.06 38.232 0.137 38.736 ;
     RECT  0.084 38.736 0.137 38.76 ;
     RECT  0.06 38.76 0.137 39.312 ;
     RECT  0.084 39.312 0.137 39.336 ;
     RECT  0.06 39.336 0.137 39.84 ;
     RECT  0.084 39.84 0.137 39.864 ;
     RECT  0.06 39.864 0.137 40.416 ;
     RECT  0.084 40.416 0.137 40.44 ;
     RECT  0.06 40.44 0.137 40.944 ;
     RECT  0.084 40.944 0.137 40.968 ;
     RECT  0.06 40.968 0.137 41.52 ;
     RECT  0.084 41.52 0.137 41.544 ;
     RECT  0.06 41.544 0.137 42.048 ;
     RECT  0.084 42.048 0.137 42.072 ;
     RECT  0.06 42.072 0.137 42.624 ;
     RECT  0.084 42.624 0.137 42.648 ;
     RECT  0.06 42.648 0.137 43.152 ;
     RECT  0.084 43.152 0.137 43.176 ;
     RECT  0.06 43.176 0.137 43.728 ;
     RECT  0.084 43.728 0.137 43.752 ;
     RECT  0.06 43.752 0.137 44.256 ;
     RECT  0.084 44.256 0.137 44.28 ;
     RECT  0.06 44.28 0.137 44.832 ;
     RECT  0.084 44.832 0.137 44.856 ;
     RECT  0.06 44.856 0.137 45.36 ;
     RECT  0.084 45.36 0.137 45.384 ;
     RECT  0.06 45.384 0.137 45.936 ;
     RECT  0.084 45.936 0.137 45.96 ;
     RECT  0.06 45.96 0.137 46.464 ;
     RECT  0.084 46.464 0.137 46.488 ;
     RECT  0.06 46.488 0.137 46.992 ;
     RECT  0.084 46.992 0.137 47.016 ;
     RECT  0.06 47.016 0.137 47.568 ;
     RECT  0.084 47.568 0.137 47.592 ;
     RECT  0.06 47.592 0.137 48.096 ;
     RECT  0.084 48.096 0.137 48.12 ;
     RECT  0.06 48.12 0.137 48.672 ;
     RECT  0.084 48.672 0.137 48.696 ;
     RECT  0.06 48.696 0.137 49.2 ;
     RECT  0.084 49.2 0.137 49.224 ;
     RECT  0.06 49.224 0.137 49.776 ;
     RECT  0.084 49.776 0.137 49.8 ;
     RECT  0.06 49.8 0.137 50.304 ;
     RECT  0.084 50.304 0.137 50.328 ;
     RECT  0.06 50.328 0.137 50.88 ;
     RECT  0.084 50.88 0.137 50.904 ;
     RECT  0.06 50.904 0.137 51.408 ;
     RECT  0.084 51.408 0.137 51.432 ;
     RECT  0.06 51.432 0.137 51.984 ;
     RECT  0.084 51.984 0.137 52.008 ;
     RECT  0.06 52.008 0.137 52.512 ;
     RECT  0.084 52.512 0.137 52.536 ;
     RECT  0.06 52.536 0.137 53.088 ;
     RECT  0.084 53.088 0.137 53.112 ;
     RECT  0.06 53.112 0.137 53.616 ;
     RECT  0.084 53.616 0.137 53.64 ;
     RECT  0.06 53.64 0.137 54.192 ;
     RECT  0.084 54.192 0.137 54.216 ;
     RECT  0.06 54.216 0.137 54.72 ;
     RECT  0.084 54.72 0.137 54.744 ;
     RECT  0.06 54.744 0.137 55.296 ;
     RECT  0.084 55.296 0.137 55.32 ;
     RECT  0.06 55.32 0.137 55.824 ;
     RECT  0.084 55.824 0.137 55.848 ;
     RECT  0.06 55.848 0.137 56.352 ;
     RECT  0.084 56.352 0.137 56.376 ;
     RECT  0.06 56.376 0.137 56.928 ;
     RECT  0.084 56.928 0.137 56.952 ;
     RECT  0.06 56.952 0.137 57.456 ;
     RECT  0.084 57.456 0.137 57.48 ;
     RECT  0.06 57.48 0.137 58.032 ;
     RECT  0.084 58.032 0.137 58.056 ;
     RECT  0.06 58.056 0.137 58.56 ;
     RECT  0.084 58.56 0.137 58.584 ;
     RECT  0.06 58.584 0.137 59.136 ;
     RECT  0.084 59.136 0.137 59.16 ;
     RECT  0.06 59.16 0.137 59.664 ;
     RECT  0.084 59.664 0.137 59.688 ;
     RECT  0.06 59.688 0.137 60.24 ;
     RECT  0.084 60.24 0.137 60.264 ;
     RECT  0.06 60.264 0.137 60.768 ;
     RECT  0.084 60.768 0.137 60.792 ;
     RECT  0.06 60.792 0.137 61.344 ;
     RECT  0.084 61.344 0.137 61.368 ;
     RECT  0.06 61.368 0.137 61.872 ;
     RECT  0.084 61.872 0.137 61.896 ;
     RECT  0.06 61.896 0.137 62.448 ;
     RECT  0.084 62.448 0.137 62.472 ;
     RECT  0.06 62.472 0.137 62.976 ;
     RECT  0.084 62.976 0.137 63 ;
     RECT  0.06 63 0.137 63.552 ;
     RECT  0.084 63.552 0.137 63.576 ;
     RECT  0.06 63.576 0.137 64.08 ;
     RECT  0.084 64.08 0.137 64.104 ;
     RECT  0.06 64.104 0.137 64.608 ;
     RECT  0.084 64.608 0.137 64.632 ;
     RECT  0.06 64.632 0.137 65.184 ;
     RECT  0.084 65.184 0.137 65.208 ;
     RECT  0.06 65.208 0.137 65.712 ;
     RECT  0.084 65.712 0.137 65.736 ;
     RECT  0.06 65.736 0.137 66.288 ;
     RECT  0.084 66.288 0.137 66.312 ;
     RECT  0.06 66.312 0.137 66.816 ;
     RECT  0.084 66.816 0.137 66.84 ;
     RECT  0.06 66.84 0.137 67.392 ;
     RECT  0.084 67.392 0.137 67.416 ;
     RECT  0.06 67.416 0.137 67.92 ;
     RECT  0.084 67.92 0.137 67.944 ;
     RECT  0.06 67.944 0.137 68.496 ;
     RECT  0.084 68.496 0.137 68.52 ;
     RECT  0.06 68.52 0.137 69.024 ;
     RECT  0.084 69.024 0.137 69.048 ;
     RECT  0.06 69.048 0.137 69.6 ;
     RECT  0.084 69.6 0.137 69.624 ;
     RECT  0.06 69.624 0.137 70.128 ;
     RECT  0.084 70.128 0.137 70.152 ;
     RECT  0.06 70.152 0.137 70.704 ;
     RECT  0.084 70.704 0.137 70.728 ;
     RECT  0.06 70.728 0.137 71.232 ;
     RECT  0.084 71.232 0.137 71.256 ;
     RECT  0.06 71.256 0.137 71.808 ;
     RECT  0.084 71.808 0.137 71.832 ;
     RECT  0.06 71.832 0.137 72.336 ;
     RECT  0.084 72.336 0.137 72.36 ;
     RECT  0.06 72.36 0.137 72.912 ;
     RECT  0.084 72.912 0.137 72.936 ;
     RECT  0.06 72.936 0.137 73.44 ;
     RECT  0.084 73.44 0.137 73.464 ;
     RECT  0.06 73.464 0.137 73.968 ;
     RECT  0.084 73.968 0.137 73.992 ;
     RECT  0.06 73.992 0.137 74.544 ;
     RECT  0.084 74.544 0.137 74.568 ;
     RECT  0.06 74.568 0.137 75.072 ;
     RECT  0.084 75.072 0.137 75.096 ;
     RECT  0.06 75.096 0.137 75.648 ;
     RECT  0.084 75.648 0.137 75.672 ;
     RECT  0.06 75.672 0.137 76.176 ;
     RECT  0.084 76.176 0.137 76.2 ;
     RECT  0.06 76.2 0.137 76.752 ;
     RECT  0.084 76.752 0.137 76.776 ;
     RECT  0.06 76.776 0.137 77.28 ;
     RECT  0.084 77.28 0.137 77.304 ;
     RECT  0.06 77.304 0.137 77.856 ;
     RECT  0.084 77.856 0.137 77.88 ;
     RECT  0.06 77.88 0.137 78.384 ;
     RECT  0.084 78.384 0.137 78.408 ;
     RECT  0.06 78.408 0.137 78.96 ;
     RECT  0.084 78.96 0.137 78.984 ;
     RECT  0.06 78.984 0.137 79.488 ;
     RECT  0.084 79.488 0.137 79.512 ;
     RECT  0.06 79.512 0.137 80.064 ;
     RECT  0.084 80.064 0.137 80.088 ;
     RECT  0.06 80.088 0.137 80.592 ;
     RECT  0.084 80.592 0.137 80.616 ;
     RECT  0.06 80.616 0.137 81.168 ;
     RECT  0.084 81.168 0.137 81.192 ;
     RECT  0.06 81.192 0.137 81.696 ;
     RECT  0.084 81.696 0.137 81.72 ;
     RECT  0.06 81.72 0.137 82.224 ;
     RECT  0.084 82.224 0.137 82.248 ;
     RECT  0.06 82.248 0.137 82.8 ;
     RECT  0.084 82.8 0.137 82.824 ;
     RECT  0.06 82.824 0.137 83.328 ;
     RECT  0.084 83.328 0.137 83.352 ;
     RECT  0.06 83.352 0.137 83.904 ;
     RECT  0.084 83.904 0.137 83.928 ;
     RECT  0.06 83.928 0.137 84.432 ;
     RECT  0.084 84.432 0.137 84.456 ;
     RECT  0.06 84.456 0.137 85.008 ;
     RECT  0.084 85.008 0.137 85.032 ;
     RECT  0.06 85.032 0.137 85.536 ;
     RECT  0.084 85.536 0.137 85.56 ;
     RECT  0.06 85.56 0.137 86.112 ;
     RECT  0.084 86.112 0.137 86.136 ;
     RECT  0.06 86.136 0.137 86.64 ;
     RECT  0.084 86.64 0.137 86.664 ;
     RECT  0.06 86.664 0.137 87.216 ;
     RECT  0.084 87.216 0.137 87.24 ;
     RECT  0.06 87.24 0.137 87.744 ;
     RECT  0.084 87.744 0.137 87.768 ;
     RECT  0.06 87.768 0.137 88.32 ;
     RECT  0.084 88.32 0.137 88.344 ;
     RECT  0.06 88.344 0.137 88.848 ;
     RECT  0.084 88.848 0.137 88.872 ;
     RECT  0.06 88.872 0.137 89.424 ;
     RECT  0.084 89.424 0.137 89.448 ;
     RECT  0.06 89.448 0.137 89.952 ;
     RECT  0.084 89.952 0.137 89.976 ;
     RECT  0.06 89.976 0.137 90.528 ;
     RECT  0.084 90.528 0.137 90.552 ;
     RECT  0.06 90.552 0.137 91.056 ;
     RECT  0.084 91.056 0.137 91.08 ;
     RECT  0.06 91.08 0.137 91.584 ;
     RECT  0.084 91.584 0.137 91.608 ;
     RECT  0.06 91.608 0.137 92.16 ;
     RECT  0.084 92.16 0.137 92.184 ;
     RECT  0.06 92.184 0.137 92.688 ;
     RECT  0.084 92.688 0.137 92.712 ;
     RECT  0.06 92.712 0.137 93.264 ;
     RECT  0.084 93.264 0.137 93.288 ;
     RECT  0.06 93.288 0.137 93.792 ;
     RECT  0.084 93.792 0.137 93.816 ;
     RECT  0.06 93.816 0.137 94.368 ;
     RECT  0.084 94.368 0.137 94.392 ;
     RECT  0.06 94.392 0.137 94.896 ;
     RECT  0.084 94.896 0.137 94.92 ;
     RECT  0.06 94.92 0.137 95.472 ;
     RECT  0.084 95.472 0.137 95.496 ;
     RECT  0.06 95.496 0.137 96 ;
     RECT  0.084 96 0.137 96.024 ;
     RECT  0.06 96.024 0.137 96.576 ;
     RECT  0.084 96.576 0.137 96.6 ;
     RECT  0.06 96.6 0.137 97.104 ;
     RECT  0.084 97.104 0.137 97.128 ;
     RECT  0.06 97.128 0.137 97.68 ;
     RECT  0.084 97.68 0.137 97.704 ;
     RECT  0.06 97.704 0.137 98.208 ;
     RECT  0.084 98.208 0.137 98.232 ;
     RECT  0.06 98.232 0.137 98.784 ;
     RECT  0.084 98.784 0.137 98.808 ;
     RECT  0.06 98.808 0.137 99.312 ;
     RECT  0.084 99.312 0.137 99.336 ;
     RECT  0.06 99.336 0.137 99.84 ;
     RECT  0.084 99.84 0.137 99.864 ;
     RECT  0.06 99.864 0.137 100.416 ;
     RECT  0.084 100.416 0.137 100.44 ;
     RECT  0.06 100.44 0.137 100.944 ;
     RECT  0.084 100.944 0.137 100.968 ;
     RECT  0.06 100.968 0.137 101.52 ;
     RECT  0.084 101.52 0.137 101.544 ;
     RECT  0.06 101.544 0.137 102.048 ;
     RECT  0.084 102.048 0.137 102.072 ;
     RECT  0.06 102.072 0.137 102.624 ;
     RECT  0.084 102.624 0.137 102.648 ;
     RECT  0.06 102.648 0.137 103.152 ;
     RECT  0.084 103.152 0.137 103.176 ;
     RECT  0.06 103.176 0.137 103.728 ;
     RECT  0.084 103.728 0.137 103.752 ;
     RECT  0.06 103.752 0.137 104.256 ;
     RECT  0.084 104.256 0.137 104.28 ;
     RECT  0.06 104.28 0.137 104.832 ;
     RECT  0.084 104.832 0.137 104.856 ;
     RECT  0.06 104.856 0.137 105.36 ;
     RECT  0.084 105.36 0.137 105.384 ;
     RECT  0.06 105.384 0.137 105.936 ;
     RECT  0.084 105.936 0.137 105.96 ;
     RECT  0.06 105.96 0.137 106.464 ;
     RECT  0.084 106.464 0.137 106.488 ;
     RECT  0.06 106.488 0.137 107.04 ;
     RECT  0.084 107.04 0.137 107.064 ;
     RECT  0.06 107.064 0.137 107.568 ;
     RECT  0.084 107.568 0.137 107.592 ;
     RECT  0.06 107.592 0.137 108.144 ;
     RECT  0.084 108.144 0.137 108.168 ;
     RECT  0.06 108.168 0.137 108.672 ;
     RECT  0.084 108.672 0.137 108.696 ;
     RECT  0.06 108.696 0.137 109.2 ;
     RECT  0.084 109.2 0.137 109.224 ;
     RECT  0.06 109.224 0.137 109.776 ;
     RECT  0.084 109.776 0.137 109.8 ;
     RECT  0.06 109.8 0.137 110.304 ;
     RECT  0.084 110.304 0.137 110.328 ;
     RECT  0.06 110.328 0.137 110.88 ;
     RECT  0.084 110.88 0.137 110.904 ;
     RECT  0.06 110.904 0.137 111.408 ;
     RECT  0.084 111.408 0.137 111.432 ;
     RECT  0.06 111.432 0.137 111.984 ;
     RECT  0.084 111.984 0.137 112.008 ;
     RECT  0.06 112.008 0.137 112.512 ;
     RECT  0.084 112.512 0.137 112.536 ;
     RECT  0.06 112.536 0.137 113.088 ;
     RECT  0.084 113.088 0.137 113.112 ;
     RECT  0.06 113.112 0.137 113.616 ;
     RECT  0.084 113.616 0.137 113.64 ;
     RECT  0.06 113.64 0.137 114.192 ;
     RECT  0.084 114.192 0.137 114.216 ;
     RECT  0.06 114.216 0.137 114.72 ;
     RECT  0.084 114.72 0.137 114.744 ;
     RECT  0.06 114.744 0.137 115.296 ;
     RECT  0.084 115.296 0.137 115.32 ;
     RECT  0.06 115.32 0.137 115.824 ;
     RECT  0.084 115.824 0.137 115.848 ;
     RECT  0.06 115.848 0.137 116.4 ;
     RECT  0.084 116.4 0.137 116.424 ;
     RECT  0.06 116.424 0.137 116.928 ;
     RECT  0.084 116.928 0.137 116.952 ;
     RECT  0.06 116.952 0.137 117.456 ;
     RECT  0.084 117.456 0.137 117.48 ;
     RECT  0.06 117.48 0.137 118.032 ;
     RECT  0.084 118.032 0.137 118.056 ;
     RECT  0.06 118.056 0.137 118.56 ;
     RECT  0.084 118.56 0.137 118.584 ;
     RECT  0.06 118.584 0.137 119.136 ;
     RECT  0.084 119.136 0.137 119.16 ;
     RECT  0.06 119.16 0.137 119.664 ;
     RECT  0.084 119.664 0.137 119.688 ;
     RECT  0.06 119.688 0.137 120.24 ;
     RECT  0.084 120.24 0.137 120.264 ;
     RECT  0.06 120.264 0.137 120.768 ;
     RECT  0.084 120.768 0.137 120.792 ;
     RECT  0.06 120.792 0.137 121.344 ;
     RECT  0.084 121.344 0.137 121.368 ;
     RECT  0.06 121.368 0.137 121.872 ;
     RECT  0.084 121.872 0.137 121.896 ;
     RECT  0.06 121.896 0.137 122.448 ;
     RECT  0.084 122.448 0.137 122.472 ;
     RECT  0.06 122.472 0.137 122.976 ;
     RECT  0.084 122.976 0.137 123 ;
     RECT  0.06 123 0.137 123.552 ;
     RECT  0.084 123.552 0.137 123.576 ;
     RECT  0.06 123.576 0.137 124.08 ;
     RECT  0.084 124.08 0.137 124.104 ;
     RECT  0.06 124.104 0.137 124.656 ;
     RECT  0.084 124.656 0.137 124.68 ;
     RECT  0.06 124.68 0.137 125.184 ;
     RECT  0.084 125.184 0.137 125.208 ;
     RECT  0.06 125.208 0.137 125.76 ;
     RECT  0.084 125.76 0.137 125.784 ;
     RECT  0.06 125.784 0.137 126.288 ;
     RECT  0.084 126.288 0.137 126.312 ;
     RECT  0.06 126.312 0.137 126.816 ;
     RECT  0.084 126.816 0.137 126.84 ;
     RECT  0.06 126.84 0.137 127.392 ;
     RECT  0.084 127.392 0.137 127.416 ;
     RECT  0.06 127.416 0.137 127.92 ;
     RECT  0.084 127.92 0.137 127.944 ;
     RECT  0.06 127.944 0.137 128.496 ;
     RECT  0.084 128.496 0.137 128.52 ;
     RECT  0.06 128.52 0.137 129.024 ;
     RECT  0.084 129.024 0.137 129.048 ;
     RECT  0.06 129.048 0.137 129.6 ;
     RECT  0.084 129.6 0.137 129.624 ;
     RECT  0.06 129.624 0.137 130.128 ;
     RECT  0.084 130.128 0.137 130.152 ;
     RECT  0.06 130.152 0.137 130.704 ;
     RECT  0.084 130.704 0.137 130.728 ;
     RECT  0.06 130.728 0.137 131.232 ;
     RECT  0.084 131.232 0.137 131.256 ;
     RECT  0.06 131.256 0.137 131.808 ;
     RECT  0.084 131.808 0.137 131.832 ;
     RECT  0.06 131.832 0.137 132.336 ;
     RECT  0.084 132.336 0.137 132.36 ;
     RECT  0.06 132.36 0.137 132.912 ;
     RECT  0.084 132.912 0.137 132.936 ;
     RECT  0.06 132.936 0.137 133.44 ;
     RECT  0.084 133.44 0.137 133.464 ;
     RECT  0.06 133.464 0.137 134.016 ;
     RECT  0.084 134.016 0.137 134.04 ;
     RECT  0.06 134.04 0.137 134.544 ;
     RECT  0.084 134.544 0.137 134.568 ;
     RECT  0.06 134.568 0.137 135.072 ;
     RECT  0.084 135.072 0.137 135.096 ;
     RECT  0.06 135.096 0.137 135.648 ;
     RECT  0.084 135.648 0.137 135.672 ;
     RECT  0.06 135.672 0.137 136.176 ;
     RECT  0.084 136.176 0.137 136.2 ;
     RECT  0.06 136.2 0.137 136.752 ;
     RECT  0.084 136.752 0.137 136.776 ;
     RECT  0.06 136.776 0.137 137.28 ;
     RECT  0.084 137.28 0.137 137.304 ;
     RECT  0.06 137.304 0.137 137.856 ;
     RECT  0.084 137.856 0.137 137.88 ;
     RECT  0.06 137.88 0.137 138.384 ;
     RECT  0.084 138.384 0.137 138.408 ;
     RECT  0.06 138.408 0.137 138.96 ;
     RECT  0.084 138.96 0.137 138.984 ;
     RECT  0.06 138.984 0.137 139.488 ;
     RECT  0.084 139.488 0.137 139.512 ;
     RECT  0.06 139.512 0.137 140.064 ;
     RECT  0.084 140.064 0.137 140.088 ;
     RECT  0.06 140.088 0.137 140.592 ;
     RECT  0.084 140.592 0.137 140.616 ;
     RECT  0.06 140.616 0.137 141.168 ;
     RECT  0.084 141.168 0.137 141.192 ;
     RECT  0.06 141.192 0.137 141.696 ;
     RECT  0.084 141.696 0.137 141.72 ;
     RECT  0.06 141.72 0.137 142.272 ;
     RECT  0.084 142.272 0.137 142.296 ;
     RECT  0.06 142.296 0.137 142.8 ;
     RECT  0.084 142.8 0.137 142.824 ;
     RECT  0.06 142.824 0.137 143.376 ;
     RECT  0.084 143.376 0.137 143.4 ;
     RECT  0.137 75.072 0.173 86.664 ;
     RECT  0.173 75.072 0.569 84.456 ;
     RECT  0.137 129.6 0.569 142.296 ;
     RECT  0.137 2.4 2.408 3.528 ;
     RECT  0.137 4.608 2.408 14.568 ;
     RECT  0.137 15.648 2.408 21.72 ;
     RECT  0.137 23.328 2.408 27.768 ;
     RECT  0.137 28.848 2.408 29.976 ;
     RECT  0.137 31.056 2.408 31.608 ;
     RECT  0.137 33.264 2.408 37.128 ;
     RECT  0.137 38.208 2.408 42.648 ;
     RECT  0.137 43.728 2.408 52.536 ;
     RECT  0.137 53.616 2.408 56.376 ;
     RECT  0.137 57.456 2.408 58.584 ;
     RECT  0.137 59.664 2.408 73.992 ;
     RECT  0.569 75.072 2.408 83.928 ;
     RECT  0.173 86.112 2.408 86.664 ;
     RECT  0.137 87.648 2.408 98.232 ;
     RECT  0.137 99.312 2.408 100.44 ;
     RECT  0.137 101.52 2.408 113.112 ;
     RECT  0.137 114.192 2.408 115.848 ;
     RECT  0.137 116.928 2.408 118.056 ;
     RECT  0.137 119.136 2.408 126.84 ;
     RECT  0.137 127.92 2.408 128.52 ;
     RECT  0.569 129.6 2.408 135.096 ;
     RECT  0.569 136.176 2.408 142.296 ;
     RECT  0.137 143.376 2.408 143.4 ;
     RECT  2.408 2.148 2.512 144.732 ;
     RECT  2.512 2.418 2.704 144.462 ;
     RECT  2.704 47.568 2.765 50.328 ;
     RECT  2.704 106.464 2.765 109.8 ;
     RECT  2.704 122.448 2.765 125.88 ;
     RECT  2.704 64.608 2.801 68.376 ;
     RECT  2.704 134.016 2.801 135.096 ;
     RECT  2.704 7.92 2.837 9.048 ;
     RECT  2.704 25.536 2.837 26.136 ;
     RECT  2.704 38.736 2.837 42.168 ;
     RECT  2.704 54.72 2.837 56.376 ;
     RECT  2.801 64.608 2.837 66.36 ;
     RECT  2.704 77.856 2.837 79.512 ;
     RECT  2.704 104.832 2.837 105.384 ;
     RECT  2.765 106.464 2.837 108.168 ;
     RECT  2.765 109.2 2.837 109.8 ;
     RECT  2.704 132.912 2.837 132.936 ;
     RECT  2.704 137.28 2.837 138.408 ;
     RECT  2.837 40.944 2.873 42.168 ;
     RECT  2.837 107.04 2.873 108.168 ;
     RECT  2.765 124.08 2.873 125.88 ;
     RECT  2.837 65.184 3.203 66.36 ;
     RECT  2.837 54.72 3.299 55.608 ;
     RECT  2.704 69.6 3.299 71.016 ;
     RECT  2.704 114.144 3.299 115.896 ;
     RECT  2.704 59.28 3.305 59.304 ;
     RECT  2.765 49.344 3.449 50.328 ;
     RECT  2.704 96 3.485 97.992 ;
     RECT  2.704 119.136 3.485 120.792 ;
     RECT  2.704 11.952 3.491 14.232 ;
     RECT  2.873 41.52 3.491 42.168 ;
     RECT  2.873 124.224 3.491 125.88 ;
     RECT  2.704 43.68 3.529 45.96 ;
     RECT  2.704 34.368 3.683 37.608 ;
     RECT  3.491 41.52 3.683 41.64 ;
     RECT  2.873 107.04 3.913 107.592 ;
     RECT  3.913 107.04 3.949 108.36 ;
     RECT  3.491 11.952 3.989 13.656 ;
     RECT  2.704 10.704 4.025 10.728 ;
     RECT  3.989 12.336 4.025 13.656 ;
     RECT  2.704 19.488 4.025 21.72 ;
     RECT  2.704 23.328 4.025 23.928 ;
     RECT  2.837 26.112 4.025 26.136 ;
     RECT  3.683 41.52 4.025 41.544 ;
     RECT  3.529 45.408 4.025 45.96 ;
     RECT  3.449 49.872 4.025 50.328 ;
     RECT  2.704 72.288 4.025 73.944 ;
     RECT  2.704 80.592 4.025 81.192 ;
     RECT  2.704 87.648 4.025 87.672 ;
     RECT  3.485 96 4.025 96.6 ;
     RECT  2.704 103.056 4.025 103.08 ;
     RECT  2.704 110.88 4.025 112.632 ;
     RECT  3.299 114.144 4.025 114.168 ;
     RECT  3.299 115.872 4.025 115.896 ;
     RECT  3.485 119.568 4.025 120.792 ;
     RECT  2.765 122.448 4.025 123 ;
     RECT  2.837 7.92 4.061 8.52 ;
     RECT  2.801 67.392 4.061 68.376 ;
     RECT  2.704 91.584 4.061 92.184 ;
     RECT  2.704 140.064 4.061 140.616 ;
     RECT  2.837 109.776 4.097 109.8 ;
     RECT  4.025 110.88 4.097 110.904 ;
     RECT  4.025 21.696 4.129 21.72 ;
     RECT  4.025 80.592 4.129 80.616 ;
     RECT  2.704 83.328 4.165 83.352 ;
     RECT  4.129 82.224 4.213 82.248 ;
     RECT  2.704 136.176 4.22 136.2 ;
     RECT  4.061 8.496 4.237 8.52 ;
     RECT  4.025 23.904 4.237 23.928 ;
     RECT  2.704 93.792 4.237 94.392 ;
     RECT  2.765 47.568 4.248 48.12 ;
     RECT  2.704 131.808 4.261 131.832 ;
     RECT  2.837 138.384 4.261 138.408 ;
     RECT  2.704 5.712 4.268 6.312 ;
     RECT  2.704 17.328 4.268 17.352 ;
     RECT  4.248 47.184 4.268 48.12 ;
     RECT  4.229 74.688 4.268 74.712 ;
     RECT  2.704 76.752 4.268 76.776 ;
     RECT  2.837 77.856 4.268 78.984 ;
     RECT  4.129 80.352 4.268 80.616 ;
     RECT  2.704 89.952 4.268 89.976 ;
     RECT  4.061 92.16 4.268 92.184 ;
     RECT  2.837 105.36 4.268 105.384 ;
     RECT  3.949 106.704 4.268 108.36 ;
     RECT  4.061 140.592 4.268 140.616 ;
     RECT  2.704 15.696 4.273 15.72 ;
     RECT  4.268 17.328 4.273 17.832 ;
     RECT  2.704 2.688 4.309 2.712 ;
     RECT  4.268 5.712 4.309 6.792 ;
     RECT  3.683 34.368 4.309 35.592 ;
     RECT  4.025 45.936 4.309 45.96 ;
     RECT  4.268 47.184 4.309 48.84 ;
     RECT  2.704 60.384 4.309 63.576 ;
     RECT  3.485 97.968 4.309 97.992 ;
     RECT  2.704 100.368 4.309 100.392 ;
     RECT  4.268 101.52 4.309 101.544 ;
     RECT  4.268 121.392 4.309 121.416 ;
     RECT  4.025 122.448 4.309 122.472 ;
     RECT  4.261 138.384 4.309 138.552 ;
     RECT  2.837 38.736 4.381 39.336 ;
     RECT  2.704 52.512 4.381 52.536 ;
     RECT  4.309 57.504 4.453 57.528 ;
     RECT  4.268 88.32 4.46 88.344 ;
     RECT  4.268 89.952 4.46 90.504 ;
     RECT  4.268 127.968 4.461 127.992 ;
     RECT  2.704 129.648 4.461 130.2 ;
     RECT  4.453 42.672 4.481 42.696 ;
     RECT  3.529 43.68 4.481 44.328 ;
     RECT  4.461 127.968 4.481 130.2 ;
     RECT  4.309 33.936 4.489 35.592 ;
     RECT  4.165 83.328 4.501 84.024 ;
     RECT  4.46 88.32 4.501 88.92 ;
     RECT  4.46 89.952 4.501 91.176 ;
     RECT  4.268 92.16 4.501 92.664 ;
     RECT  4.237 93.792 4.501 95.016 ;
     RECT  3.491 125.184 4.501 125.88 ;
     RECT  4.268 74.688 4.525 75.192 ;
     RECT  4.481 127.968 4.525 130.584 ;
     RECT  4.261 131.808 4.525 132.792 ;
     RECT  4.025 72.288 4.597 73.512 ;
     RECT  4.061 67.392 4.625 67.704 ;
     RECT  3.203 65.184 4.645 65.736 ;
     RECT  4.525 127.968 4.652 132.792 ;
     RECT  2.801 134.016 4.652 134.52 ;
     RECT  4.22 136.176 4.652 136.68 ;
     RECT  4.501 31.824 4.669 31.848 ;
     RECT  4.652 127.968 4.669 134.52 ;
     RECT  4.652 135.648 4.669 136.68 ;
     RECT  4.597 71.712 4.693 73.512 ;
     RECT  4.669 127.968 4.693 136.68 ;
     RECT  4.025 119.568 4.981 120.312 ;
     RECT  4.268 105.36 5.065 108.36 ;
     RECT  4.309 2.688 5.108 3.576 ;
     RECT  4.268 4.608 5.108 4.632 ;
     RECT  4.309 5.712 5.108 7.416 ;
     RECT  4.237 8.496 5.108 8.568 ;
     RECT  4.22 9.648 5.108 9.672 ;
     RECT  4.237 10.848 5.108 10.872 ;
     RECT  4.025 12.336 5.108 12.36 ;
     RECT  4.025 13.632 5.108 13.656 ;
     RECT  4.273 15.696 5.108 17.832 ;
     RECT  4.025 19.488 5.108 20.568 ;
     RECT  4.129 21.696 5.108 22.056 ;
     RECT  4.237 23.904 5.108 25.08 ;
     RECT  4.261 26.736 5.108 26.76 ;
     RECT  4.357 27.888 5.108 27.912 ;
     RECT  4.316 29.376 5.108 29.4 ;
     RECT  4.345 30.816 5.108 30.84 ;
     RECT  4.669 31.824 5.108 32.04 ;
     RECT  4.489 33.072 5.108 35.592 ;
     RECT  3.683 36.576 5.108 37.608 ;
     RECT  4.381 38.736 5.108 39.912 ;
     RECT  4.481 42.672 5.108 44.328 ;
     RECT  4.309 45.936 5.108 48.84 ;
     RECT  4.025 49.872 5.108 49.896 ;
     RECT  4.271 50.976 5.108 51 ;
     RECT  4.381 52.512 5.108 53.016 ;
     RECT  3.299 54.72 5.108 54.744 ;
     RECT  4.453 55.92 5.108 55.944 ;
     RECT  4.453 57.504 5.108 58.248 ;
     RECT  4.309 60.384 5.108 64.008 ;
     RECT  4.645 65.136 5.108 65.736 ;
     RECT  4.625 66.72 5.108 67.704 ;
     RECT  3.299 69.6 5.108 70.152 ;
     RECT  4.693 71.28 5.108 73.512 ;
     RECT  4.525 74.688 5.108 75.624 ;
     RECT  4.268 76.752 5.108 80.616 ;
     RECT  4.213 81.6 5.108 82.248 ;
     RECT  4.501 83.328 5.108 84.36 ;
     RECT  4.165 86.16 5.108 86.184 ;
     RECT  4.501 88.32 5.108 91.176 ;
     RECT  4.501 92.16 5.108 95.016 ;
     RECT  4.025 96.576 5.108 96.6 ;
     RECT  4.309 97.968 5.108 99.384 ;
     RECT  4.309 100.368 5.108 100.536 ;
     RECT  4.309 101.52 5.108 101.64 ;
     RECT  4.669 102.672 5.108 102.696 ;
     RECT  5.065 105.36 5.108 108.456 ;
     RECT  4.237 110.208 5.108 110.568 ;
     RECT  4.025 111.984 5.108 112.632 ;
     RECT  4.309 115.68 5.108 115.704 ;
     RECT  4.268 116.928 5.108 116.952 ;
     RECT  4.309 117.936 5.108 117.96 ;
     RECT  4.981 119.088 5.108 120.312 ;
     RECT  4.309 121.392 5.108 122.472 ;
     RECT  4.237 123.456 5.108 123.48 ;
     RECT  4.501 125.184 5.108 126.408 ;
     RECT  4.693 127.968 5.108 137.352 ;
     RECT  4.309 138.384 5.108 138.984 ;
     RECT  4.268 140.592 5.108 141.336 ;
     RECT  4.309 143.088 5.108 143.112 ;
     RECT  5.108 2.148 5.212 144.732 ;
     RECT  5.212 2.418 5.404 144.462 ;
     RECT  5.404 61.344 5.501 62.424 ;
     RECT  5.404 9.696 5.555 10.2 ;
     RECT  5.404 102.672 5.555 102.696 ;
     RECT  5.404 139.488 5.555 141.384 ;
     RECT  5.404 78 5.573 78.984 ;
     RECT  5.404 124.8 5.573 125.208 ;
     RECT  5.555 140.208 5.581 141.384 ;
     RECT  5.404 95.184 5.603 96.216 ;
     RECT  5.404 104.256 5.609 104.808 ;
     RECT  5.404 121.92 5.609 121.944 ;
     RECT  5.404 133.2 5.609 133.224 ;
     RECT  5.404 137.328 5.609 137.736 ;
     RECT  5.404 115.296 5.645 115.704 ;
     RECT  5.404 18.384 5.651 18.984 ;
     RECT  5.404 22.032 5.651 22.728 ;
     RECT  5.404 36.528 5.651 36.552 ;
     RECT  5.404 38.352 5.651 38.376 ;
     RECT  5.404 40.416 5.651 40.44 ;
     RECT  5.404 108.432 5.651 108.456 ;
     RECT  5.404 111.12 5.651 111.144 ;
     RECT  5.404 113.376 5.651 114.024 ;
     RECT  5.645 115.296 5.651 115.32 ;
     RECT  5.404 106.416 5.673 107.16 ;
     RECT  5.404 76.368 5.681 76.776 ;
     RECT  5.651 22.032 5.699 22.056 ;
     RECT  5.404 46.08 5.699 47.304 ;
     RECT  5.501 62.16 5.699 62.424 ;
     RECT  5.404 64.752 5.699 64.776 ;
     RECT  5.404 68.976 5.699 69 ;
     RECT  5.404 86.88 5.699 87.432 ;
     RECT  5.603 95.568 5.699 96.216 ;
     RECT  5.404 33.936 5.717 34.344 ;
     RECT  5.404 27.264 5.747 27.288 ;
     RECT  5.651 18.96 5.789 18.984 ;
     RECT  5.404 3.216 5.795 3.24 ;
     RECT  5.404 5.376 5.795 5.88 ;
     RECT  5.555 9.696 5.795 9.72 ;
     RECT  5.404 14.64 5.795 14.664 ;
     RECT  5.404 16.8 5.795 16.824 ;
     RECT  5.404 74.016 5.795 74.616 ;
     RECT  5.699 87.408 5.795 87.432 ;
     RECT  5.681 76.368 5.833 76.728 ;
     RECT  5.699 95.568 5.843 95.592 ;
     RECT  5.673 106.704 5.843 107.16 ;
     RECT  5.404 4.272 6.005 4.296 ;
     RECT  5.404 13.008 6.005 13.032 ;
     RECT  5.404 32.016 6.035 32.04 ;
     RECT  5.404 43.296 6.035 43.32 ;
     RECT  5.699 46.08 6.035 46.104 ;
     RECT  5.404 51.552 6.035 52.056 ;
     RECT  5.404 53.952 6.035 53.976 ;
     RECT  5.404 55.008 6.035 55.032 ;
     RECT  5.404 58.128 6.035 58.152 ;
     RECT  5.404 59.184 6.035 59.208 ;
     RECT  5.699 62.4 6.035 62.424 ;
     RECT  5.717 33.936 6.041 34.056 ;
     RECT  5.404 30.576 6.069 30.6 ;
     RECT  5.795 74.592 6.083 74.616 ;
     RECT  5.404 98.64 6.083 98.664 ;
     RECT  5.609 104.784 6.083 104.808 ;
     RECT  5.581 140.208 6.293 140.424 ;
     RECT  5.404 25.44 6.329 25.464 ;
     RECT  6.035 52.032 6.329 52.056 ;
     RECT  5.404 120.288 6.517 120.312 ;
     RECT  5.609 137.712 6.517 137.736 ;
     RECT  6.476 122.496 6.563 123.096 ;
     RECT  6.293 140.4 6.563 140.424 ;
     RECT  6.577 23.808 6.829 23.832 ;
     RECT  6.041 34.032 6.829 34.056 ;
     RECT  6.517 120.288 6.829 120.792 ;
     RECT  6.757 80.64 6.853 80.952 ;
     RECT  6.829 111.696 6.853 111.72 ;
     RECT  6.829 115.968 6.853 115.992 ;
     RECT  6.829 82.704 7.004 82.728 ;
     RECT  5.404 127.056 7.004 127.08 ;
     RECT  6.829 7.968 7.045 7.992 ;
     RECT  6.829 41.568 7.045 41.592 ;
     RECT  5.833 76.704 7.045 76.728 ;
     RECT  6.829 85.248 7.045 85.272 ;
     RECT  5.404 118.512 7.093 118.536 ;
     RECT  6.829 94.032 7.585 94.056 ;
     RECT  6.829 91.728 7.669 91.752 ;
     RECT  7.045 7.968 7.808 8.472 ;
     RECT  6.853 10.992 7.808 11.016 ;
     RECT  6.829 12.528 7.808 12.552 ;
     RECT  6.853 15.312 7.808 15.336 ;
     RECT  6.853 19.872 7.808 19.896 ;
     RECT  6.829 21.12 7.808 21.144 ;
     RECT  6.829 23.328 7.808 23.832 ;
     RECT  6.981 26.544 7.808 26.568 ;
     RECT  6.829 30.048 7.808 30.072 ;
     RECT  6.829 34.032 7.808 34.776 ;
     RECT  6.853 37.056 7.808 37.08 ;
     RECT  6.853 39.6 7.808 39.624 ;
     RECT  7.045 41.568 7.808 41.784 ;
     RECT  6.853 43.824 7.808 43.848 ;
     RECT  6.829 45.552 7.808 45.576 ;
     RECT  6.853 48.24 7.808 48.264 ;
     RECT  6.829 54.144 7.808 54.168 ;
     RECT  5.404 56.352 7.808 56.376 ;
     RECT  6.829 60.912 7.808 61.56 ;
     RECT  6.829 63.072 7.808 63.096 ;
     RECT  7.045 67.92 7.808 67.944 ;
     RECT  6.829 69.792 7.808 69.816 ;
     RECT  5.404 71.088 7.808 71.88 ;
     RECT  7.045 76.704 7.808 76.872 ;
     RECT  5.573 78 7.808 78.024 ;
     RECT  6.853 80.64 7.808 81.384 ;
     RECT  7.004 82.704 7.808 83.64 ;
     RECT  7.045 85.248 7.808 85.8 ;
     RECT  7.004 87.792 7.808 87.816 ;
     RECT  7.381 90 7.808 90.024 ;
     RECT  7.669 91.728 7.808 92.712 ;
     RECT  7.585 94.032 7.808 94.44 ;
     RECT  7.045 103.2 7.808 103.224 ;
     RECT  5.843 107.136 7.808 107.16 ;
     RECT  7.429 109.824 7.808 109.848 ;
     RECT  6.853 111.696 7.808 112.248 ;
     RECT  5.651 114 7.808 114.024 ;
     RECT  6.853 115.968 7.808 116.472 ;
     RECT  7.093 118.416 7.808 118.536 ;
     RECT  6.829 120.048 7.808 120.792 ;
     RECT  5.573 124.8 7.808 124.824 ;
     RECT  7.004 127.056 7.808 127.656 ;
     RECT  7.004 129.792 7.808 129.816 ;
     RECT  7.004 131.808 7.808 131.832 ;
     RECT  7.004 133.968 7.808 133.992 ;
     RECT  6.805 136.176 7.808 136.2 ;
     RECT  6.517 137.712 7.808 138.456 ;
     RECT  5.404 142.512 7.808 142.536 ;
     RECT  7.808 2.148 7.912 144.732 ;
     RECT  7.912 2.418 8.104 144.462 ;
     RECT  8.104 19.488 8.165 19.896 ;
     RECT  8.104 85.776 8.165 85.8 ;
     RECT  8.104 90 8.165 90.024 ;
     RECT  8.104 112.224 8.165 112.248 ;
     RECT  8.104 116.448 8.165 116.472 ;
     RECT  8.104 92.688 8.201 92.712 ;
     RECT  8.104 118.416 8.201 118.44 ;
     RECT  8.104 15.312 8.243 15.336 ;
     RECT  8.104 17.472 8.243 17.496 ;
     RECT  8.165 19.488 8.243 19.512 ;
     RECT  8.104 26.544 8.243 26.568 ;
     RECT  8.104 28.416 8.243 28.44 ;
     RECT  8.104 30.048 8.243 30.072 ;
     RECT  8.104 32.736 8.243 32.76 ;
     RECT  8.104 34.032 8.243 34.92 ;
     RECT  8.104 41.76 8.243 41.784 ;
     RECT  8.104 50.4 8.243 50.424 ;
     RECT  8.104 52.56 8.243 52.584 ;
     RECT  8.104 57.024 8.243 57.048 ;
     RECT  8.104 63.648 8.243 63.672 ;
     RECT  8.104 65.808 8.243 65.832 ;
     RECT  8.104 67.92 8.243 67.944 ;
     RECT  8.104 70.224 8.243 70.248 ;
     RECT  8.104 72.384 8.243 72.408 ;
     RECT  8.104 80.64 8.243 80.664 ;
     RECT  8.104 94.416 8.243 94.44 ;
     RECT  8.104 96.72 8.243 96.744 ;
     RECT  8.104 101.04 8.243 101.064 ;
     RECT  8.104 103.2 8.243 103.224 ;
     RECT  8.104 105.408 8.243 105.432 ;
     RECT  8.104 107.28 8.243 107.304 ;
     RECT  8.104 76.848 8.531 76.872 ;
     RECT  8.104 79.2 8.531 79.224 ;
     RECT  8.243 34.032 8.597 34.056 ;
     RECT  8.104 78 8.597 78.024 ;
     RECT  10.508 2.148 10.612 144.732 ;
     RECT  10.612 2.418 10.804 144.462 ;
     RECT  5.941 146.736 10.829 146.76 ;
     RECT  10.804 53.088 11.941 53.112 ;
     RECT  10.804 41.424 12.049 41.448 ;
     RECT  10.804 21.696 12.157 22.248 ;
     RECT  10.804 6.288 13.208 6.312 ;
     RECT  10.804 10.704 13.208 10.728 ;
     RECT  12.157 21.696 13.208 22.824 ;
     RECT  12.301 26.112 13.208 26.136 ;
     RECT  10.804 37.104 13.208 37.704 ;
     RECT  10.804 39.312 13.208 39.336 ;
     RECT  12.049 40.944 13.208 41.448 ;
     RECT  11.941 52.512 13.208 53.112 ;
     RECT  12.049 55.728 13.208 55.752 ;
     RECT  10.804 68.496 13.208 68.52 ;
     RECT  10.804 72.192 13.208 72.216 ;
     RECT  11.941 84.432 13.208 84.456 ;
     RECT  10.804 103.056 13.208 103.848 ;
     RECT  12.265 108.144 13.208 108.168 ;
     RECT  10.804 119.136 13.208 119.16 ;
     RECT  12.373 134.544 13.208 134.568 ;
     RECT  10.804 135.648 13.208 135.672 ;
     RECT  13.208 2.148 13.312 144.732 ;
     RECT  13.312 2.418 13.504 144.462 ;
     RECT  13.504 40.944 14.713 41.448 ;
     RECT  13.504 55.728 14.713 55.752 ;
     RECT  13.504 72.192 14.713 72.216 ;
     RECT  14.713 40.944 14.861 41.544 ;
     RECT  14.713 55.728 14.861 55.848 ;
     RECT  14.713 72.192 14.861 72.312 ;
     RECT  13.504 6.288 15.908 6.312 ;
     RECT  13.504 10.704 15.908 10.728 ;
     RECT  13.504 21.696 15.908 22.824 ;
     RECT  13.504 26.112 15.908 26.136 ;
     RECT  13.504 37.104 15.908 37.704 ;
     RECT  13.504 39.312 15.908 39.336 ;
     RECT  14.861 40.944 15.908 41.448 ;
     RECT  13.504 52.512 15.908 53.112 ;
     RECT  14.861 55.728 15.908 55.752 ;
     RECT  13.504 68.496 15.908 68.52 ;
     RECT  14.861 72.192 15.908 72.216 ;
     RECT  13.504 84.432 15.908 84.456 ;
     RECT  13.504 103.056 15.908 103.848 ;
     RECT  13.504 108.144 15.908 108.168 ;
     RECT  13.504 119.136 15.908 119.16 ;
     RECT  13.504 134.544 15.908 134.568 ;
     RECT  13.504 135.648 15.908 135.672 ;
     RECT  15.908 2.148 16.012 144.732 ;
     RECT  16.012 2.418 16.204 144.462 ;
     RECT  18.205 2.496 18.608 2.52 ;
     RECT  18.205 4.176 18.608 4.2 ;
     RECT  16.204 6.288 18.608 6.312 ;
     RECT  16.204 10.704 18.608 10.728 ;
     RECT  16.204 21.696 18.608 22.824 ;
     RECT  16.204 26.112 18.608 26.136 ;
     RECT  16.204 37.104 18.608 37.704 ;
     RECT  16.204 39.312 18.608 39.336 ;
     RECT  16.204 40.944 18.608 41.448 ;
     RECT  16.204 52.512 18.608 53.112 ;
     RECT  16.204 55.728 18.608 55.752 ;
     RECT  16.204 68.496 18.608 68.52 ;
     RECT  16.204 72.192 18.608 72.216 ;
     RECT  16.204 84.432 18.608 84.456 ;
     RECT  16.204 103.056 18.608 103.848 ;
     RECT  16.204 108.144 18.608 108.168 ;
     RECT  16.204 119.136 18.608 119.16 ;
     RECT  16.204 134.544 18.608 134.568 ;
     RECT  16.204 135.648 18.608 135.672 ;
     RECT  18.608 2.148 18.712 144.732 ;
     RECT  18.712 2.418 18.904 144.462 ;
     RECT  18.904 21.696 19.933 22.824 ;
     RECT  18.904 71.232 19.933 72.216 ;
     RECT  18.904 134.544 19.933 134.568 ;
     RECT  18.904 135.648 19.933 135.672 ;
     RECT  18.904 140.064 19.933 140.088 ;
     RECT  18.904 26.112 20.473 26.136 ;
     RECT  18.904 56.928 20.473 56.952 ;
     RECT  19.933 61.344 20.473 61.368 ;
     RECT  19.933 66.288 20.473 66.84 ;
     RECT  19.933 71.232 20.473 72.936 ;
     RECT  18.904 87.648 20.473 87.672 ;
     RECT  19.933 89.424 20.473 89.976 ;
     RECT  18.904 103.056 20.473 103.752 ;
     RECT  19.933 109.2 20.473 110.328 ;
     RECT  19.933 125.184 20.473 125.208 ;
     RECT  18.904 142.272 20.473 142.824 ;
     RECT  18.904 6.288 20.509 6.84 ;
     RECT  19.933 9.024 20.509 9.048 ;
     RECT  18.904 10.704 20.509 10.728 ;
     RECT  20.473 17.28 20.509 17.304 ;
     RECT  19.933 18.96 20.509 20.04 ;
     RECT  19.933 21.696 20.509 23.928 ;
     RECT  20.473 26.112 20.509 27.24 ;
     RECT  20.473 29.952 20.509 29.976 ;
     RECT  20.473 32.688 20.509 32.712 ;
     RECT  20.473 33.792 20.509 33.816 ;
     RECT  18.904 37.104 20.509 37.704 ;
     RECT  18.904 39.312 20.509 39.336 ;
     RECT  18.904 40.944 20.509 41.544 ;
     RECT  18.904 45.36 20.509 45.384 ;
     RECT  18.904 52.512 20.509 53.112 ;
     RECT  18.904 55.728 20.509 55.752 ;
     RECT  20.473 56.928 20.509 57.48 ;
     RECT  20.473 58.56 20.509 61.368 ;
     RECT  19.933 62.448 20.509 62.472 ;
     RECT  19.933 64.08 20.509 64.632 ;
     RECT  20.473 66.288 20.509 67.416 ;
     RECT  19.933 75.648 20.509 76.2 ;
     RECT  19.933 78.384 20.509 78.408 ;
     RECT  19.933 79.488 20.509 80.616 ;
     RECT  20.473 82.8 20.509 82.824 ;
     RECT  20.473 87.216 20.509 89.976 ;
     RECT  19.933 91.056 20.509 91.608 ;
     RECT  19.933 94.368 20.509 94.92 ;
     RECT  20.473 102.048 20.509 103.752 ;
     RECT  19.933 104.832 20.509 105.384 ;
     RECT  19.933 106.464 20.509 106.488 ;
     RECT  18.904 108.144 20.509 108.168 ;
     RECT  20.473 109.2 20.509 111.432 ;
     RECT  20.473 113.088 20.509 113.112 ;
     RECT  18.904 119.136 20.509 119.16 ;
     RECT  19.933 122.448 20.509 122.472 ;
     RECT  20.473 124.08 20.509 125.208 ;
     RECT  20.473 131.808 20.509 132.36 ;
     RECT  19.933 133.44 20.509 135.672 ;
     RECT  19.933 137.856 20.509 137.88 ;
     RECT  19.933 138.96 20.509 138.984 ;
     RECT  19.933 140.064 20.509 140.616 ;
     RECT  18.904 2.496 21.481 2.52 ;
     RECT  18.904 4.176 21.481 4.2 ;
     RECT  18.904 5.184 21.481 5.208 ;
     RECT  20.509 6.288 21.481 11.256 ;
     RECT  20.473 12.864 21.481 12.888 ;
     RECT  20.473 14.544 21.481 14.568 ;
     RECT  20.509 17.28 21.481 17.88 ;
     RECT  20.509 18.96 21.481 27.24 ;
     RECT  20.509 29.376 21.481 29.976 ;
     RECT  20.473 31.584 21.481 31.608 ;
     RECT  20.509 32.688 21.481 37.704 ;
     RECT  20.509 38.736 21.481 41.544 ;
     RECT  20.509 45.36 21.481 45.96 ;
     RECT  20.509 47.568 21.481 48.696 ;
     RECT  20.509 49.776 21.481 53.112 ;
     RECT  20.509 55.728 21.481 57.48 ;
     RECT  20.509 58.56 21.481 62.472 ;
     RECT  20.509 63.552 21.481 67.416 ;
     RECT  18.904 68.496 21.481 68.52 ;
     RECT  20.473 69.6 21.481 69.624 ;
     RECT  20.473 71.232 21.481 73.992 ;
     RECT  20.509 75.648 21.481 80.616 ;
     RECT  20.509 81.696 21.481 82.824 ;
     RECT  18.904 84.432 21.481 84.456 ;
     RECT  20.473 85.536 21.481 85.56 ;
     RECT  20.509 87.216 21.481 96.024 ;
     RECT  20.509 97.104 21.481 97.128 ;
     RECT  20.473 98.208 21.481 98.232 ;
     RECT  20.473 99.312 21.481 99.336 ;
     RECT  20.473 100.416 21.481 100.968 ;
     RECT  20.509 102.048 21.481 111.432 ;
     RECT  20.509 112.512 21.481 113.112 ;
     RECT  20.473 116.4 21.481 116.952 ;
     RECT  20.509 118.032 21.481 118.056 ;
     RECT  20.509 119.136 21.481 125.208 ;
     RECT  20.473 127.392 21.481 127.416 ;
     RECT  20.473 130.128 21.481 130.152 ;
     RECT  20.509 131.808 21.481 140.616 ;
     RECT  20.473 141.696 21.481 142.824 ;
     RECT  21.481 2.4 21.516 2.424 ;
     RECT  21.481 2.424 21.564 2.976 ;
     RECT  21.481 2.976 21.516 3 ;
     RECT  21.481 3 21.564 3.504 ;
     RECT  21.481 3.504 21.516 3.528 ;
     RECT  21.481 3.528 21.564 4.08 ;
     RECT  21.481 4.08 21.516 4.104 ;
     RECT  21.481 4.104 21.564 4.608 ;
     RECT  21.481 4.608 21.516 4.632 ;
     RECT  21.481 4.632 21.564 5.184 ;
     RECT  21.481 5.184 21.516 5.208 ;
     RECT  21.481 5.208 21.564 5.712 ;
     RECT  21.481 5.712 21.516 5.736 ;
     RECT  21.481 5.736 21.564 6.288 ;
     RECT  21.481 6.288 21.516 6.312 ;
     RECT  21.481 6.312 21.564 6.816 ;
     RECT  21.481 6.816 21.516 6.84 ;
     RECT  21.481 6.84 21.564 7.392 ;
     RECT  21.481 7.392 21.516 7.416 ;
     RECT  21.481 7.416 21.564 7.92 ;
     RECT  21.481 7.92 21.516 7.944 ;
     RECT  21.481 7.944 21.564 8.496 ;
     RECT  21.481 8.496 21.516 8.52 ;
     RECT  21.481 8.52 21.564 9.024 ;
     RECT  21.481 9.024 21.516 9.048 ;
     RECT  21.481 9.048 21.564 9.6 ;
     RECT  21.481 9.6 21.516 9.624 ;
     RECT  21.481 9.624 21.564 10.128 ;
     RECT  21.481 10.128 21.516 10.152 ;
     RECT  21.481 10.152 21.564 10.704 ;
     RECT  21.481 10.704 21.516 10.728 ;
     RECT  21.481 10.728 21.564 11.232 ;
     RECT  21.481 11.232 21.516 11.256 ;
     RECT  21.481 11.256 21.564 11.76 ;
     RECT  21.481 11.76 21.516 11.784 ;
     RECT  21.481 11.784 21.564 12.336 ;
     RECT  21.481 12.336 21.516 12.36 ;
     RECT  21.481 12.36 21.564 12.864 ;
     RECT  21.481 12.864 21.516 12.888 ;
     RECT  21.481 12.888 21.564 13.44 ;
     RECT  21.481 13.44 21.516 13.464 ;
     RECT  21.481 13.464 21.564 13.968 ;
     RECT  21.481 13.968 21.516 13.992 ;
     RECT  21.481 13.992 21.564 14.544 ;
     RECT  21.481 14.544 21.516 14.568 ;
     RECT  21.481 14.568 21.564 15.072 ;
     RECT  21.481 15.072 21.516 15.096 ;
     RECT  21.481 15.096 21.564 15.648 ;
     RECT  21.481 15.648 21.516 15.672 ;
     RECT  21.481 15.672 21.564 16.176 ;
     RECT  21.481 16.176 21.516 16.2 ;
     RECT  21.481 16.2 21.564 16.752 ;
     RECT  21.481 16.752 21.516 16.776 ;
     RECT  21.481 16.776 21.564 17.28 ;
     RECT  21.481 17.28 21.516 17.304 ;
     RECT  21.481 17.304 21.564 17.856 ;
     RECT  21.481 17.856 21.516 17.88 ;
     RECT  21.481 17.88 21.564 18.384 ;
     RECT  21.481 18.384 21.516 18.408 ;
     RECT  21.481 18.408 21.564 18.96 ;
     RECT  21.481 18.96 21.516 18.984 ;
     RECT  21.481 18.984 21.564 19.488 ;
     RECT  21.481 19.488 21.516 19.512 ;
     RECT  21.481 19.512 21.564 20.016 ;
     RECT  21.481 20.016 21.516 20.04 ;
     RECT  21.481 20.04 21.564 20.592 ;
     RECT  21.481 20.592 21.516 20.616 ;
     RECT  21.481 20.616 21.564 21.12 ;
     RECT  21.481 21.12 21.516 21.144 ;
     RECT  21.481 21.144 21.564 21.696 ;
     RECT  21.481 21.696 21.516 21.72 ;
     RECT  21.481 21.72 21.564 22.224 ;
     RECT  21.481 22.224 21.516 22.248 ;
     RECT  21.481 22.248 21.564 22.8 ;
     RECT  21.481 22.8 21.516 22.824 ;
     RECT  21.481 22.824 21.564 23.328 ;
     RECT  21.481 23.328 21.516 23.352 ;
     RECT  21.481 23.352 21.564 23.904 ;
     RECT  21.481 23.904 21.516 23.928 ;
     RECT  21.481 23.928 21.564 24.432 ;
     RECT  21.481 24.432 21.516 24.456 ;
     RECT  21.481 24.456 21.564 25.008 ;
     RECT  21.481 25.008 21.516 25.032 ;
     RECT  21.481 25.032 21.564 25.536 ;
     RECT  21.481 25.536 21.516 25.56 ;
     RECT  21.481 25.56 21.564 26.112 ;
     RECT  21.481 26.112 21.516 26.136 ;
     RECT  21.481 26.136 21.564 26.64 ;
     RECT  21.481 26.64 21.516 26.664 ;
     RECT  21.481 26.664 21.564 27.216 ;
     RECT  21.481 27.216 21.516 27.24 ;
     RECT  21.481 27.24 21.564 27.744 ;
     RECT  21.481 27.744 21.516 27.768 ;
     RECT  21.481 27.768 21.564 28.32 ;
     RECT  21.481 28.32 21.516 28.344 ;
     RECT  21.481 28.344 21.564 28.848 ;
     RECT  21.481 28.848 21.516 28.872 ;
     RECT  21.481 28.872 21.564 29.376 ;
     RECT  21.481 29.376 21.516 29.4 ;
     RECT  21.481 29.4 21.564 29.952 ;
     RECT  21.481 29.952 21.516 29.976 ;
     RECT  21.481 29.976 21.564 30.48 ;
     RECT  21.481 30.48 21.516 30.504 ;
     RECT  21.481 30.504 21.564 31.056 ;
     RECT  21.481 31.056 21.516 31.08 ;
     RECT  21.481 31.08 21.564 31.584 ;
     RECT  21.481 31.584 21.516 31.608 ;
     RECT  21.481 31.608 21.564 32.16 ;
     RECT  21.481 32.16 21.516 32.184 ;
     RECT  21.481 32.184 21.564 32.688 ;
     RECT  21.481 32.688 21.516 32.712 ;
     RECT  21.481 32.712 21.564 33.264 ;
     RECT  21.481 33.264 21.516 33.288 ;
     RECT  21.481 33.288 21.564 33.792 ;
     RECT  21.481 33.792 21.516 33.816 ;
     RECT  21.481 33.816 21.564 34.368 ;
     RECT  21.481 34.368 21.516 34.392 ;
     RECT  21.481 34.392 21.564 34.896 ;
     RECT  21.481 34.896 21.516 34.92 ;
     RECT  21.481 34.92 21.564 35.472 ;
     RECT  21.481 35.472 21.516 35.496 ;
     RECT  21.481 35.496 21.564 36 ;
     RECT  21.481 36 21.516 36.024 ;
     RECT  21.481 36.024 21.564 36.576 ;
     RECT  21.481 36.576 21.516 36.6 ;
     RECT  21.481 36.6 21.564 37.104 ;
     RECT  21.481 37.104 21.516 37.128 ;
     RECT  21.481 37.128 21.564 37.68 ;
     RECT  21.481 37.68 21.516 37.704 ;
     RECT  21.481 37.704 21.564 38.208 ;
     RECT  21.481 38.208 21.516 38.232 ;
     RECT  21.481 38.232 21.564 38.736 ;
     RECT  21.481 38.736 21.516 38.76 ;
     RECT  21.481 38.76 21.564 39.312 ;
     RECT  21.481 39.312 21.516 39.336 ;
     RECT  21.481 39.336 21.564 39.84 ;
     RECT  21.481 39.84 21.516 39.864 ;
     RECT  21.481 39.864 21.564 40.416 ;
     RECT  21.481 40.416 21.516 40.44 ;
     RECT  21.481 40.44 21.564 40.944 ;
     RECT  21.481 40.944 21.516 40.968 ;
     RECT  21.481 40.968 21.564 41.52 ;
     RECT  21.481 41.52 21.516 41.544 ;
     RECT  21.481 41.544 21.564 42.048 ;
     RECT  21.481 42.048 21.516 42.072 ;
     RECT  21.481 42.072 21.564 42.624 ;
     RECT  21.481 42.624 21.516 42.648 ;
     RECT  21.481 42.648 21.564 43.152 ;
     RECT  21.481 43.152 21.516 43.176 ;
     RECT  21.481 43.176 21.564 43.728 ;
     RECT  21.481 43.728 21.516 43.752 ;
     RECT  21.481 43.752 21.564 44.256 ;
     RECT  21.481 44.256 21.516 44.28 ;
     RECT  21.481 44.28 21.564 44.832 ;
     RECT  21.481 44.832 21.516 44.856 ;
     RECT  21.481 44.856 21.564 45.36 ;
     RECT  21.481 45.36 21.516 45.384 ;
     RECT  21.481 45.384 21.564 45.936 ;
     RECT  21.481 45.936 21.516 45.96 ;
     RECT  21.481 45.96 21.564 46.464 ;
     RECT  21.481 46.464 21.516 46.488 ;
     RECT  21.481 46.488 21.564 46.992 ;
     RECT  21.481 46.992 21.516 47.016 ;
     RECT  21.481 47.016 21.564 47.568 ;
     RECT  21.481 47.568 21.516 47.592 ;
     RECT  21.481 47.592 21.564 48.096 ;
     RECT  21.481 48.096 21.516 48.12 ;
     RECT  21.481 48.12 21.564 48.672 ;
     RECT  21.481 48.672 21.516 48.696 ;
     RECT  21.481 48.696 21.564 49.2 ;
     RECT  21.481 49.2 21.516 49.224 ;
     RECT  21.481 49.224 21.564 49.776 ;
     RECT  21.481 49.776 21.516 49.8 ;
     RECT  21.481 49.8 21.564 50.304 ;
     RECT  21.481 50.304 21.516 50.328 ;
     RECT  21.481 50.328 21.564 50.88 ;
     RECT  21.481 50.88 21.516 50.904 ;
     RECT  21.481 50.904 21.564 51.408 ;
     RECT  21.481 51.408 21.516 51.432 ;
     RECT  21.481 51.432 21.564 51.984 ;
     RECT  21.481 51.984 21.516 52.008 ;
     RECT  21.481 52.008 21.564 52.512 ;
     RECT  21.481 52.512 21.516 52.536 ;
     RECT  21.481 52.536 21.564 53.088 ;
     RECT  21.481 53.088 21.516 53.112 ;
     RECT  21.481 53.112 21.564 53.616 ;
     RECT  21.481 53.616 21.516 53.64 ;
     RECT  21.481 53.64 21.564 54.192 ;
     RECT  21.481 54.192 21.516 54.216 ;
     RECT  21.481 54.216 21.564 54.72 ;
     RECT  21.481 54.72 21.516 54.744 ;
     RECT  21.481 54.744 21.564 55.296 ;
     RECT  21.481 55.296 21.516 55.32 ;
     RECT  21.481 55.32 21.564 55.824 ;
     RECT  21.481 55.824 21.516 55.848 ;
     RECT  21.481 55.848 21.564 56.352 ;
     RECT  21.481 56.352 21.516 56.376 ;
     RECT  21.481 56.376 21.564 56.928 ;
     RECT  21.481 56.928 21.516 56.952 ;
     RECT  21.481 56.952 21.564 57.456 ;
     RECT  21.481 57.456 21.516 57.48 ;
     RECT  21.481 57.48 21.564 58.032 ;
     RECT  21.481 58.032 21.516 58.056 ;
     RECT  21.481 58.056 21.564 58.56 ;
     RECT  21.481 58.56 21.516 58.584 ;
     RECT  21.481 58.584 21.564 59.136 ;
     RECT  21.481 59.136 21.516 59.16 ;
     RECT  21.481 59.16 21.564 59.664 ;
     RECT  21.481 59.664 21.516 59.688 ;
     RECT  21.481 59.688 21.564 60.24 ;
     RECT  21.481 60.24 21.516 60.264 ;
     RECT  21.481 60.264 21.564 60.768 ;
     RECT  21.481 60.768 21.516 60.792 ;
     RECT  21.481 60.792 21.564 61.344 ;
     RECT  21.481 61.344 21.516 61.368 ;
     RECT  21.481 61.368 21.564 61.872 ;
     RECT  21.481 61.872 21.516 61.896 ;
     RECT  21.481 61.896 21.564 62.448 ;
     RECT  21.481 62.448 21.516 62.472 ;
     RECT  21.481 62.472 21.564 62.976 ;
     RECT  21.481 62.976 21.516 63 ;
     RECT  21.481 63 21.564 63.552 ;
     RECT  21.481 63.552 21.516 63.576 ;
     RECT  21.481 63.576 21.564 64.08 ;
     RECT  21.481 64.08 21.516 64.104 ;
     RECT  21.481 64.104 21.564 64.608 ;
     RECT  21.481 64.608 21.516 64.632 ;
     RECT  21.481 64.632 21.564 65.184 ;
     RECT  21.481 65.184 21.516 65.208 ;
     RECT  21.481 65.208 21.564 65.712 ;
     RECT  21.481 65.712 21.516 65.736 ;
     RECT  21.481 65.736 21.564 66.288 ;
     RECT  21.481 66.288 21.516 66.312 ;
     RECT  21.481 66.312 21.564 66.816 ;
     RECT  21.481 66.816 21.516 66.84 ;
     RECT  21.481 66.84 21.564 67.392 ;
     RECT  21.481 67.392 21.516 67.416 ;
     RECT  21.481 67.416 21.564 67.92 ;
     RECT  21.481 67.92 21.516 67.944 ;
     RECT  21.481 67.944 21.564 68.496 ;
     RECT  21.481 68.496 21.516 68.52 ;
     RECT  21.481 68.52 21.564 69.024 ;
     RECT  21.481 69.024 21.516 69.048 ;
     RECT  21.481 69.048 21.564 69.6 ;
     RECT  21.481 69.6 21.516 69.624 ;
     RECT  21.481 69.624 21.564 70.128 ;
     RECT  21.481 70.128 21.516 70.152 ;
     RECT  21.481 70.152 21.564 70.704 ;
     RECT  21.481 70.704 21.516 70.728 ;
     RECT  21.481 70.728 21.564 71.232 ;
     RECT  21.481 71.232 21.516 71.256 ;
     RECT  21.481 71.256 21.564 71.808 ;
     RECT  21.481 71.808 21.516 71.832 ;
     RECT  21.481 71.832 21.564 72.336 ;
     RECT  21.481 72.336 21.516 72.36 ;
     RECT  21.481 72.36 21.564 72.912 ;
     RECT  21.481 72.912 21.516 72.936 ;
     RECT  21.481 72.936 21.564 73.44 ;
     RECT  21.481 73.44 21.516 73.464 ;
     RECT  21.481 73.464 21.564 73.968 ;
     RECT  21.481 73.968 21.516 73.992 ;
     RECT  21.481 73.992 21.564 74.544 ;
     RECT  21.481 74.544 21.516 74.568 ;
     RECT  21.481 74.568 21.564 75.072 ;
     RECT  21.481 75.072 21.516 75.096 ;
     RECT  21.481 75.096 21.564 75.648 ;
     RECT  21.481 75.648 21.516 75.672 ;
     RECT  21.481 75.672 21.564 76.176 ;
     RECT  21.481 76.176 21.516 76.2 ;
     RECT  21.481 76.2 21.564 76.752 ;
     RECT  21.481 76.752 21.516 76.776 ;
     RECT  21.481 76.776 21.564 77.28 ;
     RECT  21.481 77.28 21.516 77.304 ;
     RECT  21.481 77.304 21.564 77.856 ;
     RECT  21.481 77.856 21.516 77.88 ;
     RECT  21.481 77.88 21.564 78.384 ;
     RECT  21.481 78.384 21.516 78.408 ;
     RECT  21.481 78.408 21.564 78.96 ;
     RECT  21.481 78.96 21.516 78.984 ;
     RECT  21.481 78.984 21.564 79.488 ;
     RECT  21.481 79.488 21.516 79.512 ;
     RECT  21.481 79.512 21.564 80.064 ;
     RECT  21.481 80.064 21.516 80.088 ;
     RECT  21.481 80.088 21.564 80.592 ;
     RECT  21.481 80.592 21.516 80.616 ;
     RECT  21.481 80.616 21.564 81.168 ;
     RECT  21.481 81.168 21.516 81.192 ;
     RECT  21.481 81.192 21.564 81.696 ;
     RECT  21.481 81.696 21.516 81.72 ;
     RECT  21.481 81.72 21.564 82.224 ;
     RECT  21.481 82.224 21.516 82.248 ;
     RECT  21.481 82.248 21.564 82.8 ;
     RECT  21.481 82.8 21.516 82.824 ;
     RECT  21.481 82.824 21.564 83.328 ;
     RECT  21.481 83.328 21.516 83.352 ;
     RECT  21.481 83.352 21.564 83.904 ;
     RECT  21.481 83.904 21.516 83.928 ;
     RECT  21.481 83.928 21.564 84.432 ;
     RECT  21.481 84.432 21.516 84.456 ;
     RECT  21.481 84.456 21.564 85.008 ;
     RECT  21.481 85.008 21.516 85.032 ;
     RECT  21.481 85.032 21.564 85.536 ;
     RECT  21.481 85.536 21.516 85.56 ;
     RECT  21.481 85.56 21.564 86.112 ;
     RECT  21.481 86.112 21.516 86.136 ;
     RECT  21.481 86.136 21.564 86.64 ;
     RECT  21.481 86.64 21.516 86.664 ;
     RECT  21.481 86.664 21.564 87.216 ;
     RECT  21.481 87.216 21.516 87.24 ;
     RECT  21.481 87.24 21.564 87.744 ;
     RECT  21.481 87.744 21.516 87.768 ;
     RECT  21.481 87.768 21.564 88.32 ;
     RECT  21.481 88.32 21.516 88.344 ;
     RECT  21.481 88.344 21.564 88.848 ;
     RECT  21.481 88.848 21.516 88.872 ;
     RECT  21.481 88.872 21.564 89.424 ;
     RECT  21.481 89.424 21.516 89.448 ;
     RECT  21.481 89.448 21.564 89.952 ;
     RECT  21.481 89.952 21.516 89.976 ;
     RECT  21.481 89.976 21.564 90.528 ;
     RECT  21.481 90.528 21.516 90.552 ;
     RECT  21.481 90.552 21.564 91.056 ;
     RECT  21.481 91.056 21.516 91.08 ;
     RECT  21.481 91.08 21.564 91.584 ;
     RECT  21.481 91.584 21.516 91.608 ;
     RECT  21.481 91.608 21.564 92.16 ;
     RECT  21.481 92.16 21.516 92.184 ;
     RECT  21.481 92.184 21.564 92.688 ;
     RECT  21.481 92.688 21.516 92.712 ;
     RECT  21.481 92.712 21.564 93.264 ;
     RECT  21.481 93.264 21.516 93.288 ;
     RECT  21.481 93.288 21.564 93.792 ;
     RECT  21.481 93.792 21.516 93.816 ;
     RECT  21.481 93.816 21.564 94.368 ;
     RECT  21.481 94.368 21.516 94.392 ;
     RECT  21.481 94.392 21.564 94.896 ;
     RECT  21.481 94.896 21.516 94.92 ;
     RECT  21.481 94.92 21.564 95.472 ;
     RECT  21.481 95.472 21.516 95.496 ;
     RECT  21.481 95.496 21.564 96 ;
     RECT  21.481 96 21.516 96.024 ;
     RECT  21.481 96.024 21.564 96.576 ;
     RECT  21.481 96.576 21.516 96.6 ;
     RECT  21.481 96.6 21.564 97.104 ;
     RECT  21.481 97.104 21.516 97.128 ;
     RECT  21.481 97.128 21.564 97.68 ;
     RECT  21.481 97.68 21.516 97.704 ;
     RECT  21.481 97.704 21.564 98.208 ;
     RECT  21.481 98.208 21.516 98.232 ;
     RECT  21.481 98.232 21.564 98.784 ;
     RECT  21.481 98.784 21.516 98.808 ;
     RECT  21.481 98.808 21.564 99.312 ;
     RECT  21.481 99.312 21.516 99.336 ;
     RECT  21.481 99.336 21.564 99.84 ;
     RECT  21.481 99.84 21.516 99.864 ;
     RECT  21.481 99.864 21.564 100.416 ;
     RECT  21.481 100.416 21.516 100.44 ;
     RECT  21.481 100.44 21.564 100.944 ;
     RECT  21.481 100.944 21.516 100.968 ;
     RECT  21.481 100.968 21.564 101.52 ;
     RECT  21.481 101.52 21.516 101.544 ;
     RECT  21.481 101.544 21.564 102.048 ;
     RECT  21.481 102.048 21.516 102.072 ;
     RECT  21.481 102.072 21.564 102.624 ;
     RECT  21.481 102.624 21.516 102.648 ;
     RECT  21.481 102.648 21.564 103.152 ;
     RECT  21.481 103.152 21.516 103.176 ;
     RECT  21.481 103.176 21.564 103.728 ;
     RECT  21.481 103.728 21.516 103.752 ;
     RECT  21.481 103.752 21.564 104.256 ;
     RECT  21.481 104.256 21.516 104.28 ;
     RECT  21.481 104.28 21.564 104.832 ;
     RECT  21.481 104.832 21.516 104.856 ;
     RECT  21.481 104.856 21.564 105.36 ;
     RECT  21.481 105.36 21.516 105.384 ;
     RECT  21.481 105.384 21.564 105.936 ;
     RECT  21.481 105.936 21.516 105.96 ;
     RECT  21.481 105.96 21.564 106.464 ;
     RECT  21.481 106.464 21.516 106.488 ;
     RECT  21.481 106.488 21.564 107.04 ;
     RECT  21.481 107.04 21.516 107.064 ;
     RECT  21.481 107.064 21.564 107.568 ;
     RECT  21.481 107.568 21.516 107.592 ;
     RECT  21.481 107.592 21.564 108.144 ;
     RECT  21.481 108.144 21.516 108.168 ;
     RECT  21.481 108.168 21.564 108.672 ;
     RECT  21.481 108.672 21.516 108.696 ;
     RECT  21.481 108.696 21.564 109.2 ;
     RECT  21.481 109.2 21.516 109.224 ;
     RECT  21.481 109.224 21.564 109.776 ;
     RECT  21.481 109.776 21.516 109.8 ;
     RECT  21.481 109.8 21.564 110.304 ;
     RECT  21.481 110.304 21.516 110.328 ;
     RECT  21.481 110.328 21.564 110.88 ;
     RECT  21.481 110.88 21.516 110.904 ;
     RECT  21.481 110.904 21.564 111.408 ;
     RECT  21.481 111.408 21.516 111.432 ;
     RECT  21.481 111.432 21.564 111.984 ;
     RECT  21.481 111.984 21.516 112.008 ;
     RECT  21.481 112.008 21.564 112.512 ;
     RECT  21.481 112.512 21.516 112.536 ;
     RECT  21.481 112.536 21.564 113.088 ;
     RECT  21.481 113.088 21.516 113.112 ;
     RECT  21.481 113.112 21.564 113.616 ;
     RECT  21.481 113.616 21.516 113.64 ;
     RECT  21.481 113.64 21.564 114.192 ;
     RECT  21.481 114.192 21.516 114.216 ;
     RECT  21.481 114.216 21.564 114.72 ;
     RECT  21.481 114.72 21.516 114.744 ;
     RECT  21.481 114.744 21.564 115.296 ;
     RECT  21.481 115.296 21.516 115.32 ;
     RECT  21.481 115.32 21.564 115.824 ;
     RECT  21.481 115.824 21.516 115.848 ;
     RECT  21.481 115.848 21.564 116.4 ;
     RECT  21.481 116.4 21.516 116.424 ;
     RECT  21.481 116.424 21.564 116.928 ;
     RECT  21.481 116.928 21.516 116.952 ;
     RECT  21.481 116.952 21.564 117.456 ;
     RECT  21.481 117.456 21.516 117.48 ;
     RECT  21.481 117.48 21.564 118.032 ;
     RECT  21.481 118.032 21.516 118.056 ;
     RECT  21.481 118.056 21.564 118.56 ;
     RECT  21.481 118.56 21.516 118.584 ;
     RECT  21.481 118.584 21.564 119.136 ;
     RECT  21.481 119.136 21.516 119.16 ;
     RECT  21.481 119.16 21.564 119.664 ;
     RECT  21.481 119.664 21.516 119.688 ;
     RECT  21.481 119.688 21.564 120.24 ;
     RECT  21.481 120.24 21.516 120.264 ;
     RECT  21.481 120.264 21.564 120.768 ;
     RECT  21.481 120.768 21.516 120.792 ;
     RECT  21.481 120.792 21.564 121.344 ;
     RECT  21.481 121.344 21.516 121.368 ;
     RECT  21.481 121.368 21.564 121.872 ;
     RECT  21.481 121.872 21.516 121.896 ;
     RECT  21.481 121.896 21.564 122.448 ;
     RECT  21.481 122.448 21.516 122.472 ;
     RECT  21.481 122.472 21.564 122.976 ;
     RECT  21.481 122.976 21.516 123 ;
     RECT  21.481 123 21.564 123.552 ;
     RECT  21.481 123.552 21.516 123.576 ;
     RECT  21.481 123.576 21.564 124.08 ;
     RECT  21.481 124.08 21.516 124.104 ;
     RECT  21.481 124.104 21.564 124.656 ;
     RECT  21.481 124.656 21.516 124.68 ;
     RECT  21.481 124.68 21.564 125.184 ;
     RECT  21.481 125.184 21.516 125.208 ;
     RECT  21.481 125.208 21.564 125.76 ;
     RECT  21.481 125.76 21.516 125.784 ;
     RECT  21.481 125.784 21.564 126.288 ;
     RECT  21.481 126.288 21.516 126.312 ;
     RECT  21.481 126.312 21.564 126.816 ;
     RECT  21.481 126.816 21.516 126.84 ;
     RECT  21.481 126.84 21.564 127.392 ;
     RECT  21.481 127.392 21.516 127.416 ;
     RECT  21.481 127.416 21.564 127.92 ;
     RECT  21.481 127.92 21.516 127.944 ;
     RECT  21.481 127.944 21.564 128.496 ;
     RECT  21.481 128.496 21.516 128.52 ;
     RECT  21.481 128.52 21.564 129.024 ;
     RECT  21.481 129.024 21.516 129.048 ;
     RECT  21.481 129.048 21.564 129.6 ;
     RECT  21.481 129.6 21.516 129.624 ;
     RECT  21.481 129.624 21.564 130.128 ;
     RECT  21.481 130.128 21.516 130.152 ;
     RECT  21.481 130.152 21.564 130.704 ;
     RECT  21.481 130.704 21.516 130.728 ;
     RECT  21.481 130.728 21.564 131.232 ;
     RECT  21.481 131.232 21.516 131.256 ;
     RECT  21.481 131.256 21.564 131.808 ;
     RECT  21.481 131.808 21.516 131.832 ;
     RECT  21.481 131.832 21.564 132.336 ;
     RECT  21.481 132.336 21.516 132.36 ;
     RECT  21.481 132.36 21.564 132.912 ;
     RECT  21.481 132.912 21.516 132.936 ;
     RECT  21.481 132.936 21.564 133.44 ;
     RECT  21.481 133.44 21.516 133.464 ;
     RECT  21.481 133.464 21.564 134.016 ;
     RECT  21.481 134.016 21.516 134.04 ;
     RECT  21.481 134.04 21.564 134.544 ;
     RECT  21.481 134.544 21.516 134.568 ;
     RECT  21.481 134.568 21.564 135.072 ;
     RECT  21.481 135.072 21.516 135.096 ;
     RECT  21.481 135.096 21.564 135.648 ;
     RECT  21.481 135.648 21.516 135.672 ;
     RECT  21.481 135.672 21.564 136.176 ;
     RECT  21.481 136.176 21.516 136.2 ;
     RECT  21.481 136.2 21.564 136.752 ;
     RECT  21.481 136.752 21.516 136.776 ;
     RECT  21.481 136.776 21.564 137.28 ;
     RECT  21.481 137.28 21.516 137.304 ;
     RECT  21.481 137.304 21.564 137.856 ;
     RECT  21.481 137.856 21.516 137.88 ;
     RECT  21.481 137.88 21.564 138.384 ;
     RECT  21.481 138.384 21.516 138.408 ;
     RECT  21.481 138.408 21.564 138.96 ;
     RECT  21.481 138.96 21.516 138.984 ;
     RECT  21.481 138.984 21.564 139.488 ;
     RECT  21.481 139.488 21.516 139.512 ;
     RECT  21.481 139.512 21.564 140.064 ;
     RECT  21.481 140.064 21.516 140.088 ;
     RECT  21.481 140.088 21.564 140.592 ;
     RECT  21.481 140.592 21.516 140.616 ;
     RECT  21.481 140.616 21.564 141.168 ;
     RECT  21.481 141.168 21.516 141.192 ;
     RECT  21.481 141.192 21.564 141.696 ;
     RECT  21.481 141.696 21.516 141.72 ;
     RECT  21.481 141.72 21.564 142.272 ;
     RECT  21.481 142.272 21.516 142.296 ;
     RECT  21.481 142.296 21.564 142.8 ;
     RECT  21.481 142.8 21.516 142.824 ;
     RECT  21.481 142.824 21.564 143.376 ;
     RECT  21.481 143.376 21.516 143.4 ;
    LAYER M5 ;
     RECT  2.4 2.137 2.52 2.151 ;
     RECT  5.1 2.137 5.22 2.151 ;
     RECT  7.8 2.137 7.92 2.151 ;
     RECT  10.5 2.137 10.62 2.151 ;
     RECT  13.2 2.137 13.32 2.151 ;
     RECT  15.9 2.137 16.02 2.151 ;
     RECT  18.6 2.137 18.72 2.151 ;
     RECT  5.1 2.151 5.412 2.677 ;
     RECT  4.32 2.677 5.412 3.205 ;
     RECT  4.32 3.205 5.784 6.803 ;
     RECT  7.8 2.151 8.112 7.957 ;
     RECT  4.464 6.803 5.784 8.579 ;
     RECT  5.1 8.579 5.784 9.637 ;
     RECT  4.272 9.637 5.784 9.731 ;
     RECT  4.272 9.731 5.544 10.883 ;
     RECT  7.056 7.957 8.112 10.981 ;
     RECT  2.4 2.151 2.712 11.941 ;
     RECT  5.1 10.883 5.544 12.997 ;
     RECT  6.864 10.981 8.112 15.301 ;
     RECT  6.864 15.301 8.232 15.347 ;
     RECT  2.4 11.941 3.48 15.731 ;
     RECT  5.1 12.997 5.784 16.501 ;
     RECT  4.32 16.501 5.784 16.835 ;
     RECT  7.8 15.347 8.232 19.523 ;
     RECT  7.8 19.523 8.112 19.861 ;
     RECT  6.864 19.861 8.112 21.155 ;
     RECT  4.32 16.835 5.64 22.021 ;
     RECT  7.8 21.155 8.112 23.317 ;
     RECT  4.32 22.021 5.688 25.045 ;
     RECT  4.272 25.045 5.688 25.429 ;
     RECT  7.008 23.317 8.112 26.533 ;
     RECT  7.008 26.533 8.232 26.579 ;
     RECT  4.272 25.429 5.736 26.771 ;
     RECT  4.368 26.771 5.736 30.565 ;
     RECT  4.368 30.565 6.024 30.851 ;
     RECT  5.1 30.851 6.024 31.813 ;
     RECT  4.512 31.813 6.024 32.051 ;
     RECT  4.512 32.051 5.688 33.925 ;
     RECT  7.8 26.579 8.232 34.453 ;
     RECT  6.864 34.453 8.232 34.931 ;
     RECT  2.4 15.731 2.712 35.557 ;
     RECT  4.32 33.925 5.688 35.557 ;
     RECT  2.4 35.557 5.688 35.603 ;
     RECT  6.864 34.931 8.112 39.635 ;
     RECT  2.4 35.603 3.672 39.877 ;
     RECT  5.1 35.603 5.688 39.877 ;
     RECT  7.056 39.635 8.112 41.557 ;
     RECT  2.4 39.877 5.688 41.651 ;
     RECT  7.008 41.557 8.112 41.749 ;
     RECT  4.464 41.651 5.688 42.707 ;
     RECT  4.512 42.707 5.688 43.285 ;
     RECT  4.512 43.285 6.024 43.813 ;
     RECT  7.008 41.749 8.232 43.813 ;
     RECT  2.4 41.651 3.48 44.483 ;
     RECT  4.512 43.813 8.232 47.173 ;
     RECT  4.32 47.173 8.232 48.275 ;
     RECT  2.4 44.483 2.712 49.333 ;
     RECT  4.32 48.275 6.024 51.011 ;
     RECT  4.464 51.011 6.024 54.133 ;
     RECT  7.056 48.275 8.232 54.133 ;
     RECT  4.464 54.133 8.232 58.259 ;
     RECT  2.4 49.333 3.288 59.315 ;
     RECT  4.992 58.259 8.232 60.373 ;
     RECT  4.272 60.373 8.232 62.435 ;
     RECT  4.272 62.435 5.688 62.771 ;
     RECT  2.4 59.315 2.712 63.205 ;
     RECT  4.992 62.771 5.688 63.973 ;
     RECT  4.656 63.973 5.688 66.755 ;
     RECT  4.704 66.755 5.688 69.011 ;
     RECT  2.4 63.205 3.192 70.981 ;
     RECT  4.704 69.011 5.592 71.221 ;
     RECT  6.864 62.435 8.232 71.221 ;
     RECT  4.704 71.221 8.232 71.315 ;
     RECT  4.944 71.315 8.232 71.891 ;
     RECT  7.8 71.891 8.232 72.419 ;
     RECT  2.4 70.981 3.288 72.563 ;
     RECT  4.944 71.891 6.12 73.477 ;
     RECT  4.272 73.477 6.12 74.723 ;
     RECT  7.8 72.419 8.112 76.837 ;
     RECT  4.32 74.723 6.12 78.035 ;
     RECT  7.8 76.837 8.52 79.235 ;
     RECT  4.32 78.035 5.976 80.341 ;
     RECT  7.8 79.235 8.232 80.675 ;
     RECT  4.224 80.341 5.976 80.917 ;
     RECT  7.8 80.675 8.112 80.917 ;
     RECT  4.224 80.917 8.112 82.213 ;
     RECT  4.176 82.213 8.112 82.739 ;
     RECT  4.176 82.739 5.976 86.195 ;
     RECT  7.056 82.739 8.112 87.827 ;
     RECT  7.392 87.827 8.112 91.763 ;
     RECT  7.68 91.763 8.112 94.067 ;
     RECT  7.8 94.067 8.112 94.405 ;
     RECT  4.32 86.195 5.976 98.629 ;
     RECT  4.32 98.629 6.072 98.675 ;
     RECT  4.416 98.675 6.072 100.501 ;
     RECT  4.32 100.501 6.072 104.819 ;
     RECT  7.8 94.405 8.232 107.125 ;
     RECT  7.44 107.125 8.232 107.315 ;
     RECT  4.32 104.819 5.976 110.533 ;
     RECT  4.272 110.533 5.976 111.685 ;
     RECT  7.44 107.315 8.112 111.685 ;
     RECT  2.4 72.563 2.712 112.597 ;
     RECT  4.272 111.685 8.112 112.643 ;
     RECT  4.992 112.643 8.112 115.669 ;
     RECT  4.32 115.669 8.112 116.963 ;
     RECT  4.992 116.963 8.112 117.925 ;
     RECT  4.32 117.925 8.112 118.547 ;
     RECT  2.4 112.597 3.288 119.653 ;
     RECT  4.32 118.547 5.976 119.653 ;
     RECT  7.104 118.547 8.112 120.083 ;
     RECT  2.4 119.653 5.976 120.757 ;
     RECT  2.4 120.757 6.552 123.491 ;
     RECT  4.512 123.491 6.552 124.835 ;
     RECT  2.4 123.491 3.48 125.845 ;
     RECT  4.512 124.835 5.976 125.845 ;
     RECT  2.4 125.845 5.976 125.891 ;
     RECT  7.8 120.083 8.112 127.045 ;
     RECT  4.32 125.891 5.976 132.757 ;
     RECT  4.272 132.757 5.976 136.165 ;
     RECT  7.056 127.045 8.112 136.165 ;
     RECT  4.272 136.165 8.112 138.467 ;
     RECT  4.272 138.467 6.552 138.563 ;
     RECT  4.32 138.563 6.552 140.435 ;
     RECT  4.32 140.435 6.312 142.547 ;
     RECT  4.32 142.547 5.976 143.123 ;
     RECT  2.4 125.891 2.712 144.729 ;
     RECT  7.8 138.467 8.112 144.729 ;
     RECT  10.5 2.151 10.812 144.729 ;
     RECT  13.2 2.151 13.512 144.729 ;
     RECT  15.9 2.151 16.212 144.729 ;
     RECT  18.6 2.151 18.912 144.729 ;
     RECT  2.4 144.729 2.52 144.743 ;
     RECT  5.1 143.123 5.976 144.743 ;
     RECT  7.8 144.729 7.92 144.743 ;
     RECT  10.5 144.729 10.62 144.743 ;
     RECT  13.2 144.729 13.32 144.743 ;
     RECT  15.9 144.729 16.02 144.743 ;
     RECT  18.6 144.729 18.72 144.743 ;
     RECT  5.952 144.743 5.976 146.771 ;
     RECT  5.784 7.957 7.056 9.731 ;
     RECT  4.464 8.579 5.1 9.637 ;
     RECT  5.544 9.731 7.056 10.981 ;
     RECT  5.544 10.981 6.864 12.997 ;
     RECT  5.784 12.997 6.864 15.347 ;
     RECT  5.64 19.861 6.864 21.155 ;
     RECT  5.64 21.155 5.688 22.021 ;
     RECT  5.688 23.317 7.008 25.429 ;
     RECT  5.736 25.429 7.008 26.579 ;
     RECT  4.512 30.851 5.1 31.813 ;
     RECT  5.688 34.453 6.864 39.635 ;
     RECT  3.672 35.603 5.1 39.877 ;
     RECT  5.688 39.635 7.056 41.557 ;
     RECT  5.688 41.557 7.008 43.285 ;
     RECT  3.48 41.651 4.464 42.707 ;
     RECT  3.48 42.707 4.512 44.483 ;
     RECT  6.024 43.285 7.008 43.813 ;
     RECT  6.024 48.275 7.056 54.133 ;
     RECT  3.288 49.333 4.32 51.011 ;
     RECT  3.288 51.011 4.464 58.259 ;
     RECT  5.688 62.435 6.864 69.011 ;
     RECT  4.272 62.771 4.992 63.205 ;
     RECT  3.192 63.205 4.992 63.973 ;
     RECT  3.192 63.973 4.656 66.755 ;
     RECT  3.192 66.755 4.704 70.981 ;
     RECT  5.592 69.011 6.864 71.221 ;
     RECT  3.288 70.981 4.704 71.315 ;
     RECT  2.712 80.341 4.224 82.213 ;
     RECT  2.712 82.213 4.176 86.195 ;
     RECT  5.976 82.739 7.056 87.827 ;
     RECT  5.976 87.827 7.392 91.763 ;
     RECT  5.976 107.125 7.44 111.685 ;
     RECT  3.288 112.597 4.272 112.643 ;
     RECT  3.288 115.669 4.32 116.963 ;
     RECT  3.288 116.963 4.992 117.925 ;
     RECT  3.288 117.925 4.32 119.653 ;
     RECT  5.976 118.547 7.104 120.083 ;
     RECT  5.976 120.083 7.8 120.757 ;
     RECT  6.552 120.757 7.8 124.835 ;
     RECT  3.48 123.491 4.512 125.845 ;
     RECT  5.976 127.045 7.056 136.165 ;
     RECT  6.552 138.467 7.8 140.435 ;
     RECT  6.312 140.435 7.8 142.547 ;
  END
END qfd_coll_eslice257
END LIBRARY
